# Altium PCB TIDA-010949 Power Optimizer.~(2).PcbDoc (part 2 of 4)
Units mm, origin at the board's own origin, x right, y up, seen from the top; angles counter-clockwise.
Board outline 129.4 x 84 mm, 4 copper layers (Power1, Ground1, Ground2, Power2), stack 1.926 mm thick; 262 components, 129 nets, 791 pads, 1191 vias.

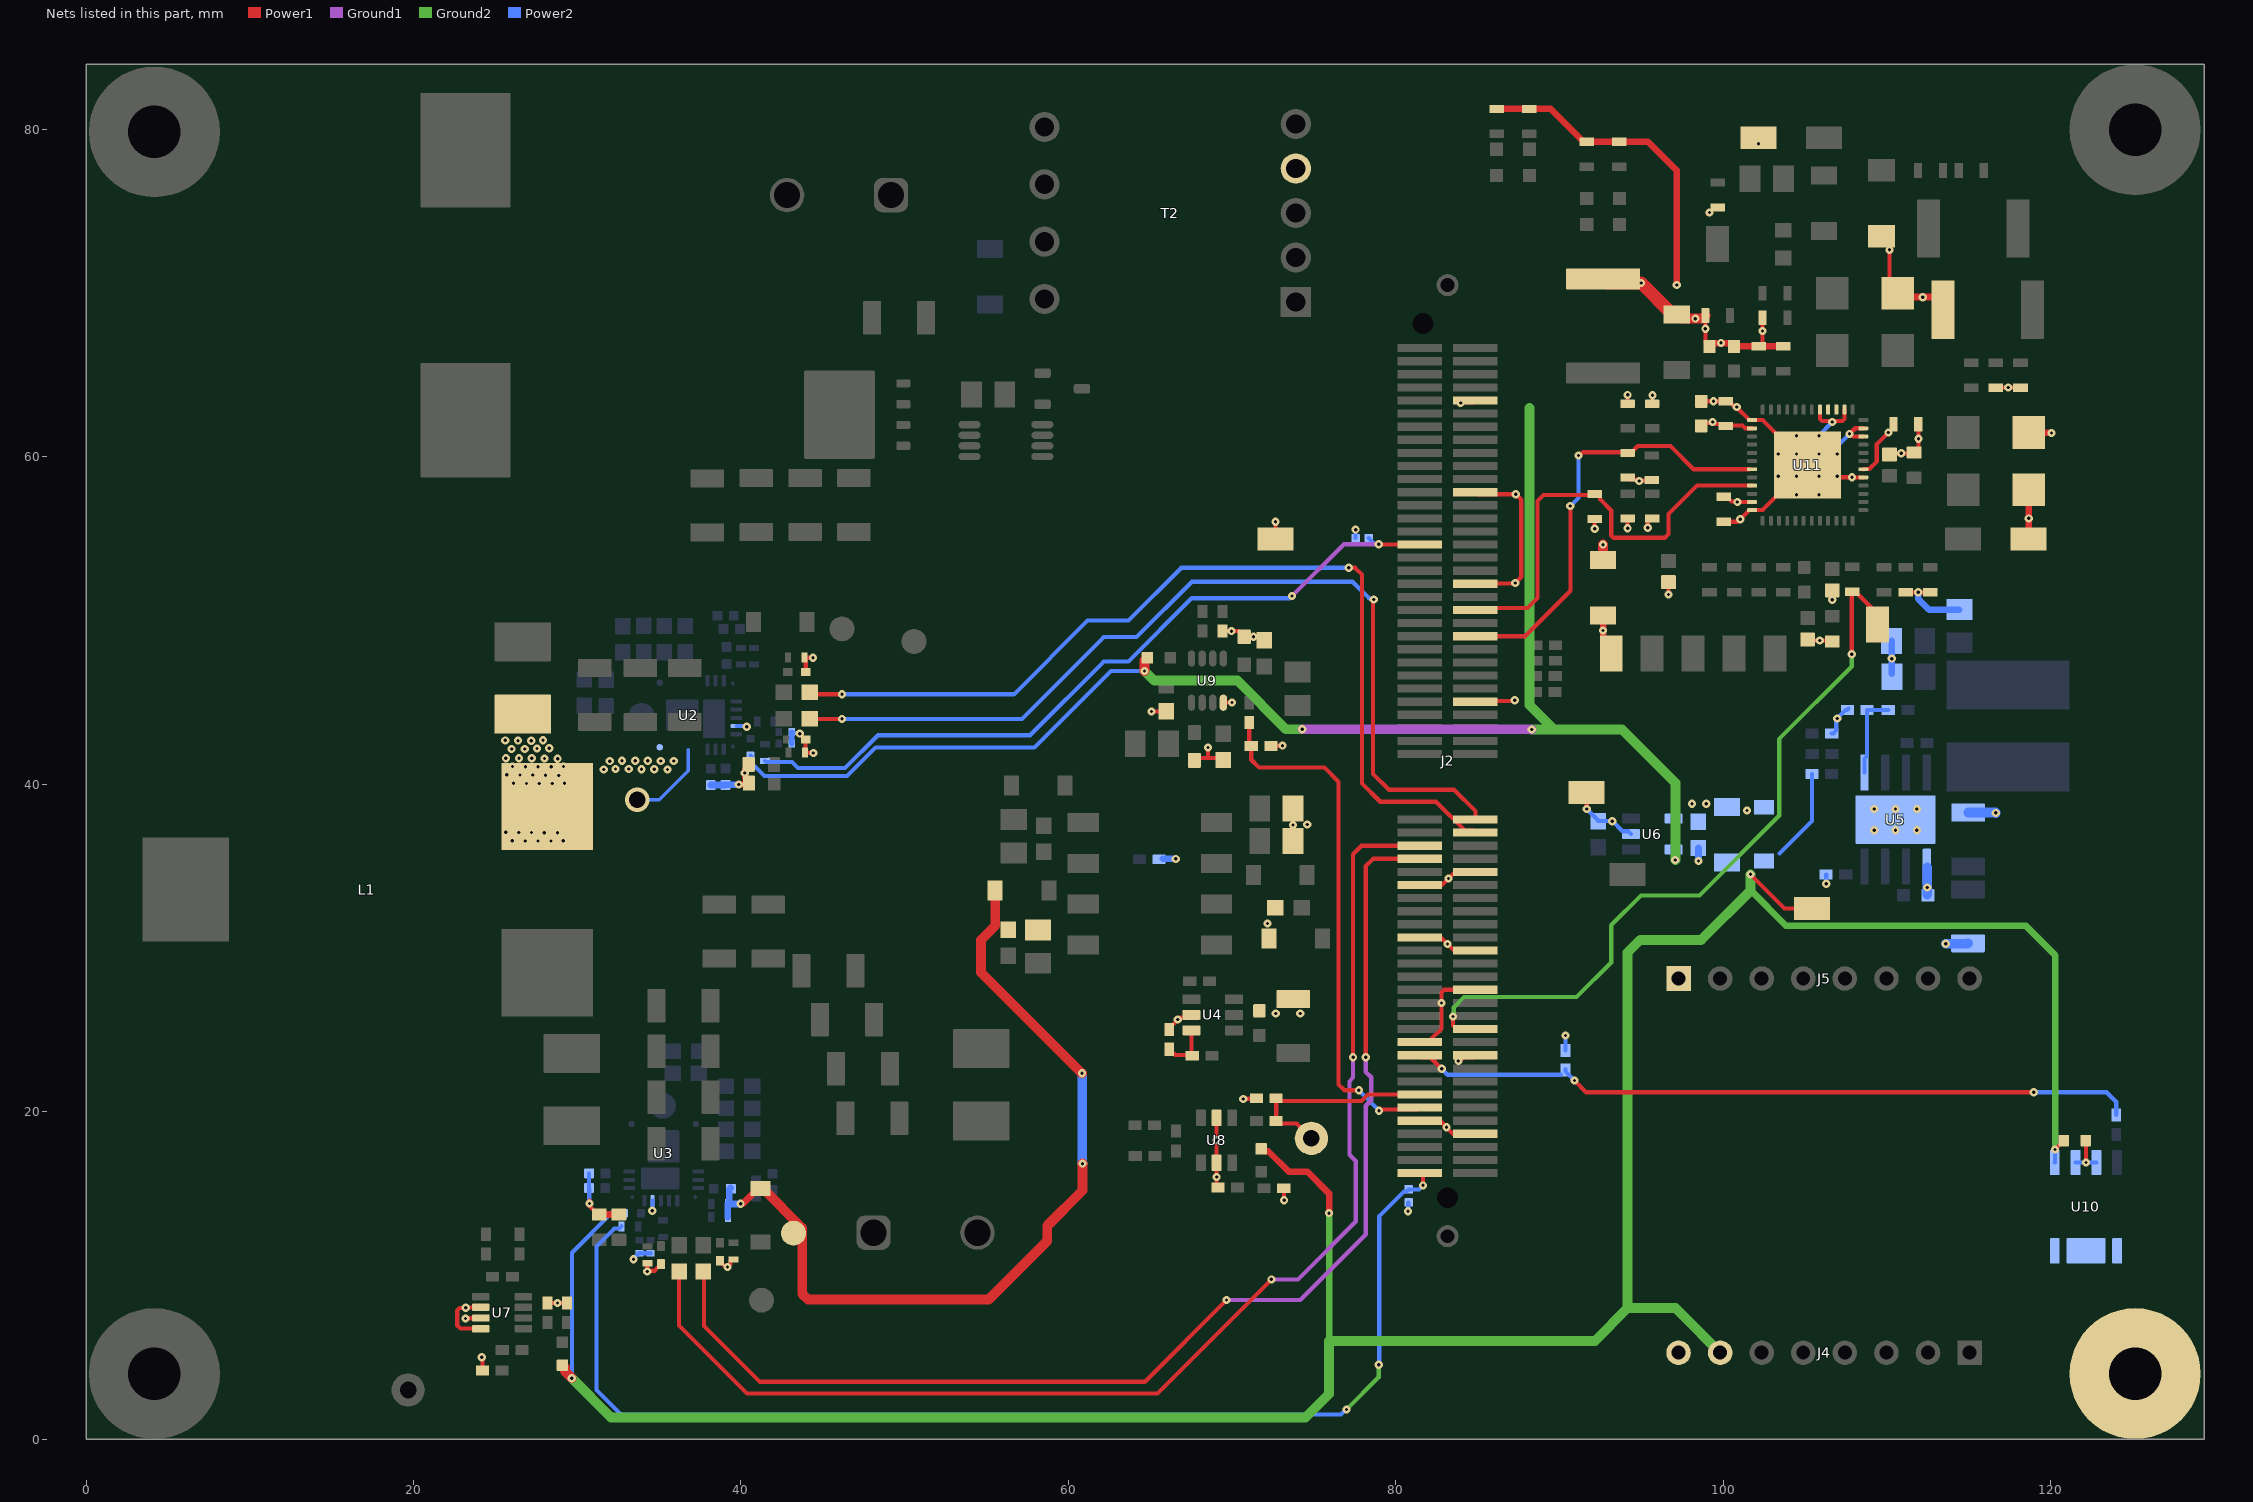
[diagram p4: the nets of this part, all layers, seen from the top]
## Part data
C1: library part CMP-0007679-2, "CAP, CERM, 2.2 uF, 16 V, +/- 10%, X5R, 0805", Cap_Case=0805, Manufacturer=AVX, Supplier Part Number 1=478-2580-1-ND, TempCo=X5R, Tolerance_%=10%, Value1="0.009 ohm", Value2=16V, ValueDisplayed=2.2uF
C2 C3 C4 C21 C22 C23 C24 C25 C26 C27 C28 C29: library part CMP-0077894-3, "CAP, CERM, 0.22 µF, 100 V,+/- 10%, X7S, AEC-Q200 Grade 1, 0603", Cap_Case=0603, Manufacturer="Taiyo Yuden", Supplier Part Number 1=587-5012-1-ND, TempCo=X7S, Tolerance_%=10%, Value2=100V, ValueDisplayed=0.22µF
C5 C6 C7 C8 C9 C10 C11 C12 C13 C14 C15 C16 C17 C18 C19 C20 C47 C52 C53 C60 C61: library part CMP-0087970-1, "10µF ±10% 100V Ceramic Capacitor X7S 1210 (3225 Metric)", Manufacturer=Murata, TempCo=22%, Tolerance_%=0.1, ValueDisplayed=10uF
C30 C31 C65 C67: library part CMP-0006659-2, "CAP, CERM, 0.1 uF, 25 V, +/- 10%, X7R, 0402", Cap_Case=0402, Manufacturer=MuRata, Supplier Part Number 1=490-10698-1-ND, TempCo=X7R, Tolerance_%=10%, Value1=Unknown, Value2=25V, ValueDisplayed=0.1uF
C32 C33 C34 C35: library part CMP-0097874-1, "10 pF ±1% 50V Ceramic Capacitor C0G, NP0 0402 (1005 Metric)", Digikey Part Number=478-5717-1-ND, Manufacturer="KYOCERA AVX", Mouser Part Number=581-04025U100FAT2A, Operating Temperature Range="-55°C to +125°C", TempCo=30ppm/°C, Temperature Characteristic=C0G, Tolerance_%=1%, ValueDisplayed=10pF
C36 C37 C40 C41: library part CMP-0089452-2, "2.2µF ±10% 16V Ceramic Capacitor X7S 0603 (1608 Metric)", Digikey Part Number=490-12731-1-ND, Manufacturer=Murata, Mouser Part Number=81-GRM188C71C225KE1D, Operating Temperature Range="-55°C to +125°C", TempCo=22%, Temperature Characteristic=X7S, Tolerance_%=10%, ValueDisplayed=2.2uF
C38 C42: library part CMP-0096845-1, "Multi-Layer Ceramic Capacitor 100pF 25V C0G ±5% 0402 Paper T/R", Manufacturer=Murata, Operating Temperature Range="-55°C to +125°C", TempCo=30ppm/°C, Temperature Characteristic=C0G, Tolerance_%=5%, ValueDisplayed=100pF
C39 C43: library part CMP-0096975-1, "Multi-Layer Ceramic Capacitor 1uF 25V X5R ±10% 0402 Paper T/R", Manufacturer=Murata, Operating Temperature Range="-55°C to +85°C", TempCo=0.15, Temperature Characteristic=X5R, Tolerance_%=10%, ValueDisplayed=1uF
C44 C45 C50 C51 C57 C58 C59: library part CMP-0007677-2, "CAP, CERM, 10 uF, 16 V, +/- 10%, X5R, 0805", Cap_Case=0805, Manufacturer=AVX, Supplier Part Number 1=478-5165-1-ND, TempCo=X5R, Tolerance_%=10%, Value1=Unknown, Value2=16V, ValueDisplayed=10uF
C46: library part CMP-0006201-2, "CAP, CERM, 0.1 uF, 16 V, +/- 10%, X7R, 0402", Cap_Case=0402, Manufacturer=AVX, Supplier Part Number 1=478-7888-1-ND, TempCo=X7R, Tolerance_%=10%, Value1=Unknown, Value2=16V, ValueDisplayed=0.1uF
C48 C55 C96 C97 C104: library part CMP-0094779-1, "Cap Ceramic 100nF 100V X7R 10% SMD 0603 125°C Paper T/R", Digikey Part Number=478-06031C104K4T2ACT-ND, Manufacturer="KYOCERA AVX", Mouser Part Number=581-06031C104K4T2A, Operating Temperature Range="-55°C to +125°C", TempCo=15%, Temperature Characteristic=X7R, Tolerance_%=10%, ValueDisplayed=100nF
C49: library part CMP-0006683-2, "CAP, CERM, 2200 pF, 50 V, +/- 10%, X7R, 0402", Cap_Case=0402, Manufacturer=MuRata, Supplier Part Number 1=490-1305-1-ND, TempCo=X7R, Tolerance_%=10%, Value1=Unknown, Value2=50V, ValueDisplayed=2200pF
C54 C77: library part CMP-0006752-5, "CAP, CERM, 0.1 uF, 25 V, +/- 5%, X7R, 0603", Cap_Case=0603, Manufacturer=AVX, Supplier Part Number 1=478-3713-1-ND, TempCo=X7R, Tolerance_%=5%, Value1="0.05 ohm", Value2=25V, ValueDisplayed=0.1uF
C56: library part CMP-0006640-2, "CAP, CERM, 0.1 uF, 16 V, +/- 5%, X7R, 0402", Cap_Case=0402, Manufacturer=MuRata, Supplier Part Number 1=490-6327-1-ND, TempCo=X7R, Tolerance_%=5%, Value1=Unknown, Value2=16V, ValueDisplayed=0.1uF
C62 C64: library part CMP-0006831-4, "CAP CER 1UF 16V Y5V 0603", Cap_Case=0603, Manufacturer=Yageo, PartNumber=CC0603MRY5V7BB105, Supplier Part Number 1=311-3414-1-ND, TempCo=X7R, Tolerance_%=10%, Value1=Unknown, Value2=16V, ValueDisplayed=1uF
C63: library part CMP-0008965-2, "CAP, CERM, 10 uF, 25 V, +/- 10%, X7R, 1206", Cap_Case=2220, Manufacturer=MuRata, Supplier Part Number 1=81-GRM31CR71E106KA12, TempCo=X7R, Tolerance_%=10%, Value1=Unknown, Value2=25V, ValueDisplayed=10uF
C66 C68: library part CMP-0078625-1, "CAP, CERM, 1 µF, 25 V,+/- 20%, X5R, 0402", Cap_Case=0402, Manufacturer=MuRata, Supplier Part Number 1=490-10018-1-ND, TempCo=X5R, Tolerance_%=20%, Value2=25V, ValueDisplayed=1µF
C69 C71: library part CMP-0006658-2, "CAP, CERM, 0.01 uF, 25 V, +/- 10%, X7R, 0402", Cap_Case=0402, Manufacturer=MuRata, Supplier Part Number 1=490-1312-1-ND, TempCo=X7R, Tolerance_%=10%, Value1=Unknown, Value2=25V, ValueDisplayed=0.01uF
C70 C72: library part CMP-0006389-2, "CAP, CERM, 470 pF, 25 V, +/- 5%, C0G/NP0, 0402", Cap_Case=0402, Manufacturer=MuRata, Supplier Part Number 1=GRM1555C1E471JA01D-ND, TempCo=C0G/NP0, Tolerance_%=5%, Value1=Unknown, Value2=25V, ValueDisplayed=470pF
C73 C75: library part CMP-0860530-1, "CAP, CERM, 1000 pF, 25 V,+/- 5%, C0G/NP0, 0603", Cap_Case=0603, Manufacturer=Yageo, TempCo=C0G/NP0, Tolerance_%=5%, Value2=25V, ValueDisplayed=1000pF
C74 C76: library part CMP-0006453-2, "CAP, CERM, 300 pF, 50 V, +/- 5%, C0G/NP0, 0402", Cap_Case=0402, Manufacturer=MuRata, Supplier Part Number 1=490-3234-1-ND, TempCo=C0G/NP0, Tolerance_%=5%, Value1=Unknown, Value2=50V, ValueDisplayed=300pF
C78 C79: library part CMP-0006608-2, "CAP, CERM, 1 uF, 25 V, +/- 10%, X5R, 0402", Cap_Case=0402, Manufacturer=MuRata, Supplier Part Number 1=490-10017-1-ND, TempCo=X5R, Tolerance_%=10%, Value1=Unknown, Value2=25V, ValueDisplayed=1uF
C80 C83 C93 C95: library part CMP-0045719-1, "1000 pF ±10% 50V Ceramic Capacitor X7R 0603 (1608 Metric)", Digikey Part Number=399-C0603X102K5RAC7867CT-ND, Manufacturer=KEMET, Mouser Part Number=80-C0603X102K5R, Operating Temperature Range="-55°C to +125°C", TempCo=15%, Temperature Characteristic=X7R, Tolerance_%=10%, ValueDisplayed=1000pF
C81 C101 C106: library part CMP-0009015-2, "CAP, CERM, 10 uF, 50 V, +/- 10%, X5R, AEC-Q200 Grade 1, 1206", Cap_Case=1206, Manufacturer=MuRata, Supplier Part Number 1=490-12456-1-ND, TempCo=X5R, Tolerance_%=10%, Value1=Unknown, Value2=50V, ValueDisplayed=10uF
C82: library part CMP-0089171-1, "3300pF ±5% 100V Ceramic Capacitor X7R 0603 (1608 Metric)", Digikey Part Number=478-7420-1-ND, Manufacturer="AVX Corporation", Mouser Part Number=581-06031C332J4Z2A, Operating Temperature Range="-55°C to +125°C", TempCo=15%, Temperature Characteristic=X7R, Tolerance_%=5%, ValueDisplayed=3300pF
C84: library part CMP-0008779-2, "CAP, CERM, 1 uF, 100 V, +/- 10%, X7R, AEC-Q200 Grade 1, 1206", Cap_Case=1206_180, Manufacturer=TDK, Supplier Part Number 1=445-5845-1-ND, TempCo=X7R, Tolerance_%=10%, Value1="0.004575 ohm", Value2=100V, ValueDisplayed=1uF
C85: library part CMP-0007433-4, "CAP, CERM, 0.01 uF, 50 V, +/- 10%, X7R, 0603", Cap_Case=0603, Manufacturer=MuRata, Supplier Part Number 1=490-1512-1-ND, TempCo=X7R, Tolerance_%=10%, Value1=Unknown, Value2=50V, ValueDisplayed=0.01uF
C86 C99 C100 C102 C103 C105: library part CMP-0750039-1, "CAP, CERM, 0.01 µF, 50 V,+/- 10%, X7R, 0603", Cap_Case=0603, Manufacturer="Wurth Elektronik", TempCo=X7R, Tolerance_%=10%, Value2=50V, ValueDisplayed=0.01µF
C87: library part CMP-0007192-4, "CAP, CERM, 1800 pF, 50 V, +/- 5%, C0G/NP0, 0603", Cap_Case=0603, Manufacturer=MuRata, Supplier Part Number 1=490-1457-1-ND, TempCo=C0G/NP0, Tolerance_%=5%, Value1=Unknown, Value2=50V, ValueDisplayed=1800pF
C88: library part CMP-0006764-4, "CAP, CERM, 1000 pF, 50 V, +/- 10%, C0G/NP0, 0603", Cap_Case=0603, Manufacturer=AVX, Supplier Part Number 1=478-3718-1-ND, TempCo=C0G/NP0, Tolerance_%=10%, Value1="0.048 ohm", Value2=50V, ValueDisplayed=1000pF
C89: library part CMP-0007164-4, "CAP, CERM, 560 pF, 25 V, +/- 5%, C0G/NP0, 0603", Cap_Case=0603, Manufacturer=MuRata, Supplier Part Number 1=GRM1885C1E561JA01D-ND, TempCo=C0G/NP0, Tolerance_%=5%, Value1=Unknown, Value2=25V, ValueDisplayed=560pF
C90: library part CMP-0007203-4, "CAP, CERM, 270 pF, 50 V, +/- 5%, C0G/NP0, 0603", Cap_Case=0603, Manufacturer=MuRata, Supplier Part Number 1=490-1437-1-ND, TempCo=C0G/NP0, Tolerance_%=5%, Value1=Unknown, Value2=50V, ValueDisplayed=270pF
C91: library part CMP-0006729-4, "CAP, CERM, 1200 pF, 100 V, +/- 5%, X7R, 0603", Cap_Case=0603, Manufacturer=AVX, Supplier Part Number 1=478-3702-1-ND, TempCo=X7R, Tolerance_%=5%, Value1="0.254 ohm", Value2=100V, ValueDisplayed=1200pF
C92 C94: library part CMP-0122291-1, "1 µF ±10% 50V Ceramic Capacitor X7T 0603 (1608 Metric)", Digikey Part Number=490-GCM188D71H105KE36JCT-ND, Manufacturer=Murata, Mouser Part Number=81-GCM188D71H105KE6J, Operating Temperature Range="-55°C to +125°C", TempCo=+22/-33%, Temperature Characteristic=X7T, Tolerance_%=10%, ValueDisplayed=1uF
C98: library part CMP-0093976-1, "Cap Ceramic 47uF 25V X7R 20% Pad SMD 2220 +125°C Automotive T/R", Manufacturer=TDK, Operating Temperature Range="-55°C to +125°C", TempCo=0.15, Temperature Characteristic=X7R, Tolerance_%=0.2%, ValueDisplayed=47uF
C107: library part CMP-0090409-1, "0.1µF ±10% 16V Ceramic Capacitor X7R 0603 (1608 Metric)", Digikey Part Number=490-5796-1-ND, Manufacturer="Murata Electronics North America", Mouser Part Number=81-GCJ188R71C104KA1D, Operating Temperature Range="-55°C to +125°C", TempCo=15%, Temperature Characteristic=X7R, Tolerance_%=10%, ValueDisplayed=0.1uF
C108: library part CMP-0006561-2, "CAP, CERM, 0.01 uF, 10 V, +/- 10%, X5R, 0402", Cap_Case=0402, Manufacturer=MuRata, Supplier Part Number 1=GRM155R61A103KA01D-ND, TempCo=X5R, Tolerance_%=10%, Value1=Unknown, Value2=10V, ValueDisplayed=0.01uF
C109 C110: library part CMP-0098338-1, "100 pF ±5% 16V Ceramic Capacitor C0G, NP0 0402 (1005 Metric)", Digikey Part Number=399-C0402C101J4GAC7867CT-ND, Manufacturer=KEMET, Mouser Part Number=80-C0402C101J4G, Operating Temperature Range="-55°C to +125°C", TempCo=30ppm/°C, Temperature Characteristic=C0G, Tolerance_%=5%, ValueDisplayed=100pF
D1 D4 D5: library part CMP-0028543-2, "Diode, Schottky, 40 V, 0.35 A, SOD-123", Manufacturer="Diodes Inc.", Value1=0.35A, Value2=0.55V
D2 D3 D6: library part CMP-0077599-3, "Diode, Zener, 5.1 V, 500 mW, SOD-123", Manufacturer=Vishay-Semiconductor, Power_W=500mW, Value1=0.5W
D7 D15: library part CMP-0002946-3, "LED, Blue, SMD", Color=Blue, Manufacturer="Wurth Elektronik", Power_TotalModule=105mW, Value1=0.105W, Value2=3.2V
D8: library part CMP-0005782-1, "Diode, Zener, 3.6 V, 500 mW, SOD-123", Manufacturer="ON Semiconductor", PartNumber=MMSZ4685T1G, Power_W=500mW, Supplier Part Number 1=MMSZ4685T1GOSCT-ND, Value1=0.5W
D9 D11 D13 D14: library part CMP-0028416-2, "Diode, Schottky, 50 V, 3 A, SMA", Manufacturer="Diodes Inc.", Value1=3A, Value2=0.7V
D10: library part CMP-0085011-1, "Diode, TVS, Bi, 22 V, 35.5 Vc, 400 W, 11.3 A, SMA (non-polarized)", Manufacturer=Littelfuse, Value1=35.5V
D12 D16: library part CMP-0002947-3, "LED, Red, SMD", Color=Red, Manufacturer="Wurth Elektronik", Power_TotalModule=72mW, Value1=0.072W, Value2=2V
FB1 FB2 FB3: library part CMP-0037505-1, "600 Ohms @ 100 MHz 1 Power, Signal Line Ferrite Bead 0603 (1608 Metric) 1A 200mOhm", Digikey Part Number=MH1608-601YCT-ND, Impedance At Frequency="600Ω @ 100MHz", Manufacturer=Bourns, Mouser Part Number=652-MH1608-601Y, Operating Temperature Range="-55°C to +125°C", Test Frequency=100MHz, Tolerance_%=25%
H1 H2 H3 H4: library part CMP-0003617-1, "Machine Screw, Round, #4-40 x 1/4, Nylon, Philips panhead", Manufacturer="B&F Fastener Supply", Supplier Part Number 1=H542-ND
H5 H6 H7 H8: library part CMP-0003610-1, "Standoff, Hex, 0.5\"L #4-40 Nylon", Manufacturer=Keystone, Supplier Part Number 1=36-1902C-ND
J1 J3: library part CMP-0075360-1, "Terminal Block, 6.35mm, 2x1, TH", Color=Green, Current_A=30A, Manufacturer="On-Shore Technology", Supplier Part Number 1=ED2675-ND, Voltage_V=300V
J2: library part CMP-0003814-2, "C2000 controlCARD-120HSEC connector, SMT", Manufacturer=Samtec
J4 J5: library part CMP-0055090-1, "Header, 100mil, 8x1, TH", Manufacturer=Mill-Max, Supplier Part Number 1=ED7208-ND
L1: library part CMP-0086005-1, "Inductor, Shielded, Ferrite, 10 µH, 30 A, 0.0024 ohm, SMD", Manufacturer="Wurth Elektronik", Value1="0.0024 ohm", Value2=30A, ValueDisplayed=10µH
L2: library part CMP-0102060-1, "WE-PD2SA SMT Power Inductor, size 7850, 68uH, 1.12A, 290mOhm", Case/Size Code=7850, DC Resistance=246mOhm, DC Resistance Max=290mOhm, Inductance=68uH, Manufacturer="Wurth Elektronik", Operating Temperature Max=150°C, Operating Temperature Min=-50°C, Rated Current=1.12A, Saturation Current=1A, Self Resonant Frequency=7.5MHz
L3: library part CMP-0058657-1, "Inductor, Wirewound, Ferrite, 1 uH, 0.595 A, 0.25 ohm, SMD", Manufacturer=MuRata, Value1="0.25 ohm", Value2=0.595A, ValueDisplayed=1uH
L4: library part CMP-0089572-1, "12µH Shielded Wirewound Inductor 19A 4.3mOhm Nonstandard", Digikey Part Number=732-4236-1-ND, Manufacturer="Wurth Electronics", Mouser Part Number=710-74435581200, Operating Temperature Range="-40°C to +125°C", Self Resonant Frequency=13MHz, Test Frequency=100kHz, Tolerance_%=20%
L5: library part CMP-0061680-2, "Inductor, Drum Core, Ferrite, 1 mH, 0.1 A, 19 ohm, SMD", Manufacturer=Coilcraft, Value1="19 ohm", Value2=0.1A, ValueDisplayed=1mH
L6: library part CMP-0061972-2, "Inductor, Drum Core, Ferrite, 1.5 mH, 0.08 A, 21 ohm, SMD", Manufacturer=Coilcraft, Value1="21 ohm", Value2=0.08A, ValueDisplayed=1.5mH
LBL1: library part CMP-0003625-1, "Thermal Transfer Printable Labels, 0.650\" W x 0.200\" H - 10,000 per roll", Manufacturer=Brady, Supplier Part Number 1=97C5133
Logo1: library part CMP-0074838-1, "Texas Instrument Corporate Signature"
Logo2: library part CMP-0074844-1
Logo3: library part CMP-0074847-1, "FCC_disclaimer"
Logo4: library part CMP-0074769-1
Q1: library part CMP-0000958-3, "MOSFET, N-CH, 100 V, 17 A, DNK0008A (VSON-CLIP-8)", Alternate Manufacturer=None, Manufacturer="Texas Instruments", Supplier Part Number 1=296-37478-6-ND, Value2="48 nC"
Q2: library part CMP-0000949-3, "MOSFET, N-CH, Depletion Mode, 100 V, 0.17 A, AEC-Q101, SOT-23", Alternate Manufacturer=None, Manufacturer="Infineon Technologies", Supplier Part Number 1="BSS169 H6327-ND", Value2="2.1 nC"
R1: library part CMP-0094948-1, "0 Ohms Jumper 0.1W, 1/10W Chip Resistor 0402 (1005 Metric) - Thick Film", Digikey Part Number=2679-CR0402-10W-000TTR-ND, Manufacturer=Venkel, Operating Temperature Range="-55°C to +155°C", Power_W=100mW
R2 R6 R35: library part CMP-0042666-1, "Res Metal Strip 2512 0.001 Ohm 1% 3W ±50ppm/C Pad SMD Automotive T/R", Manufacturer="TT Electronics", Mouser Part Number=66-ULRG3R001FLFSLT, Operating Temperature Range=to, Power_W=3W, TempCo=50ppm/°C, Tolerance_%=1%
R3 R4: library part CMP-0097912-1, "Res Thick Film 0402 0 Ohm 1/16W Molded SMD", Digikey Part Number=541-1887-1-ND, Manufacturer="Vishay Dale", Mouser Part Number=71-RCG04020000Z0ED, Operating Temperature Range="-55°C to +155°C", Power_W=63mW
R5 R7: library part CMP-0026262-2, "RES, 2.00, 1%, 0.063 W, AEC-Q200 Grade 0, 0402", Manufacturer=Vishay-Dale, Power_W=63mW, Supplier Part Number 1=541-2.00LLCT-ND, TempCo="100 ppm/C", Tolerance_%=1%, Value2=0.063W, Value_Code=2R00, ValueDisplayed=2.00
R8 R9 R14 R15: library part CMP-0078781-1, "RES, 10.5 k, 1%, 0.063 W, 0402", Manufacturer="Yageo America", Power_W=63mW, Supplier Part Number 1=YAG2951CT-ND, TempCo="100 ppm/C", Tolerance_%=1%, Value2=0.063W, Value_Code=10k5, ValueDisplayed=10.5k
R10 R11 R12 R13: library part CMP-0022908-4, "RES, 20.0, 1%, 0.1 W, 0603", Manufacturer=Yageo, Power_W=100mW, Supplier Part Number 1=311-20.0HRCT-ND, TempCo="100 ppm/C", Tolerance_%=1%, Value2=0.1W, Value_Code=20R0, ValueDisplayed=20.0
R16 R17 R58: library part CMP-0022895-5, "RES, 1.00 k, 1%, 0.1 W, 0603", Manufacturer=Yageo, Power_W=100mW, Supplier Part Number 1=311-1.00KHRCT-ND, TempCo="100 ppm/C", Tolerance_%=1%, Value2=0.1W, Value_Code=1k00, ValueDisplayed=1.00k
R18 R24 R26 R27 R28 R73 R75: library part CMP-0026936-3, "RES, 47, 5%, 0.063 W, AEC-Q200 Grade 0, 0402", Manufacturer=Vishay-Dale, Power_W=63mW, Supplier Part Number 1=541-47JCT-ND, TempCo="200 ppm/C", Tolerance_%=5%, Value2=0.063W, Value_Code=47R0, ValueDisplayed=47
R19: library part CMP-0025971-3, "RES, 115 k, 1%, 0.063 W, AEC-Q200 Grade 0, 0402", Manufacturer=Vishay-Dale, Power_W=63mW, Supplier Part Number 1=541-115KLCT-ND, TempCo="100 ppm/C", Tolerance_%=1%, Value2=0.063W, Value_Code=115k
R20: library part CMP-0026457-2, "RES, 57.6 k, 1%, 0.063 W, AEC-Q200 Grade 0, 0402", Manufacturer=Vishay-Dale, Power_W=63mW, Supplier Part Number 1=541-57.6KLCT-ND, TempCo="100 ppm/C", Tolerance_%=1%, Value2=0.063W, Value_Code=57k6, ValueDisplayed=57.6k
R21 R23: library part CMP-0026825-5, "RES, 10 k, 5%, 0.063 W, AEC-Q200 Grade 0, 0402", Manufacturer=Vishay-Dale, Power_W=63mW, Supplier Part Number 1=541-10KJCT-ND, TempCo="200 ppm/C", Tolerance_%=5%, Value2=0.063W, Value_Code=10k0, ValueDisplayed=10k
R22: library part CMP-0026543-2, "RES, 75.0 k, 1%, 0.063 W, AEC-Q200 Grade 0, 0402", Manufacturer=Vishay-Dale, Power_W=63mW, Supplier Part Number 1=541-75.0KLCT-ND, TempCo="100 ppm/C", Tolerance_%=1%, Value2=0.063W, Value_Code=75k0, ValueDisplayed=75.0k
R25: library part CMP-0025958-3, "RES, 10.0 k, 1%, 0.063 W, AEC-Q200 Grade 0, 0402", Manufacturer=Vishay-Dale, Power_W=63mW, Supplier Part Number 1=541-10.0KLCT-ND, TempCo="100 ppm/C", Tolerance_%=1%, Value2=0.063W, Value_Code=10k0, ValueDisplayed=10.0k
R29 R61 R62 R76: library part CMP-0025936-5, "RES, 680, 5%, 0.1 W, 0603", Manufacturer=Yageo, Power_W=100mW, Supplier Part Number 1=311-680GRCT-ND, TempCo="100 ppm/C", Tolerance_%=5%, Value2=0.1W, Value_Code=680R, ValueDisplayed=680
R30 R38: library part CMP-0025923-5, "RES, 43 k, 5%, 0.1 W, 0603", Manufacturer=Yageo, Power_W=100mW, Supplier Part Number 1=311-43KGRCT-ND, TempCo="100 ppm/C", Tolerance_%=5%, Value2=0.1W, Value_Code=43k0, ValueDisplayed=43k
R31 R32 R63: library part CMP-0026751-1, "RES, 47.0, 1%, 0.063 W, 0402", Manufacturer="KOA Speer", Power_W=63mW, Supplier Part Number 1=660-RK73H1ETTP47R0F, TempCo="100 ppm/C", Tolerance_%=1%, Value2=0.063W, Value_Code=47R0, ValueDisplayed=47.0
R33 R34 R36 R37: library part CMP-0026749-1, "RES, 10.0, 1%, 0.063 W, 0402", Manufacturer="KOA Speer", Power_W=63mW, Supplier Part Number 1=660-RK73H1ETTP10R0F, TempCo="100 ppm/C", Tolerance_%=1%, Value2=0.063W, Value_Code=10R0, ValueDisplayed=10.0
R39 R51: library part CMP-0025928-5, "RES, 510, 5%, 0.1 W, 0603", Manufacturer=Yageo, Power_W=100mW, Supplier Part Number 1=311-510GRCT-ND, TempCo="100 ppm/C", Tolerance_%=5%, Value2=0.1W, Value_Code=510R, ValueDisplayed=510
R40 R41: library part CMP-0019234-2, "RES, 30.1 k, 0.5%, 0.1 W, 0805", Manufacturer="Susumu Co Ltd", Power_W=100mW, Supplier Part Number 1=RR12P30.1KDCT-ND, TempCo="25 ppm/C", Tolerance_%=0.5%, Value2=0.1W, Value_Code=30k1, ValueDisplayed=30.1k
R42 R44: library part CMP-0026454-2, "RES, 56.2, 1%, 0.063 W, AEC-Q200 Grade 0, 0402", Manufacturer=Vishay-Dale, Power_W=63mW, Supplier Part Number 1=541-56.2LCT-ND, TempCo="100 ppm/C", Tolerance_%=1%, Value2=0.063W, Value_Code=56R2, ValueDisplayed=56.2
R43 R45: library part CMP-0088560-2, "High Precision-High Stability Chip Resistor Thin Film 0603 1kOhm 0.1% Paper T/R", Digikey Part Number=YAG1237CT-ND, Manufacturer=Yageo, Mouser Part Number=603-RT0603BRD071KL, Operating Temperature Range="-55°C to +155°C", Power_W=100mW, TempCo=25ppm/°C, Tolerance_%=0.1%
R46 R47 R48 R49 R53 R54 R60: library part CMP-0098286-1, "10 kOhms ±5% 0.1W, 1/10W Chip Resistor 0603 (1608 Metric) Thick Film", Digikey Part Number=541-CRCW060310K0JNEBCCT-ND, Manufacturer=Vishay, Mouser Part Number=71-CRCW060310K0JNEBC, Operating Temperature Range="-55°C to +155°C", Power_W=100mW, TempCo=200ppm/°C, Tolerance_%=5%
R50 R52: library part CMP-0022735-5, "RES, 100 k, 1%, 0.1 W, 0603", Manufacturer=Yageo, Power_W=100mW, Supplier Part Number 1=311-100KHRCT-ND, TempCo="100 ppm/C", Tolerance_%=1%, Value2=0.1W, Value_Code=100k
R55: library part CMP-0025913-5, "RES, 33 k, 5%, 0.1 W, 0603", Manufacturer=Yageo, Power_W=100mW, Supplier Part Number 1=311-33KGRCT-ND, TempCo="100 ppm/C", Tolerance_%=5%, Value2=0.1W, Value_Code=33k0, ValueDisplayed=33k
R56: library part CMP-0020737-3, "RES, 4.7, 5%, 0.125 W, AEC-Q200 Grade 0, 0805", Manufacturer=Panasonic, Power_W=125mW, Supplier Part Number 1=P4.7ACT-ND, TempCo="600 ppm/C", Tolerance_%=5%, Value2=0.125W, Value_Code=4R70, ValueDisplayed=4.7
R57: library part CMP-0025912-5, "RES, 330, 5%, 0.1 W, 0603", Manufacturer=Yageo, Power_W=100mW, Supplier Part Number 1=311-330GRCT-ND, TempCo="100 ppm/C", Tolerance_%=5%, Value2=0.1W, Value_Code=330R, ValueDisplayed=330
R59: library part CMP-0022986-5, "RES, 2.20 k, 1%, 0.1 W, 0603", Manufacturer=Yageo, Power_W=100mW, Supplier Part Number 1=311-2.20KHRCT-ND, TempCo="100 ppm/C", Tolerance_%=1%, Value2=0.1W, Value_Code=2k20, ValueDisplayed=2.20k
R64 R65 R66 R67 R68 R69 R70 R71: library part CMP-0031873-1, "0 Ohms Jumper Chip Resistor 0402 (1005 Metric) Anti-Sulfur, Current Sense, Flame Retardant Coating, Moisture Resistant, Safety Metal Foil", Digikey Part Number=4463-D1LPC0402CJUMPF-T10CT-ND, Manufacturer="Thin Film Technology", Max Current=20A, Operating Temperature Range="-55°C to +170°C"
R72 R74: library part CMP-0094624-1, "4.7 kOhms ±5% 0.1W, 1/10W Chip Resistor 0402 (1005 Metric) Automotive AEC-Q200 Thick Film", Digikey Part Number=10-ERJ-H2GJ472XCT-ND, Manufacturer=Panasonic, Mouser Part Number=667-ERJ-H2GJ472X, Operating Temperature Range="-55°C to +175°C", Power_W=100mW, TempCo=200ppm/°C, Tolerance_%=5%
T1: library part "EP7, 070-7148", "EP7 8-Term., SMT, Horizontal", Manufacturer="Würth Elektronik Midcom", Package=EP7
T2: library part CMP-0030703-1, "Transformer, 870uH. TH", Manufacturer="Wurth Elektronik", ValueDisplayed=870uH
TP1 TP13 TP14 TP15 TP18 TP19 TP20 TP21 TP22 TP23 TP24 TP25 TP26 TP27 TP28: library part CMP-0003968-1, "Test Point, SMT", Manufacturer=Harwin, Supplier Part Number 1=952-2664-1-ND
TP16 TP17: library part CMP-0055138-2, "Test Point, Miniature, Black, TH", Color=Black, Manufacturer="Keystone Electronics", Supplier Part Number 1=36-5001-ND
U1: library part CMP-0076397-2, "Zero Iq Reverse Polarity Protection Smart Diode Controller, DGK0008A (VSSOP-8)", Alternate Manufacturer="Texas Instruments"
U2 U3: library part CMP-0120692-1, "100-V, 53-A GaN Half-Bridge Power Stage", Manufacturer="Texas Instruments", Max Supply Voltage=5.25V, Min Supply Voltage=4.75V, Nominal Supply Current=12mA, Operating Temperature Range="-40°C to +125°C"
U4: library part CMP-0121876-1, "SIMPLE SWITCHER® Power Converter, 4-V to 42-V, 1-A Buck Converter, SOT23", Manufacturer="Texas Instruments", Max Supply Voltage=42V, Min Supply Voltage=4V, Nominal Supply Current=26.5-420uA, Operating Temperature Range="-40°C to +150°C", Output Voltage=0.8-28V, Switching Frequency=400kHz
U5: library part CMP-0089262-2, "Buck Switching Regulator IC Positive Adjustable 1.2V 1 Output 1A 8-PowerSOIC (0.154\", 3.90mm Width)", Digikey Part Number=296-LM5164DDARCT-ND, Manufacturer="Texas Instruments", Max Supply Voltage=100V, Min Supply Voltage=6V, Mouser Part Number=595-LM5164DDAR, Nominal Supply Current=600uA, Operating Temperature Range="-40°C to +150°C", Output Voltage=1.2-90V, Switching Frequency=1MHz
U6: library part CMP-0092532-1, "300-mA, Ultra-Low-Noise, Low-IQ, High PSRR LDO", Digikey Part Number=296-TPS7A2033PDBVRCT-ND, Dropout Voltage=145mV, Manufacturer="Texas Instruments", Max Supply Voltage=6V, Min Supply Voltage=1.6V, Mouser Part Number=595-TPS7A2033PDBVR, Nominal Supply Current=6.5uA, Operating Temperature Range="-40°C to +125°C", Output Voltage=3.3V
U7: library part CMP-0096511-2, "-4-V to 110-V, Bidirectional, Ultra-Precise Current Sense Amplifier With Enhanced PWM Rejection", Input Bias Current=40uA, Input Offset Voltage=0.025mV, Manufacturer="Texas Instruments", Max Supply Voltage=20V, Min Supply Voltage=2.7V, Nominal Supply Current=2.5mA, Operating Temperature Range="-40°C to +125°C", Voltage Gain=0.05V/mV
U8: library part CMP-0013234-2, "Bidirectional, Low- and High-Side Measurement, Multichannel, Voltage Output, Current-Sense Amplifier, DBV0006A (SOT-6)", Alternate Manufacturer="Texas Instruments"
U9: library part CMP-0086102-1, "TLV9002IDDFR, DDF0008A (SOT-23-THN-8)", Alternate Manufacturer="Texas Instruments"
U10: library part CMP-0122473-1, "Automotive ±1.5°C, 3-kVRMS Isolated Temperature Sensor With Analog Output With < 2 Seconds Response Time and 500VRMS Working Voltage", Manufacturer="Texas Instruments", Max Supply Voltage=5.5V, Min Supply Voltage=2.3V, Operating Supply Current=10uA, Operating Temperature Range="-40°C to +150°C"
U11: library part CMP-0040436-2, "Powerline Communications Analog Front End, 7 to 26 V, -40 to 125 degC, 48-pin QFN (RGZ48), Green (RoHS & no Sb/Br)", Manufacturer="Texas Instruments", Rating=Catalog, Total Supply Voltage(Max)(+5V is 5, +/-5V is 10)=26, Total Supply Voltage(Min)(+5V is 5, +/-5V is 10)=7
?: library part CMP-0074835-1, "IEC 61010-1 High Voltage Warning"

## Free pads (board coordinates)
  round 1.524 smd: 2(43.213,12.58) 3(41.267,8.486) 4(46.174,49.5) 5(50.58,48.73)

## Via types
v1: diameter 0.5, hole 0.2, Power1 to Power2, tented both sides, 1183 vias
v2: diameter 1.5, hole 1, Power1 to Power2, 4 vias
v3: diameter 3.508, hole 3.1, Power1 to Power2, tented both sides, 4 vias

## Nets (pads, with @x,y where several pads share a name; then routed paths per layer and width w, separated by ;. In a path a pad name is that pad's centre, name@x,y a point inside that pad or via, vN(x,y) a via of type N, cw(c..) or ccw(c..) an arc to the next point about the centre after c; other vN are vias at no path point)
3V3: C62.1 C63.1 C102.1 C103.1 C104.2 C105.1 C106.1 C107.2 D8.1 D13.1 FB1.1 FB2.1 FB3.1 J4.7 R21.2 R29.2 R46.2 R47.2 R48.2 R49.2 R55.1 R61.2 R62.2 R72.2 R74.2 R76.2 TP15.1 U6.5 U10.1 U11.2 U11.11 U11.30 | length 303.5
  Power1 w0.254: R61.2@91.483,79.262 R61.2@91.674,79.262 ; v1(92.16,55.618) R55.1@92.16,56.213 ; v1@94.167,63.8 v1(94.174,63.794) R47.2@94.174,63.25 ; v1(94.174,55.643) R46.2@94.174,56.25 ; v1(95.398,55.681) 95.399,55.682 95.399,56.127 95.522,56.25 R48.2@95.674,56.25 ; R49.2@95.674,63.25 95.69,63.266 v1(95.69,63.776) ; C104.2@98.67,61.9 98.852,62.081 99.318,62.081 v1(99.366,62.13) 99.435,62.13 99.55,62.015 100.043,62.015 C105.1@100.17,61.888 100.194,61.912 101.194,61.912 101.349,61.757 101.767,61.757 U11.2@101.774,61.75 ; C102.1@100.045,57.562 100.235,57.562 100.362,57.435 100.362,57.424 100.511,57.275 100.851,57.275 v1(100.876,57.25) U11.11@101.774,57.25 ; v1(101.674,34.5) 103.757,32.417 TP15.1@105.424,32.417 ; U11.30@108.574,59.25 108.581,59.257 108.933,59.257 109.397,59.72 109.397,60.794 110.412,61.81 C103.1@110.412,62 ; v1(120.287,17.687) 120.813,18.213 C107.2@120.813,18.238
  Power1 w0.4: FB2.1@71.789,17.737 71.939,17.587 72.22,17.587 73.464,16.343 74.601,16.343 75.935,15.009 v1(75.935,13.804) ; R29.2@86.174,81.262 R76.2@88.174,81.262 89.483,81.262 R61.2@91.483,79.262 ; R61.2@91.674,79.262 R62.2@93.674,79.262 95.412,79.262 97.174,77.5 v1(97.174,70.5) ; D13.1@118.674,61.5 118.706,61.467 v1(120.066,61.467)
  Power1 w0.6: FB1.1@29.096,4.524 29.246,4.374 29.246,4.143 v1(29.674,3.716) ; v1(64.657,46.931) 64.657,47.556 FB3.1@64.832,47.731 ; C106.1@92.674,53.7 v1(92.674,54.643)
  Ground1 w0.6: v1(74.291,43.363) 88.302,43.363 v1(88.312,43.353)
  Ground2 w0.4: 75.935,6 v1(75.935,13.804) ; 101.674,33.538 103.836,31.375 118.483,31.375 120.287,29.571 v1(120.287,17.687)
  Ground2 w0.6: v1(29.674,3.716) 32.074,1.316 74.49,1.316 75.935,2.762 75.935,6 92.174,6 94.174,8 ; v1(64.657,46.931) 65.249,46.339 70.335,46.339 73.311,43.363 v1(74.291,43.363) ; 88.174,63 88.174,44.853 89.674,43.353 ; v1(88.312,43.353) 89.674,43.353 ; v1@97.091,35.385 97.091,40.088 93.826,43.353 89.674,43.353 ; J4.7@100.139,4.963 97.102,8 94.174,8 ; v1(101.674,34.5) 101.674,33.538 101.674,33.5 98.668,30.494 94.94,30.494 94.174,29.728 94.174,8
  Power2 w0.254: v1(29.674,3.716) 29.674,11.384 32.131,13.841 R74.2@32.709,13.841 ; R72.2@40.593,41.757 40.644,41.706 40.644,41.291 41.435,40.5 46.484,40.5 48.237,42.254 57.927,42.254 62.605,46.931 v1(64.657,46.931) ; C62.1@98.499,36.113 C62.1@98.502,36.11 ; 103.45,35.776 105.436,37.762 R21.2@105.436,40.63 ; U10.1@120.269,16.9 120.278,16.909 120.278,17.678 v1(120.287,17.687)
  Power2 w0.4: v1(98.502,35.315) C62.1@98.502,36.11
  other v1: 97.08,35.374 110.102,61.5
5V_FB: R20.1 R25.2 U4.3 | length 3.1
  Power1 w0.254: R25.2@66.174,23.818 66.174,23.718 66.347,23.545 66.447,23.545 66.524,23.468 67.524,23.468 U4.3@67.524,24.968
ADCIN: J2.23 R57.2 TP27.1 | length 46.6
  Power1 w0.254: v1(83.506,25.813) 83.506,25.267 83.723,25.05 J2.23@84.874,25.05 ; v1(107.864,47.953) 107.864,51.731 R57.2@107.9,51.767 108.091,51.767 TP27.1@109.674,50.184
  Ground2 w0.254: v1(83.506,25.813) 83.555,25.862 83.555,26.381 84.174,27 91.055,27 93.174,29.119 93.174,31.395 94.989,33.211 98.564,33.211 103.432,38.079 103.432,42.759 107.864,47.19 v1(107.864,47.953)
amb_tmp: H2.1 U10.5 U10.6 U10.7
amb_tmp_mcu: C108.1 J2.20 R63.1 | length 44.5
  Power1 w0.254: J2.20@81.474,23.45 81.597,23.327 82.115,23.327 v1(82.814,22.627) ; v1@90.894,21.931 v1(90.924,21.902) 91.634,21.192 v1(118.982,21.192)
  Power2 w0.254: v1(82.814,22.627) 83.181,22.261 C108.1@90.084,22.261 ; C108.1@90.374,22.6 C108.1@90.374,22.55 90.374,22.45 90.922,21.902 v1(90.924,21.902) ; v1(118.982,21.192) 123.437,21.192 124.02,20.609 R63.1@124.02,19.811
BOOST_FLT: C109.2 J2.90 R73.1 | length 46.6
  Power1 w0.254: v1(78.964,54.668) 78.973,54.659 81.465,54.659 J2.90@81.474,54.65
  Ground1 w0.254: v1(73.674,51.5) 76.841,54.668 v1(78.964,54.668)
  Power2 w0.254: R73.1@41.474,41.427 41.532,41.368 43.122,41.368 43.49,41 46.37,41 48.37,43 57.674,43 62.174,47.5 63.674,47.5 67.546,51.373 73.546,51.373 v1(73.674,51.5) ; C109.2@78.355,55.04 78.679,54.716 78.915,54.716 v1(78.964,54.668)
BOOST_HI_PWM: J2.53 R10.1 | length 58.1
  Power1 w0.254: R10.1@44.215,45.635 44.35,45.5 v1(46.174,45.5) ; v1(77.136,53.229) 77.53,53.229 77.941,52.817 77.941,40.055 79.058,38.938 82.471,38.938 84.235,37.173 84.751,37.173 J2.53@84.874,37.05
  Power2 w0.254: v1(46.174,45.5) 56.674,45.5 61.174,50 63.674,50 66.902,53.229 v1(77.136,53.229)
BOOST_LO_PWM: J2.55 R12.1 | length 56.8
  Power1 w0.254: R12.1@44.215,44.01 44.225,44 v1(46.174,44) ; v1(78.662,51.295) 78.618,51.252 78.618,40.641 79.59,39.669 83.57,39.669 84.874,38.365 J2.55@84.874,37.85
  Power2 w0.254: v1(46.174,44) 57.174,44 62.174,49 64.174,49 67.551,52.377 77.359,52.377 78.393,51.344 78.613,51.344 v1(78.662,51.295)
BOOST_SW: L1.2 R6.2 U2.5 | length 5.1
  Power2 w0.2: v2(33.661,39.065) 35.023,39.065 36.793,40.834 36.793,42.11
  other v1: 26.833,36.537 27.6,36.537 28.398,36.537 26.036,36.559 29.154,36.56 28.794,37.036 26.433,37.059 27.213,37.062 27.991,37.046 25.63,37.069 26.908,40.047 27.675,40.047 28.473,40.047 26.112,40.07 29.229,40.071 26.508,40.569 28.066,40.557 28.869,40.547 25.705,40.58 27.289,40.573 31.622,40.912 33.928,40.917 34.709,40.92 35.512,40.91 32.348,40.943 33.151,40.932 26.846,41.067 27.613,41.067 28.411,41.067 26.05,41.09 29.168,41.091 31.987,41.418 35.105,41.42 35.903,41.42 32.744,41.442 33.542,41.442 34.309,41.442 28.004,41.577 28.807,41.567 25.643,41.599 26.446,41.589 27.227,41.592 25.995,42.162 26.793,42.162 27.549,42.185 28.294,42.209 26.386,42.671 27.189,42.661 25.608,42.687 27.915,42.692
BUCK_FLT: C110.2 J2.2 R75.1 | length 74.4
  Power1 w0.254: J2.2@81.474,16.25 81.551,16.25 81.674,16.127 v1(81.674,15.5)
  Ground2 w0.254: v1(76.997,1.812) 78.968,3.783 v1(78.968,4.539)
  Power2 w0.254: R75.1@32.712,12.999 32.575,12.862 32.268,12.862 31.174,11.768 31.174,3 32.674,1.5 76.666,1.5 v1@76.997,1.83 ; v1(78.968,4.539) 79.003,4.574 79.003,13.618 80.507,15.123 80.661,15.123 C110.2@80.794,15.256 81.429,15.256 v1(81.674,15.5)
BUCK_HI_PWM: J2.50 R11.1 | length 75.2
  Power1 w0.254: R11.1@37.7,10.239 37.756,10.183 37.756,6.917 41.174,3.5 64.674,3.5 v1(69.674,8.5) ; v1(78.176,23.331) 78.174,23.334 78.174,35 78.623,35.45 J2.50@81.474,35.45
  Ground1 w0.254: v1(69.674,8.5) 74.174,8.5 78.174,12.5 78.174,20.364 78.509,20.699 78.509,22.106 78.176,22.439 v1(78.176,23.331)
BUCK_LO_PWM: J2.52 R13.1 | length 77.7
  Power1 w0.254: R13.1@36.225,10.239 36.225,6.948 40.382,2.792 65.443,2.792 v1(72.409,9.758) ; v1(77.406,23.331) 77.406,35.732 77.923,36.25 J2.52@81.474,36.25
  Ground1 w0.254: v1(72.409,9.758) 74.034,9.758 77.561,13.285 77.561,16.983 77.174,17.371 77.174,21.85 77.406,22.082 v1(77.406,23.331)
DAC_EN: J2.75 R53.2 U11.7 | length 26.5
  Power1 w0.254: J2.75@84.874,49.05 87.898,49.05 90.674,51.826 v1(90.674,57) ; v1(91.174,60.086) 91.242,60.086 91.447,60.291 94.132,60.291 R53.2@94.174,60.25 ; R53.2@94.374,60.25 94.792,60.669 96.785,60.669 98.202,59.251 U11.7@101.601,59.251
  Power2 w0.254: v1(90.674,57) 91.174,57.5 v1(91.174,60.086)
FB: R19.1 R23.1 U5.5 | length 5.2
  Power2 w0.254: U5.5@108.639,40.718 108.639,41.568 108.794,41.723 R23.1@108.794,44.543 R19.1@110.094,44.543
GND: C32.1 C33.1 C34.1 C35.1 C36.1 C37.1 C38.1 C39.1 C40.1 C41.1 C42.1 C43.1 C47.1 C48.1 C50.2 C51.2 C52.1 C53.1 C54.2 C55.1 C56.2 C57.2 C58.2 C59.2 C62.2 C63.2 C64.2 C65.2 C66.2 C67.2 C68.2 C70.2 C72.2 C73.2 C74.2 C75.2 C76.2 C77.1 C80.1 C83.1 C88.2 C89.2 C90.2 C91.2 C92.1 C93.1 C94.1 C95.1 C96.1 C97.1 C98.1 C99.2 C100.2 C101.2 C102.2 C103.2 C104.1 C105.2 C106.2 C107.1 C108.2 C109.1 C110.1 D6.2 D8.2 D10.1 D11.2 D14.2 J2.7 J2.10 J2.19 J2.22 J2.29 J2.35 J2.38 J2.46 J2.47 J2.65 J2.83 J2.97 J2.111 J4.8 J5.1 L6.1 R1.1 R8.2 R9.2 R14.2 R15.2 R22.1 R23.2 R25.1 R43.1 R45.1 R52.1 R53.1 R54.1 R59.1 R60.1 R64.1 R65.1 R66.1 R67.1 T2.4 TP1.1 TP14.1 TP18.1 TP19.1 TP20.1 U2.15 U3.15 U4.2 U5.1 U5.9 U6.2 U6.4 U7.2 U7.3 U7.4 U8.2 U8.5 U9.4 U10.2 U10.3 U11.1 U11.12 U11.29 U11.34 U11.35 U11.38 U11.39 U11.40 U11.41 U11.49@105.174,59.5 | length 160.9
  Power1 w0.254: v1(23.179,7.368) 23.194,7.384 24.095,7.384 U7.3@24.111,7.399 ; U7.4@24.111,6.749 22.862,6.749 22.674,6.937 22.674,7.861 22.822,8.01 23.183,8.01 v1(23.198,8.024) 23.222,8.049 U7.2@24.111,8.049 ; v1(24.174,5) 24.21,4.963 C70.2@24.21,4.183 ; C66.2@28.19,8.324 C65.2@29.375,8.324 ; v1@30.758,14.573 30.741,14.556 30.741,14.25 31.269,13.722 C41.1@31.344,13.722 ; R15.2@34.313,10.719 R15.2@34.283,10.75 v1(34.283,10.233) 34.331,10.282 34.713,10.282 34.947,10.516 34.997,10.516 35.12,10.639 C35.1@35.12,10.689 C35.1@35.09,10.719 ; C33.1@38.779,10.841 38.779,10.795 39.005,10.569 39.135,10.569 v1(39.184,10.521) 39.358,10.695 39.358,10.91 39.416,10.968 R9.2@39.588,10.968 ; C36.1@40.396,39.981 C36.1@40.494,40.078 ; v1(43.596,43.097) 43.596,43.066 43.915,42.747 C34.1@43.965,42.747 ; C34.1@43.944,42.726 43.944,41.956 R14.2@43.923,41.935 43.931,41.928 44.421,41.928 v1(44.428,41.92) ; C32.1@43.965,46.86 43.965,47.546 43.89,47.621 R8.2@43.89,47.735 v1(44.409,47.735) ; v1(65.088,44.451) 65.972,44.451 C77.1@65.982,44.462 ; R25.1@66.174,25.018 66.174,25.118 v1(66.693,25.637) 66.801,25.745 67.351,25.745 U4.2@67.524,25.918 ; R43.1@67.711,41.464 67.856,41.609 68.532,41.609 ; v1(68.532,42.254) 68.532,41.609 ; U8.2@69.064,19.627 v1(69.064,18.252) U8.5@69.064,16.877 69.064,15.446 C67.2@69.137,15.373 ; C76.2@69.427,49.361 v1(69.977,49.361) 70.45,49.361 70.749,49.062 R45.1@70.749,49.012 71.762,49.012 C75.2@71.974,48.8 ; C73.2@69.479,41.49 69.36,41.609 68.532,41.609 ; U9.4@69.479,44.989 69.481,44.992 70.007,44.992 v1(70.01,44.994) ; v1(70.689,20.772) 70.713,20.796 71.475,20.796 C72.2@71.499,20.821 ; C74.2@72.379,42.345 72.388,42.354 73.077,42.354 v1(73.087,42.364) ; v1(72.664,56.046) 72.664,55.009 TP1.1@72.674,55 ; C68.2@73.164,15.326 73.189,15.301 v1(73.189,14.593) ; J2.10@81.474,19.45 82.712,19.45 83.512,18.65 J2.7@84.874,18.65 ; J2.22@81.474,24.25 81.597,24.373 82.109,24.373 82.802,25.066 v1(82.802,26.644) 82.802,27.301 82.951,27.45 J2.29@84.874,27.45 ; J2.38@81.474,30.65 82.774,30.65 v1(83.174,30.25) 83.574,29.85 J2.35@84.874,29.85 ; J2.46@81.474,33.85 82.835,33.85 v1(83.235,34.25) 83.635,34.65 J2.47@84.874,34.65 ; v1(83.832,23.092) 83.901,23.092 84.135,23.327 84.751,23.327 J2.19@84.874,23.45 ; J2.111@83.94,63.266 v1(83.97,63.297) 84,63.327 84.751,63.327 J2.111@84.874,63.45 ; J2.65@84.874,45.05 84.919,45.095 87.238,45.095 v1(87.283,45.14) ; J2.83@84.874,52.25 84.9,52.276 87.283,52.276 v1(87.309,52.302) 87.674,52.666 87.674,57.39 v1(87.336,57.727) 84.997,57.727 J2.97@84.874,57.85 ; v1(91.674,38.5) TP14.1@91.674,39.5 ; C98.1@92.674,70.875 92.924,70.625 C98.1@93.197,70.352 ; R53.1@94.174,58.75 94.297,58.627 94.716,58.627 94.818,58.525 v1(94.887,58.525) 94.917,58.555 95.615,58.555 R54.1@95.645,58.585 ; v1(96.667,51.603) 96.667,52.343 C80.1@96.674,52.35 ; C101.2@96.924,68.7 C101.2@97.174,68.7 C101.2@97.231,68.643 ; C104.1@98.67,63.4 98.676,63.406 v1(99.42,63.406) 100.164,63.406 C105.2@100.17,63.412 100.361,63.412 100.677,63.096 100.789,63.096 v1(100.837,63.048) 100.837,63.02 101.608,62.25 U11.1@101.774,62.25 102.424,62.25 v1(104.489,60.185) U11.49@105.174,59.5 v1(104.489,58.815) 102.424,56.75 U11.12@101.774,56.75 101.608,56.75 100.896,56.038 C102.2@100.045,56.038 ; R60.1@98.924,68.643 v1(98.924,67.834) 98.924,67.025 C96.1@99.174,66.775 ; v1@99.053,74.854 99.099,74.854 v1(99.174,74.929) 99.483,75.238 C88.2@99.674,75.238 ; C100.2@102.174,66.762 102.285,66.762 102.412,66.889 v1(102.412,67.695) R52.1@102.412,68.5 ; C83.1@105.174,48.85 105.236,48.787 106.611,48.787 C92.1@106.674,48.725 ; U11.41@105.924,62.9 105.924,62.325 106.057,62.191 106.625,62.191 v1(106.674,62.143) 106.722,62.191 107.29,62.191 107.424,62.325 U11.38@107.424,62.9 ; C93.1@106.674,51.85 106.68,51.844 v1(106.68,51.273) ; v1(106.974,58.815) 107.031,58.757 v1(107.879,58.757) ; v1(107.732,61.411) 108.077,61.756 108.567,61.756 U11.35@108.574,61.75 ; v1@107.886,58.75 U11.29@108.574,58.75 ; 107.961,61.25 U11.34@108.574,61.25 ; D10.1@109.674,73.485 110.174,72.985 110.174,72.691 v1@110.134,72.652 ; C95.1@110.174,60.15 110.236,60.213 111.611,60.213 C94.1@111.674,60.275 111.688,60.275 111.936,60.523 C103.2@111.936,62 ; v1(110.174,72.652) 110.174,70.5 D11.2@110.674,70 D11.2@110.902,69.772 ; C89.2@111.174,51.738 v1(111.924,51.738) C90.2@112.674,51.738 ; L6.1@112.871,69.772 113.444,69.199 L6.1@113.444,69 ; R59.1@116.674,64.238 v1(117.424,64.238) C91.2@118.174,64.238 ; C107.1@122.163,18.238 122.168,18.233 122.168,16.905 v1(122.174,16.9)
  Power1 w0.4: C41.1@31.344,13.722 C40.1@32.551,13.722 ; v1(39.87,39.99) 39.899,39.99 39.92,40.011 40.367,40.011 C36.1@40.396,39.981 ; C37.1@40.477,41.218 40.477,41.143 40.261,40.927 40.261,40.711 v1(40.24,40.69) 40.261,40.669 40.261,40.386 40.494,40.153 C36.1@40.494,40.078 ; C106.2@92.674,50.3 v1(92.674,49.4) 92.674,48.5 TP20.1@93.174,48 ; C96.1@99.174,66.75 99.174,66.775 99.349,66.95 v1@99.698,66.95 ; v1@99.699,66.951 99.86,66.951 v1(99.881,66.971) 99.901,66.951 100.149,66.951 ; 100.149,66.95 100.499,66.95 100.674,66.775 C97.1@100.674,66.75 100.686,66.762 C100.2@102.174,66.762 ; C100.2@102.285,66.762 C99.2@103.674,66.762 ; D11.2@110.902,69.772 L6.1@112.871,69.772 ; TP19.1@118.674,55 v1(118.674,56.25) D14.2@118.674,58
  Power1 w0.6: C101.2@97.231,68.643 97.422,68.452 v1(98.311,68.452) ; v1@98.322,68.463 98.743,68.463 R60.1@98.924,68.643
  Power1 w0.8: C98.1@92.924,70.625 v1(94.999,70.625) C101.2@96.924,68.7
  Power2 w0.254: R65.1@30.718,15.339 30.736,15.321 30.736,14.411 v1(30.753,14.394) ; R65.1@30.727,15.347 R67.1@30.727,16.235 ; v1(33.437,10.984) 33.437,11.026 33.763,11.351 C43.1@34.519,11.351 ; v1(34.587,13.956) 34.611,13.98 34.611,14.562 U3.15@34.613,14.564 ; R66.1@38.164,39.956 R66.1@38.169,39.96 ; R64.1@39.062,39.96 R64.1@39.066,39.965 R64.1@39.079,39.978 ; U2.15@39.728,43.56 39.73,43.558 40.315,43.558 v1(40.355,43.518) ; v1@39.857,39.978 v1(39.87,39.99) ; C38.1@43.107,43.195 43.107,43.19 43.152,43.145 43.548,43.145 v1(43.596,43.097) ; R1.1@65.755,35.419 R1.1@65.782,35.446 ; C109.1@77.555,55.04 77.555,55.559 v1(77.557,55.56) ; v1(80.755,13.917) 80.775,13.936 80.775,14.436 C110.1@80.794,14.456 ; C108.2@90.374,23.75 v1(90.374,24.65) ; v1(91.674,38.5) 91.674,38.484 92.382,37.775 C64.2@92.382,37.75 v1(93.238,37.75) 93.852,37.136 94.208,37.136 U6.2@94.381,36.963 ; v1(105.859,61.3) 105.859,61.314 106.674,62.129 v1(106.674,62.143) ; R22.1@106.3,34.499 106.307,34.492 v1(106.307,33.927) ; C56.2@106.642,43.109 106.742,43.109 106.915,43.282 106.915,43.965 107.494,44.543 R23.2@107.594,44.543 R23.2@107.674,44.623 ; v1(106.974,58.815) 107.002,58.786 107.85,58.786 v1(107.879,58.757) ; v1(106.974,60.185) 107.021,60.232 107.021,60.7 v1(107.732,61.411) ; U5.1@112.449,34.968 U5.1@112.482,34.935 ; C55.1@112.482,33.254 C55.1@112.515,33.221 ; U10.2@121.539,16.9 v1(122.174,16.9) U10.3@122.809,16.9
  Power2 w0.35: C39.1@43.107,42.495 C38.1@43.107,43.19
  Power2 w0.4: R66.1@38.169,39.96 R64.1@39.062,39.96 ; R64.1@39.079,39.978 v1@39.857,39.978 ; R1.1@65.782,35.446 v1(66.566,35.446) ; C57.2@110.298,46.759 C58.2@110.298,48.759 ; v1(111.924,51.738) 111.924,51.325 112.588,50.661 114.428,50.661 C59.2@114.444,50.677
  Power2 w0.6: C55.1@112.482,33.254 v1(112.482,33.701) U5.1@112.482,34.935 ; v1(113.604,30.264) 114.939,30.264 C52.1@114.966,30.291 ; C53.1@114.98,38.276 116.648,38.276 v1(116.665,38.259)
  other v1: 28.799,8.314 69.066,16.014 83.112,19.05 72.674,26 74.174,26 72.174,31.5 109.244,37.193 110.544,37.193 111.844,37.193 73.735,37.514 74.599,37.546 101.462,38.4 109.244,38.493 110.544,38.493 111.844,38.493 98.109,38.813 98.977,38.815 106.974,44.024 110.314,47.681 105.908,48.787 71.323,49.014 101.056,56.2 104.489,57.7 105.859,57.7 103.374,58.815 105.859,58.815 103.374,60.185 105.859,60.185 110.892,60.224 111.942,61.114 104.489,61.3 112.204,69.758 102.174,79.143
Input_I: C72.1 J2.14 R32.2 TP17.1 | length 12.9
  Power1 w0.254: R32.2@72.703,19.432 72.703,20.817 C72.1@72.699,20.821 72.867,20.653 77.925,20.653 78.321,21.05 J2.14@81.474,21.05 ; R32.2@72.769,19.425 72.923,19.271 73.955,19.271 TP17.1@74.853,18.374
Input_V: C74.1 J2.12 R42.2 | length 32.4
  Power1 w0.254: R42.2@71.054,43.787 71.054,42.47 C74.1@71.179,42.345 71.179,41.505 71.664,41.019 75.654,41.019 76.517,40.156 76.517,21.66 76.868,21.309 v1(77.755,21.309) ; v1(78.991,20.055) 79.059,20.055 79.131,20.127 81.351,20.127 J2.12@81.474,20.25
  Power2 w0.254: v1(77.755,21.309) 77.755,21.3 78.991,20.064 v1(78.991,20.055)
INT: J2.79 R55.2 U11.9 | length 27.5
  Power1 w0.254: J2.79@84.874,50.65 84.997,50.773 88.058,50.773 88.674,51.388 88.674,57.307 89.04,57.673 91.964,57.673 92.094,57.803 R55.2@92.16,57.737 92.35,57.737 92.477,57.61 92.477,57.42 93.174,56.723 93.174,55.211 93.322,55.062 96.444,55.062 96.674,55.292 96.674,56.506 98.417,58.25 U11.9@101.774,58.25
ISO1_5V: C31.1 C44.2 C79.1 D2.1 D4.1 pad.2 R3.1 R16.2 | length 53.3
  Power1 w0.254: D2.1@41.194,15.304 D2.1@41.346,15.304 ; D4.1@55.536,33.365 D4.1@55.536,33.518
  Power1 w0.4: v1(39.986,14.374) 40.007,14.394 40.131,14.394 41.041,15.304 D2.1@41.194,15.304
  Power1 w0.6: D2.1@41.346,15.304 43.747,12.904 43.747,12.58 43.747,8.88 44.102,8.524 55.145,8.524 58.72,12.099 58.72,13.033 60.876,15.19 v1(60.876,16.828) ; D4.1@55.536,33.365 55.536,31.357 54.674,30.494 54.674,28.5 60.818,22.355 v1(60.836,22.355)
  Ground1 w0.6: v1(60.836,22.355) v1@60.856,22.335
  Power2 w0.4: C79.1@39.208,13.569 C31.1@39.208,14.364 ; C31.1@39.252,14.502 39.296,14.547 39.296,15.275 R3.1@39.39,15.369 ; C31.1@39.39,14.364 39.976,14.364 v1(39.986,14.374)
  Power2 w0.6: v1@60.856,22.335 60.856,16.848 v1(60.876,16.828)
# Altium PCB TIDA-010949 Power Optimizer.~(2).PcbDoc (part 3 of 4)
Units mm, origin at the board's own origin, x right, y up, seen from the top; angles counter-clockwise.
Board outline 129.4 x 84 mm, 4 copper layers (Power1, Ground1, Ground2, Power2), stack 1.926 mm thick; 262 components, 129 nets, 791 pads, 1191 vias.

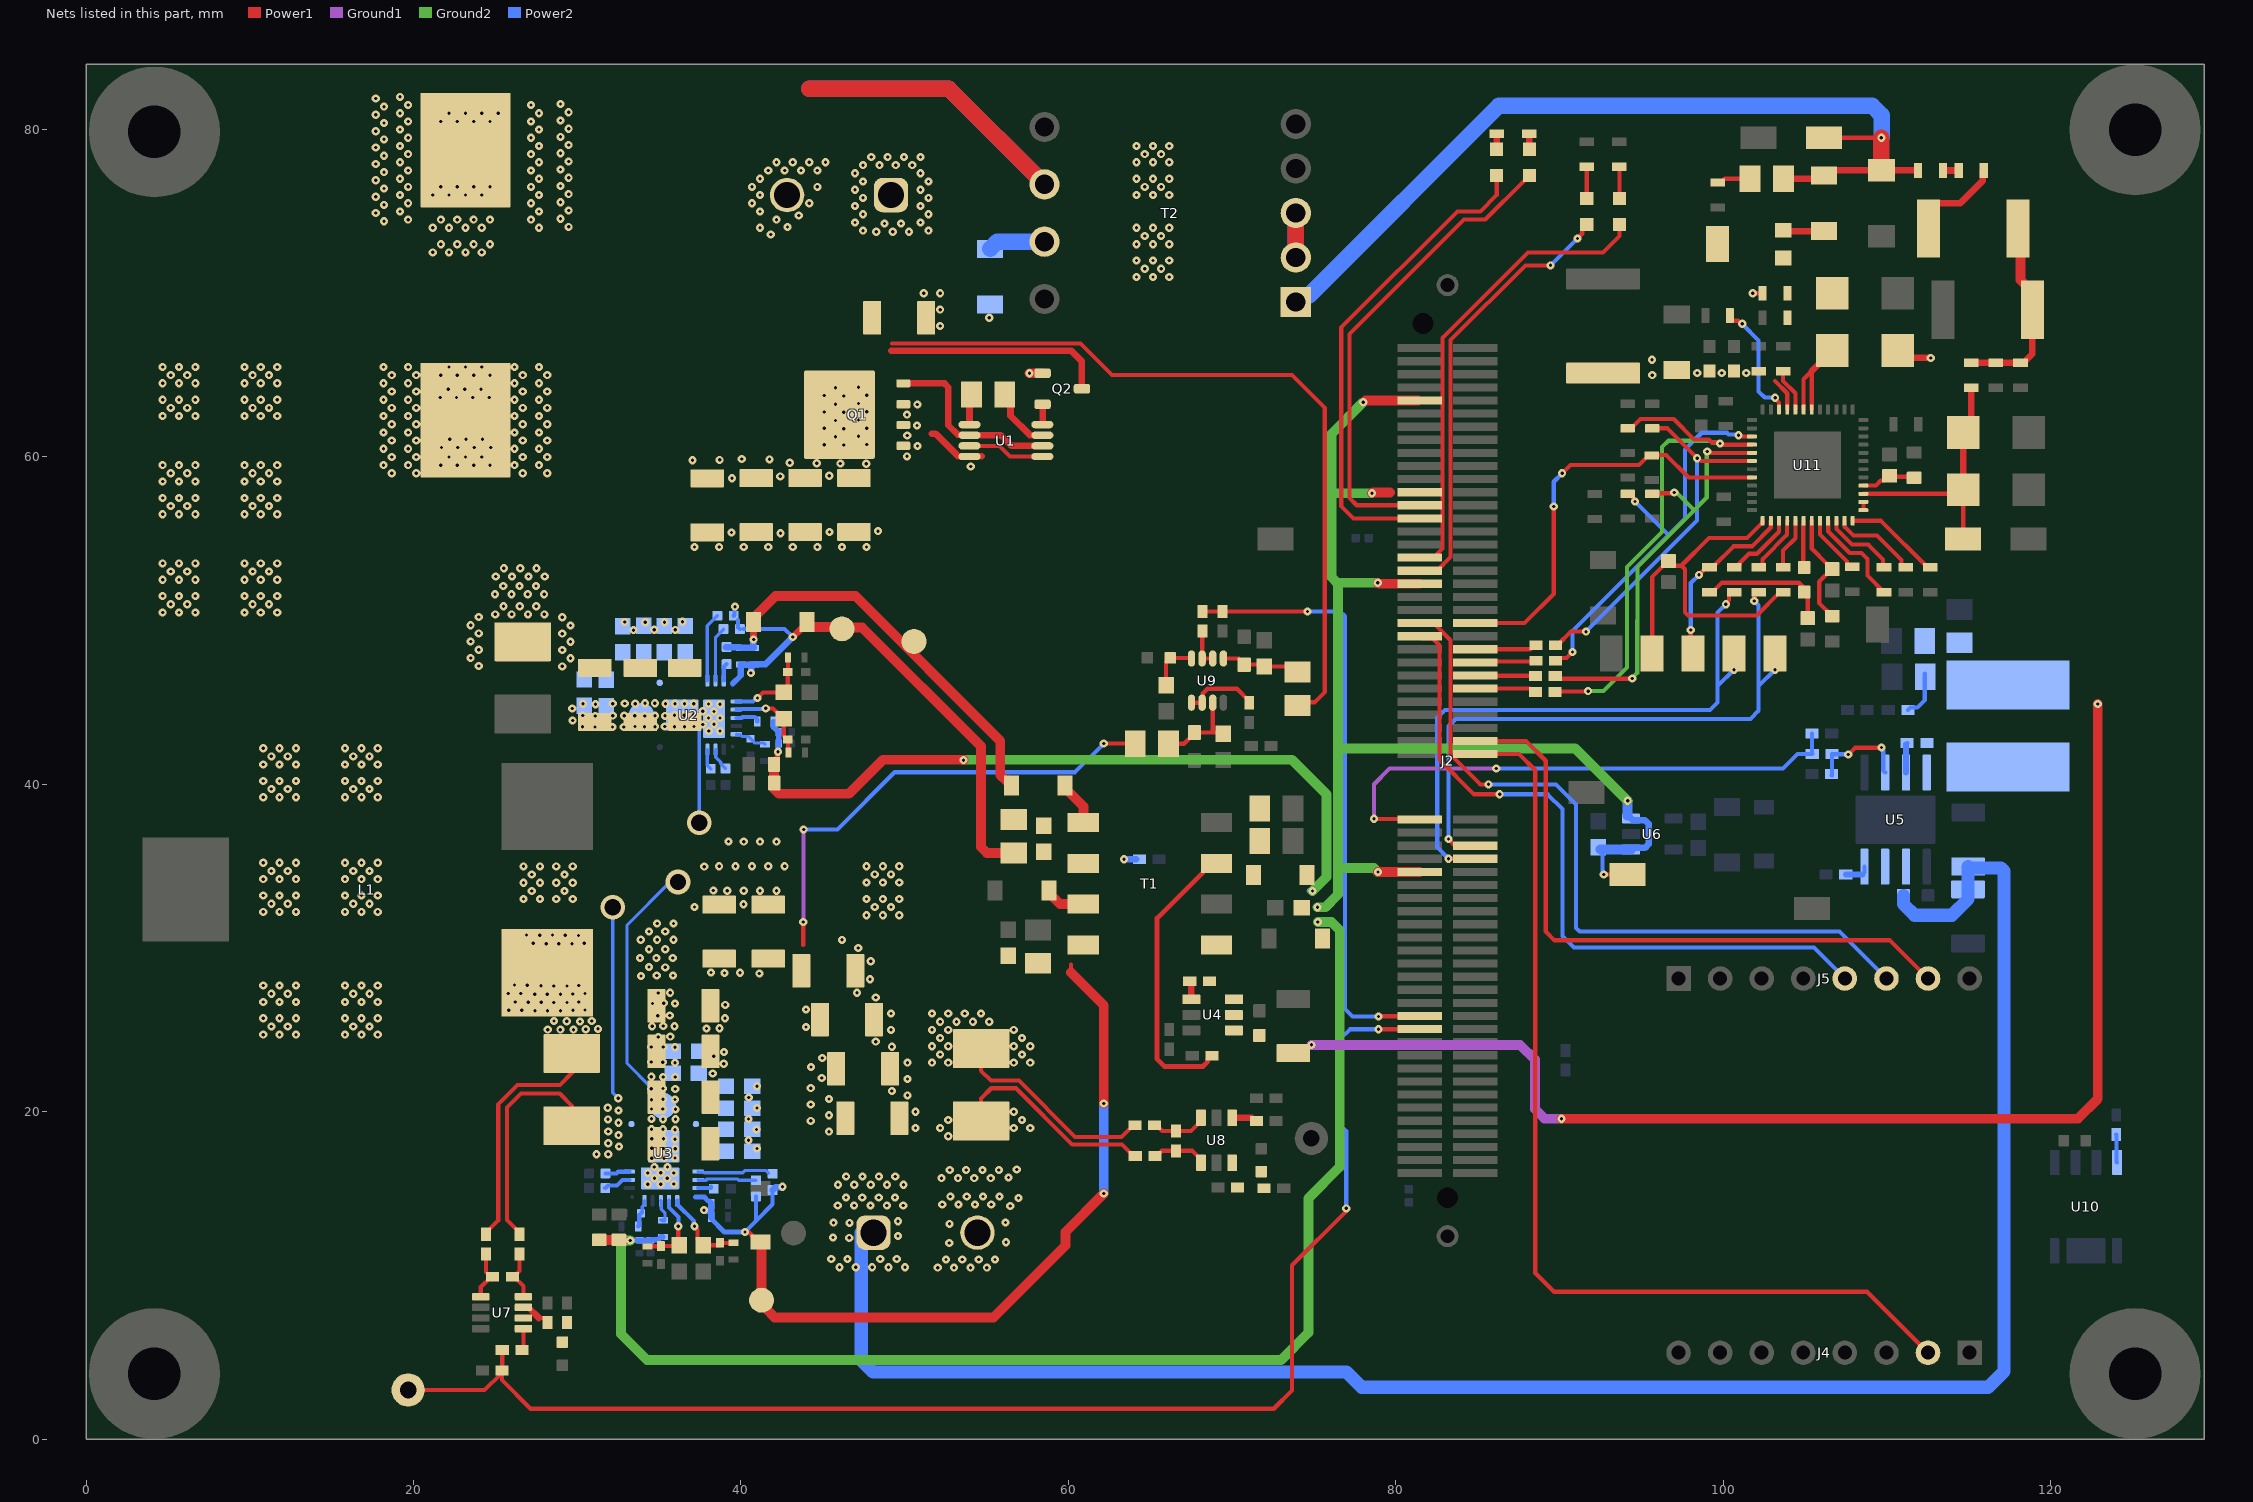
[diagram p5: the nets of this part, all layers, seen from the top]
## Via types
v1: diameter 0.5, hole 0.2, Power1 to Power2, tented both sides, 1183 vias
v2: diameter 1.5, hole 1, Power1 to Power2, 4 vias
v3: diameter 3.508, hole 3.1, Power1 to Power2, tented both sides, 4 vias

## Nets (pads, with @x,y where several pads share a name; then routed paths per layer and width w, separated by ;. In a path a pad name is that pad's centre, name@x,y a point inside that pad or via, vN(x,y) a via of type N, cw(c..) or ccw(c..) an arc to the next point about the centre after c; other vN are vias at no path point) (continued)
ISO1_GND: C31.2 C44.1 C79.2 D2.2 pad.3 R16.1 R69.1 R71.1 T1.5 U3.11 | length 55.1
  Power1 w0.254: 60.174,28.5 60.174,29
  Power1 w0.3: v1@40.246,12.626 40.258,12.614 40.514,12.614 40.734,12.395 40.734,12.337 41.041,12.029 D2.2@41.194,12.029
  Power1 w0.6: D2.2@41.194,12.029 41.255,11.968 pad.3@41.255,8.498 ; pad.3@41.267,8.486 41.267,8.236 41.868,7.635 41.868,7.621 42.054,7.436 55.436,7.436 59.825,11.825 59.825,12.655 v1@62.17,15 ; 60.174,28.5 62.174,26.5 v1(62.174,20.5)
  Power2 w0.254: v1(37.749,13.987) v1@37.775,14.014 ; C31.2@38.015,14.541 38.129,14.541 38.192,14.478 C31.2@38.192,14.364 ; C79.2@38.192,13.455 C79.2@38.192,13.569 ; v1(40.246,12.654) 40.926,13.334 ; R71.1@40.926,14.816 40.926,13.334 ; R69.1@41.946,15.205 R69.1@41.937,15.214 41.937,14.345 40.926,13.334
  Power2 w0.3: U3.11@37.213,14.789 37.767,14.789 C31.2@38.015,14.541 ; C79.2@38.192,13.455 38.994,12.654 v1(40.246,12.654)
  Power2 w0.4: v1@37.775,13.961 38.192,13.961 ; C79.2@38.192,13.569 38.192,13.961 ; C31.2@38.192,14.364 38.192,13.961 ; R69.1@41.946,15.205 41.946,15.222 42.121,15.398 42.518,15.398 v1(42.539,15.418)
  Power2 w0.6: v1(62.174,15) v1(62.174,20.5)
ISO2_5V: C30.1 C45.2 C78.1 D1.1 D3.1 pad.5 R4.1 R17.2 | length 26.1
  Power1 w0.4: D3.1@40.728,49.914 40.771,49.871 40.771,48.853 v1(40.781,48.843)
  Power1 w0.6: D3.1@40.761,49.904 40.919,50.061 40.919,50.309 42.11,51.5 47,51.5 55.845,42.655 55.845,40.579 56.197,40.228 56.379,40.228 56.536,40.07 D1.1@56.536,39.918
  Power2 w0.254: R4.1@39.131,48.393 R4.1@39.16,48.365 ; C30.1@39.972,48.364 C30.1@40.001,48.335 ; C78.1@40.722,48.399 40.786,48.335 C78.1@40.794,48.335
  Power2 w0.4: R4.1@39.079,48.364 C30.1@39.972,48.364 ; C30.1@40.001,48.335 C78.1@40.786,48.335 ; C78.1@40.722,48.399 40.76,48.437 40.76,48.823 v1(40.781,48.843)
ISO2_GND: C30.2 C45.1 C78.2 D3.2 pad.4 R17.1 R68.1 R70.1 T1.7 U2.11 | length 33.6
  Power1 w0.4: v1(43.174,49) 43.667,49.494 43.779,49.494 D3.2@44.036,49.751
  Power1 w0.6: D3.2@44.036,49.904 44.036,49.777 44.194,49.62 46.174,49.62 46.205,49.588 47.412,49.588 54.674,42.326 54.674,36.164 55.025,35.813 C45.1@56.675,35.813
  Power2 w0.254: R68.1@39.568,50.297 39.606,50.334 39.606,50.818 v1(39.643,50.855) ; R68.1@39.833,50.032 39.833,49.592 R70.1@39.942,49.483 ; R70.1@40.174,49.5 42.674,49.5 v1(43.174,49) ; v1(40.611,46.802) v1@40.66,46.85 ; C78.2@40.794,47.319 C78.2@40.81,47.335
  Power2 w0.35: U2.11@39.503,46.16 40.001,46.658
  Power2 w0.4: 40.001,46.658 C30.2@40.001,47.319 C78.2@40.794,47.319 40.741,47.319 40.731,47.31 40.731,47.256 40.632,47.157 40.632,46.834 v1@40.605,46.808 ; C78.2@40.81,47.335 41.509,47.335 v1(43.174,49)
LED1_EN: D15.1 J2.86 | length 26.9
  Power1 w0.254: J2.86@81.485,53.061 J2.86@81.474,53.05 82.518,53.05 83.36,53.892 83.36,67.14 87.925,71.705 v1(89.468,71.705) ; v1(91.113,73.35) 91.403,73.64 91.403,73.929 D15.1@91.674,74.2
  Power2 w0.254: v1(89.468,71.705) v1(91.113,73.35) v1@91.124,73.35
LED2_EN: D16.1 J2.88 | length 28.6
  Power1 w0.254: J2.88@81.485,53.862 82.319,53.862 82.858,54.401 82.858,67.28 88.078,72.5 92.674,72.5 93.674,73.5 D16.1@93.674,74.2
NetC1_1: C1.1 U1.7 | length 3.9
  Power1 w0.4: C1.1@56.125,63.825 56.473,63.476 56.473,62.52 57.657,61.337 58.407,61.337 U1.7@58.417,61.327
NetC1_2: C1.2 U1.1 | length 1.9
  Power1 w0.254: C1.2@53.967,63.699 C1.2@54.093,63.825
  Power1 w0.4: U1.1@53.967,61.977 C1.2@53.967,63.699
NetC32_2: C32.2 R8.1 R10.2 U2.12 | length 5.3
  Power1 w0.254: v1(41.019,45.268) 41.36,45.61 42.59,45.61 R10.2@42.615,45.635 42.865,45.885 C32.2@42.865,46.86 42.87,46.865 42.87,47.731 R8.1@42.874,47.735
  Power2 w0.254: U2.12@39.728,45.06 40.742,45.06 40.95,45.268 v1(41.019,45.268)
NetC33_2: C33.2 R9.1 R11.2 U3.12 | length 5.3
  Power1 w0.254: v1(37.174,13) 37.352,12.821 37.352,12.187 R11.2@37.7,11.839 38.723,11.839 38.723,11.862 38.85,11.99 R9.1@39.536,11.99
  Power2 w0.254: U3.12@36.113,14.564 36.113,14.343 37.125,13.331 37.125,13.049 v1(37.174,13)
NetC34_2: C34.2 R12.2 R14.1 U2.13 | length 5.4
  Power1 w0.254: v1(41.524,44.643) 41.972,44.643 42.242,44.373 42.242,44.358 42.59,44.01 R12.2@42.615,44.01 42.615,42.947 42.815,42.747 C34.2@42.865,42.747 42.886,42.726 42.886,41.956 R14.1@42.907,41.935
  Power2 w0.254: U2.13@39.728,44.56 39.949,44.56 39.995,44.606 41.487,44.606 v1(41.524,44.643)
NetC35_2: C35.2 R13.2 R15.1 U3.13 | length 5
  Power1 w0.254: R15.1@34.283,11.766 34.294,11.777 35.109,11.777 C35.2@35.12,11.789 36.175,11.789 R13.2@36.225,11.839 36.174,11.89 v1(36.174,13)
  Power2 w0.254: U3.13@35.613,14.564 35.615,14.562 35.615,14.146 36.195,13.566 36.195,13.021 v1(36.174,13)
NetC46_1: C46.1 T1.4 U4.6
NetC46_2: C46.2 U4.1 | length 1.1
  Power1 w0.254: C46.2@67.424,27.968 C46.2@67.524,27.868
  Power1 w0.4: U4.1@67.524,26.868 C46.2@67.524,27.868
NetC49_1: C49.1 L2.1 U5.8
NetC49_2: C49.2 U5.7 | length 1.8
  Power2 w0.254: C49.2@111.179,42.442 C49.2@111.253,42.517
  Power2 w0.35: U5.7@111.179,40.718 C49.2@111.179,42.442
NetC50_1: C50.1 C51.1 D5.2 R20.2 T1.2 | length 17.6
  Power1 w0.254: T1.2@68.782,35.174 T1.2@69.053,35.174
  Power1 w0.3: R20.2@68.774,23.418 68.674,23.418 68.524,23.268 68.524,23.06 68.231,22.768 65.873,22.768 65.434,23.206 65.434,31.826 68.248,34.639 68.248,34.739 68.683,35.174 T1.2@68.782,35.174
NetC65_1: C65.1 C66.1 FB1.2 U7.6 U7.7 | length 1.9
  Power1 w0.254: U7.7@26.711,8.049 U7.7@27.011,8.049 ; 27.663,7.397 28.017,7.397 28.19,7.224 C66.1@28.19,7.124
  Power1 w0.4: U7.7@27.011,8.049 27.663,7.397
NetC67_1: C67.1 C68.1 FB2.2 U8.6
NetC69_1: C69.1 R33.2 U7.8 | length 3.1
  Power1 w0.254: C69.1@26.039,9.914 C69.1@26.139,9.914 ; R33.2@26.485,11.314 26.485,10.26 C69.1@26.139,9.914 ; U7.8@26.711,8.699 26.711,9.342 C69.1@26.139,9.914
NetC69_2: C69.2 R36.2 U7.1 | length 3.1
  Power1 w0.254: U7.1@24.111,8.699 24.111,9.285 C69.2@24.739,9.914 ; R36.2@24.439,11.314 24.439,10.214 C69.2@24.739,9.914 ; C69.2@24.839,9.914 C69.2@24.739,9.914
NetC71_1: C71.1 R34.2 U8.3 | length 3.4
  Power1 w0.254: R34.2@65.279,19.178 65.379,19.178 65.745,18.813 C71.1@66.584,18.813 67.499,18.813 68.114,19.427 U8.3@68.114,19.627
NetC71_2: C71.2 R37.2 U8.4 | length 3.4
  Power1 w0.254: R37.2@65.294,17.293 65.394,17.293 65.714,17.613 C71.2@66.584,17.613 67.579,17.613 68.114,17.077 U8.4@68.114,16.877
NetC73_1: C73.1 R40.1 R43.2 U9.3 | length 5.5
  Power1 w0.254: R40.1@66.129,42.48 67.077,42.48 67.711,43.114 R43.2@67.711,43.164 68.754,43.164 ; U9.3@68.829,44.989 68.829,43.239 68.754,43.164 ; C73.1@69.479,43.09 69.405,43.164 68.754,43.164
NetC75_1: C75.1 R41.1 R45.2 U9.5 | length 4.9
  Power1 w0.254: U9.5@69.479,47.689 70.422,47.689 70.749,47.362 R45.2@70.749,47.312 71.862,47.312 C75.1@71.974,47.2 73.659,47.2 R41.1@74.004,46.855
NetC77_2: C77.2 FB3.2 U9.8 | length 3.1
  Power1 w0.254: C77.2@65.982,46.062 65.982,47.482 66.116,47.615 FB3.2@66.316,47.615 ; FB3.2@66.232,47.731 66.253,47.71 67.507,47.71 U9.8@67.529,47.689
NetC81_1: C81.1 D10.2 R56.2 R58.2 T2.1 TP26.1 | length 56.3
  Power1 w0.254: C81.1@105.974,77 C81.1@106.174,77.2 C81.1@106.489,77.515 ; TP26.1@106.174,79.5 v1(109.674,79.5) ; R58.2@111.897,77.515 R58.2@111.912,77.5
  Power1 w0.4: R56.2@103.69,77 C81.1@105.974,77 ; C81.1@106.489,77.515 D10.2@109.674,77.515 110.174,77.515 R58.2@111.897,77.515
  Power1 w1: D10.2@109.674,77.515 v1(109.674,79.5)
  Power2 w1: T2.1@73.902,69.463 74.327,69.888 74.735,69.888 86.298,81.451 109.112,81.451 109.698,80.865 v1@109.698,79.525
NetC81_2: C81.2 L3.2 | length 2.5
  Power1 w0.254: L3.2@103.674,73.85 L3.2@103.724,73.8
  Power1 w0.4: L3.2@103.724,73.8 C81.2@106.174,73.8
NetC82_2: C82.2 C83.2 R51.1 | length 8.1
  Power1 w0.254: R51.1@99.174,51.738 99.364,51.738 99.945,52.319 104.63,52.319 105.174,51.775 105.174,51.75 C83.2@105.174,50.15
NetC84_2: C84.2 T2.8 | length 3.5
  Power2 w1: C84.2@55.229,72.72 55.652,73.143 58.541,73.143 T2.8@58.552,73.153
NetC85_1: C85.1 U11.22 | length 4.6
  Power1 w0.254: U11.22@106.924,56.1 106.931,56.093 106.931,55.598 107.876,54.652 108.869,54.652 109.778,53.743 109.778,53.316 C85.1@109.837,53.257
NetC85_2: C85.2 U11.21 | length 6.2
  Power1 w0.254: U11.21@106.424,56.1 106.431,56.093 106.431,55.456 107.744,54.143 108.454,54.143 108.821,53.776 108.821,52.749 C85.2@109.837,51.733
NetC86_1: C86.1 C91.1 L5.1 L6.2 R59.2 | length 12.1
  Power1 w0.254: C91.1@118.174,65.762 C91.1@118.364,65.762
  Power1 w0.4: C86.1@115.174,65.762 R59.2@116.674,65.762 C91.1@118.174,65.762 ; C91.1@118.364,65.762 118.904,66.302 L6.2@118.904,69
  Power1 w0.6: L5.1@118.174,74.108 118.174,70.81 118.904,70.08 L6.2@118.904,69
NetC86_2: C86.2 D13.2 D14.1 TP28.1 U11.27 | length 15.6
  Power1 w0.254: U11.27@108.574,57.75 114.424,57.75 D14.1@114.674,58 TP28.1@114.674,55 ; D13.2@114.674,61.5 D13.2@115.174,62
  Power1 w0.4: D14.1@114.674,58 D13.2@114.674,61.5 ; D13.2@115.174,62 C86.2@115.174,64.238
NetC87_1: C87.1 R58.1 | length 1
  Power1 w0.4: R58.1@113.436,77.5 C87.1@114.412,77.5
NetC87_2: C87.2 L5.2 | length 5.7
  Power1 w0.4: L5.2@112.674,74.643 112.674,75.122 113.061,75.51 114.501,75.51 115.882,76.89 115.882,77.446 C87.2@115.936,77.5
  Power1 w0.6: L5.2@112.561,73.961 L5.2@112.561,74.643
NetC88_1: C88.1 R56.1 | length 2.1
  Power1 w0.254: C88.1@99.674,76.762 99.864,76.762 100.102,77 R56.1@101.658,77
NetC89_1: C89.1 U11.23 | length 5.3
  Power1 w0.254: U11.23@107.424,56.1 107.431,56.093 107.431,55.74 107.962,55.208 109.399,55.208 110.895,53.713 110.895,53.389 111.022,53.262 C89.1@111.174,53.262
NetC90_1: C90.1 U11.24 | length 5.9
  Power1 w0.254: U11.24@107.924,56.1 109.645,56.1 112.483,53.262 C90.1@112.674,53.262
NetC92_2: C92.2 C93.2 U11.19 | length 7
  Power1 w0.254: U11.19@105.424,56.1 105.424,54.4 106.351,53.473 106.351,53.448 C93.2@106.649,53.15 ; C92.2@106.674,50.275 105.876,51.073 105.876,52.377 C93.2@106.649,53.15 ; C93.2@106.674,53.15 C93.2@106.649,53.15
NetC94_2: C94.2 C95.2 U11.28 | length 3.4
  Power1 w0.254: U11.28@108.574,58.25 108.581,58.257 109.341,58.257 109.636,58.552 109.876,58.552 C95.2@110.174,58.85 110.236,58.787 111.611,58.787 C94.2@111.674,58.725
NetD1_2: D1.2 T1.8 | length 2.7
  Power1 w0.254: D1.2@59.811,39.765 D1.2@59.811,39.918
  Power1 w0.6: D1.2@59.811,39.765 60.923,38.654 T1.8@60.923,37.664
NetD4_2: D4.2 T1.6 | length 2.5
  Power1 w0.6: D4.2@58.811,33.518 58.811,33.365 59.493,32.684 T1.6@60.923,32.684
NetD7_1: D7.1 J2.94 | length 30.1
  Power1 w0.254: J2.94@81.474,56.25 77.424,56.25 76.674,57 76.674,67.9 83.774,75 85.174,75 86.174,76 D7.1@86.174,77.2
NetD7_2: D7.2 R29.1 | length 0.9
  Power1 w0.4: D7.2@86.174,78.8 R29.1@86.174,79.738
NetD9_2: D9.2 D11.1 L3.1 R50.1 R52.2 TP25.1 U11.42 U11.43 | length 6.7
  Power1 w0.254: U11.43@104.924,62.9 104.924,64.75 105.424,65.25 U11.42@105.424,62.9
  Power1 w0.4: 105.424,65.25 D9.2@106.674,66.5
NetD12_1: D12.1 J2.96 | length 29.5
  Power1 w0.254: J2.96@81.474,57.05 77.624,57.05 77.174,57.5 77.174,67.5 84.174,74.5 85.474,74.5 87.901,76.927 D12.1@88.174,77.2
NetD12_2: D12.2 R76.1 | length 0.9
  Power1 w0.4: D12.2@88.174,78.8 R76.1@88.174,79.738
NetD15_2: D15.2 R61.1 | length 1.9
  Power1 w0.254: D15.2@91.674,75.8 R61.1@91.674,77.738
NetD16_2: D16.2 R62.1 | length 1.9
  Power1 w0.254: D16.2@93.674,75.8 R62.1@93.674,77.738
NetJ2_67: J2.67 R24.2 | length 3.7
  Power1 w0.254: J2.67@84.874,45.85 88.22,45.85 88.434,45.636 R24.2@88.534,45.636
NetJ2_69: J2.69 R26.2 | length 3.7
  Power1 w0.254: J2.69@84.874,46.65 84.889,46.635 88.534,46.635 R26.2@88.549,46.619
NetJ2_71: J2.71 R27.2 | length 3.7
  Power1 w0.254: J2.71@84.874,47.45 84.924,47.501 88.519,47.501 R27.2@88.57,47.552
NetJ2_73: J2.73 R28.2 | length 3.8
  Power1 w0.254: J2.73@84.874,48.25 88.223,48.25 88.474,48.5 R28.2@88.574,48.5
NetQ1_4: Q1.4 U1.2 U1.6 | length 11.4
  Power1 w0.4: Q1.4@49.923,64.492 52.439,64.492 52.674,64.257 52.674,61.936 53.258,61.352 53.478,61.352 53.494,61.337 53.957,61.337 U1.2@53.967,61.327 55.885,61.327 56.535,60.677 U1.6@58.417,60.677
NetQ2_2: Q2.2 U1.8 | length 1.2
  Power1 w0.4: U1.8@58.417,61.977 58.434,61.994 Q2.2@58.434,63.218
NetR3_2: R3.2 U3.10 | length 0.9
  Power2 w0.254: U3.10@37.388,15.339 38.171,15.339 38.175,15.343 R3.2@38.175,15.439
NetR4_2: R4.2 U2.10 | length 1.1
  Power2 w0.254: U2.10@38.953,46.335 38.953,47.165 R4.2@39.131,47.343
NetR5_2: R5.2 U2.14 | length 1.5
  Power2 w0.254: U2.14@39.728,44.06 39.73,44.062 40.056,44.062 40.103,44.109 40.847,44.109 40.999,43.957 R5.2@40.999,43.843
NetR7_2: R7.2 U3.14 | length 1.6
  Power2 w0.2: R7.2@35.085,13.388 35.289,13.388 35.358,13.457 35.358,13.827 35.132,14.053 35.132,14.544 U3.14@35.113,14.564
  Power2 w0.254: R7.2@35.229,13.367 R7.2@35.344,13.367
NetR18_1: R18.1 R21.1 U5.6 | length 6.1
  Power1 w0.254: v1(107.655,41.827) 108.059,42.232 v1@109.675,42.232
  Power2 w0.254: R21.1@106.644,40.543 106.651,40.55 R18.1@106.651,41.847 106.661,41.837 107.645,41.837 v1(107.655,41.827) ; v1(109.689,42.245) 109.689,42.176 109.786,42.079 109.786,40.841 U5.6@109.909,40.718
NetR22_2: R22.2 U5.4 | length 1.5
  Power2 w0.254: U5.4@108.516,34.499 108.639,34.622 U5.4@108.639,34.968
  Power2 w0.35: R22.2@107.5,34.499 U5.4@108.516,34.499
NetR30_1: R30.1 U11.15 | length 4.4
  Power1 w0.254: R30.1@100.674,53.262 100.864,53.262 100.991,53.389 100.991,53.484 101.594,54.088 102.07,54.088 103.417,55.434 103.417,56.093 U11.15@103.424,56.1
NetR31_1: R31.1 U7.5 | length 1.3
  Power1 w0.254: R31.1@26.624,5.443 26.711,5.53 U7.5@26.711,6.749
NetR32_1: R32.1 U8.1 | length 1.6
  Power1 w0.4: U8.1@70.014,19.627 71.208,19.627 71.403,19.432 R32.1@71.503,19.432
NetR38_1: R38.1 U11.16 | length 3.6
  Power1 w0.254: R38.1@102.174,53.262 102.285,53.262 102.412,53.389 102.412,53.748 103.917,55.252 103.917,56.093 U11.16@103.924,56.1
NetR39_1: R39.1 U11.17 | length 3.1
  Power1 w0.254: R39.1@103.674,53.262 103.674,54.283 104.424,55.033 U11.17@104.424,56.1
NetR42_1: R42.1 U9.1 U9.2 | length 4.6
  Power1 w0.254: U9.1@67.529,44.989 U9.2@68.179,44.989 68.216,45.026 68.216,45.552 68.504,45.839 70.302,45.839 71.054,45.087 R42.1@71.054,44.987
NetR44_1: R44.1 U9.6 U9.7 | length 2.3
  Power1 w0.254: R44.1@68.204,49.36 68.191,49.348 68.191,47.701 U9.7@68.179,47.689 U9.6@68.829,47.689
NetR57_1: R57.1 U11.20 | length 3.7
  Power1 w0.254: U11.20@105.924,56.1 105.924,55.268 107.583,53.609 107.583,53.418 107.71,53.291 R57.1@107.9,53.291
NetR60_2: R60.2 U11.46 | length 7.6
  Power1 w0.254: R60.2@100.424,68.643 100.424,68.443 100.547,68.32 100.928,68.32 101.105,68.143 v1(101.174,68.143) ; v1(103.186,63.616) 103.186,63.547 103.417,63.316 103.417,62.907 U11.46@103.424,62.9
  Power2 w0.254: v1(101.174,68.143) 101.174,68.111 102.174,67.111 102.174,64 102.551,63.623 103.179,63.623 v1(103.186,63.616)
NetR63_2: R63.2 U10.4 | length 1.7
  Power2 w0.254: R63.2@124.02,18.611 124.049,18.582 124.049,16.929 U10.4@124.079,16.9
NetR64_2: R64.2 U2.3 | length 1.4
  Power2 w0.2: U2.3@38.453,42.135 38.47,42.117 38.47,41.644 38.764,41.35 38.764,41.267 R64.2@39.066,40.965
NetR65_2: R65.2 U3.3 | length 1.7
  Power2 w0.254: R65.2@31.718,15.339 31.88,15.5 32.441,15.5 32.778,15.837 33.186,15.837 U3.3@33.188,15.839
NetR66_2: R66.2 U2.4 | length 1.3
  Power2 w0.2: U2.4@37.953,42.135 37.953,41.168 R66.2@38.164,40.956
NetR67_2: R67.2 U3.4 | length 1.5
  Power2 w0.254: R67.2@31.727,16.235 32.408,16.235 32.509,16.337 33.186,16.337 U3.4@33.188,16.339
NetR68_2: R68.2 U2.8 | length 4.2
  Power2 w0.2: U2.8@37.953,46.335 37.953,49.681 R68.2@38.568,50.297
NetR69_2: R69.2 U3.8 | length 4.5
  Power2 w0.2: U3.8@37.388,16.339 37.413,16.314 37.713,16.314 37.755,16.272 40.112,16.272 40.255,16.416 41.51,16.416 R69.2@41.694,16.231
NetR70_2: R70.2 U2.9 | length 3.4
  Power2 w0.2: U2.9@38.453,46.335 38.453,48.994 R70.2@38.942,49.483
NetR71_2: R71.2 U3.9 | length 3.6
  Power2 w0.2: U3.9@37.388,15.839 37.407,15.819 37.877,15.819 37.95,15.892 39.789,15.892 39.873,15.808 R71.2@40.918,15.808
NetR72_1: R72.1 R73.2 U2.16 | length 2
  Power2 w0.2: U2.16@39.728,43.06 39.753,43.035 39.978,43.035 40.093,42.919 40.468,42.919 40.743,42.644 40.743,42.638 40.86,42.521 41.395,42.521 R73.2@41.474,42.443
NetR74_1: R74.1 R75.2 U3.16 | length 1.7
  Power2 w0.2: R74.1@33.975,13.832 33.975,14.201 34.113,14.339 U3.16@34.113,14.564
  Power2 w0.254: R75.2@33.728,12.999 33.791,13.062 33.791,13.691 R74.1@33.895,13.794
NetT2_2: T2.2 T2.3 | length 5.4
  Power1 w1: T2.2@73.902,72.183 T2.3@73.902,74.903
  Power2 w1: T2.2@73.902,72.183 T2.3@73.902,74.903
NetU1_3: U1.3 U1.5 | length 4.7
  Power1 w0.254: U1.3@53.967,60.677 55.79,60.677 56.44,60.027 U1.5@58.417,60.027
NetU11_25: U11.25 U11.26 | length 0.5
  Power1 w0.254: U11.25@108.574,56.75 U11.26@108.574,57.25
Output_I: C70.1 J2.24 R31.2 TP16.1 | length 85.4
  Power1 w0.254: TP16.1@19.674,3 24.347,3 25.336,3.99 25.336,4.109 25.424,4.197 R31.2@25.424,5.443 ; C70.1@25.41,3.99 25.41,3.602 27.156,1.857 72.557,1.857 73.674,2.973 73.674,10.618 76.932,13.877 76.932,14.046 v1(76.98,14.095) ; v1(78.955,25.035) 78.963,25.043 81.466,25.043 J2.24@81.474,25.05
  Power2 w0.254: v1(76.98,14.095) 76.98,18.831 76.674,19.138 76.674,24.5 77.209,25.035 v1(78.955,25.035)
Output_V: C76.1 J2.26 R44.2 | length 37.6
  Power1 w0.254: R44.2@68.204,50.56 C76.1@69.426,50.56 ; C76.1@69.427,50.561 v1(74.612,50.561) ; v1(78.948,25.816) 78.965,25.833 81.457,25.833 J2.26@81.474,25.85
  Power2 w0.254: v1(74.612,50.561) 76.612,50.561 76.905,50.268 76.905,26.268 77.357,25.816 v1(78.948,25.816)
PA_IN: C82.1 U11.18 | length 2.9
  Power1 w0.254: U11.18@104.924,56.1 104.917,56.093 104.917,55.872 104.907,55.862 104.907,53.3 C82.1@104.962,53.246
PGND: C2.1 C3.1 C4.1 C5.1 C6.1 C7.1 C8.1 C9.1 C10.1 C11.1 C12.1 C13.1 C14.1 C15.1 C16.1 C17.1 C18.1 C19.1 C20.1 C21.1 C22.1 C23.1 C24.1 C25.1 C26.1 C27.1 C28.1 C29.1 C60.1 C61.1 C84.1 L4.1 Q1.1 Q1.2 Q1.3 Q2.1 R1.2 R2.2 R34.1 U1.4 U2.6 U3.6 | length 38.8
  Power1 w0.254: R2.2@54.674,23.853 54.674,22.5 55.275,21.899 56.986,21.899 60.422,18.462 63.263,18.462 63.979,19.178 R34.1@64.079,19.178
  Power1 w0.4: 51.647,61.426 51.884,61.426 53.258,60.052 53.478,60.052 53.503,60.027 U1.4@53.967,60.027 ; U1.4@53.986,60.046 54.699,60.046
  Power1 w0.6: v1(57.63,65.118) Q2.1@58.434,65.118
  Power2 w0.2: v1@34.437,21.565 33.043,22.958 33.043,31.389 35.69,34.035 v2(36.159,34.035) ; v2(37.462,37.662) 37.462,43.5
  Power2 w0.254: 34.437,21.153 34.437,21.395 v1@34.437,21.565
  Power2 w0.4: v1(63.405,35.419) R1.2@64.155,35.419
  other v1: 34.31,15.569 35.108,15.569 35.907,15.59 35.501,15.93 34.727,15.938 34.318,16.253 35.905,16.26 35.11,16.274 34.714,16.625 35.518,16.621 34.554,17.155 35.298,17.163 35.981,17.168 35.269,17.754 35.984,17.741 40.99,17.754 34.555,17.768 40.466,18.263 35.979,18.313 35.274,18.341 34.55,18.345 35.975,18.895 35.237,18.927 40.96,18.908 34.546,18.931 50.674,19 34.541,19.564 35.242,19.541 36.007,19.545 40.471,19.554 50.674,20 36.007,20.145 34.537,20.168 35.233,20.168 40.983,20.232 34.541,20.736 35.979,20.745 35.248,20.766 40.48,20.868 50.174,21 49.225,21.272 35.988,21.384 34.53,21.395 35.248,21.42 40.983,21.551 50.174,22 35.251,22.123 35.984,22.115 34.532,22.139 35.977,22.991 50.174,23 51.674,23 52.674,23 56.674,23 57.674,23 34.52,23.035 35.233,23.03 52.174,23.5 57.174,23.5 34.53,23.948 35.253,23.958 35.974,23.934 49.225,23.972 51.674,24 52.674,24 56.674,24 57.674,24 48.244,24.282 52.174,24.5 57.174,24.5 34.952,24.569 35.683,24.588 10.818,24.71 11.818,24.71 12.818,24.71 15.818,24.71 16.818,24.71 17.818,24.71 49.174,25 51.674,25 52.674,25 56.674,25 11.318,25.21 12.318,25.21 16.318,25.21 17.318,25.21 34.58,25.221 35.949,25.221 35.263,25.24 52.174,25.5 53.174,25.5 54.174,25.5 55.174,25.5 10.818,25.71 11.818,25.71 12.818,25.71 15.818,25.71 16.818,25.71 17.818,25.71 34.927,25.856 35.658,25.875 49.174,26 51.674,26 52.674,26 53.674,26 54.674,26 34.601,26.615 35.97,26.615 35.284,26.634 10.818,26.71 11.818,26.71 12.818,26.71 15.818,26.71 16.818,26.71 17.818,26.71 48.244,26.982 11.318,27.21 12.318,27.21 16.318,27.21 17.318,27.21 34.947,27.25 35.679,27.27 47.095,27.266 10.818,27.71 11.818,27.71 12.818,27.71 15.818,27.71 16.818,27.71 17.818,27.71 47.889,28.092 33.9,28.287 34.861,28.318 35.861,28.318 35.381,28.82 34.382,28.839 47.934,29.193 33.839,29.384 34.839,29.384 35.839,29.384 34.386,29.929 35.386,29.929 47.174,30 33.886,30.504 34.886,30.504 35.886,30.504 46.174,30.5 34.386,31.004 35.386,31.004 34.886,31.504 35.886,31.504 47.674,32 48.674,32 49.674,32 10.818,32.21 11.818,32.21 12.818,32.21 15.818,32.21 16.818,32.21 17.818,32.21 37.174,32.5 48.174,32.5 49.174,32.5 40.167,32.674 11.318,32.71 12.318,32.71 16.318,32.71 17.318,32.71 26.725,32.989 27.725,32.989 28.725,32.989 29.725,32.989 47.674,33 48.674,33 49.674,33 10.818,33.21 11.818,33.21 12.818,33.21 15.818,33.21 16.818,33.21 17.818,33.21 27.225,33.489 29.225,33.489 39.174,33.5 40.174,33.5 41.174,33.5 42.174,33.5 38.32,33.517 26.725,33.989 27.725,33.989 28.725,33.989 29.725,33.989 47.674,34 48.674,34 49.674,34 10.818,34.21 11.818,34.21 12.818,34.21 15.818,34.21 16.818,34.21 17.818,34.21 27.225,34.489 29.225,34.489 48.174,34.5 49.174,34.5 11.318,34.71 12.318,34.71 16.318,34.71 17.318,34.71 37.764,34.972 26.725,34.989 27.725,34.989 28.725,34.989 29.725,34.989 38.674,35 39.674,35 40.674,35 41.674,35 42.674,35 47.674,35 48.674,35 49.674,35 10.818,35.21 11.818,35.21 12.818,35.21 15.818,35.21 16.818,35.21 17.818,35.21 40.174,36.5 41.174,36.5 42.174,36.5 39.248,36.507 10.818,39.21 11.818,39.21 12.818,39.21 15.818,39.21 16.818,39.21 17.818,39.21 11.318,39.71 12.318,39.71 16.318,39.71 17.318,39.71 10.818,40.21 11.818,40.21 12.818,40.21 15.818,40.21 16.818,40.21 17.818,40.21 10.818,41.21 11.818,41.21 12.818,41.21 15.818,41.21 16.818,41.21 17.818,41.21 11.318,41.71 12.318,41.71 16.318,41.71 17.318,41.71 10.818,42.21 11.818,42.21 12.818,42.21 15.818,42.21 16.818,42.21 17.818,42.21 38.722,43.258 38.039,43.265 31.093,43.499 32.152,43.508 32.84,43.503 34.109,43.515 30.328,43.52 33.533,43.529 34.753,43.525 35.349,43.54 35.939,43.519 36.55,43.522 37.132,43.529 37.666,43.661 38.353,43.674 29.722,43.899 38.017,44.057 38.722,44.056 30.333,44.2 31.109,44.181 32.169,44.198 32.871,44.195 33.525,44.195 34.123,44.18 34.751,44.189 35.364,44.185 35.951,44.221 36.537,44.217 37.128,44.245 38.362,44.448 37.67,44.465 29.703,44.63 31.118,44.898 38.024,44.907 38.724,44.889 30.357,44.921 32.177,44.931 32.907,44.935 33.546,44.927 35.396,44.922 35.978,44.927 36.551,44.931 37.124,44.928 34.146,44.954 34.746,44.954 33.44,49.42 34.708,49.447 35.989,49.436 32.898,49.916 34.154,49.906 35.33,49.906 36.437,49.937 4.674,50.5 5.674,50.5 6.674,50.5 9.674,50.5 10.674,50.5 11.674,50.5 5.174,51 6.174,51 10.174,51 11.174,51 4.674,51.5 5.674,51.5 6.674,51.5 9.674,51.5 10.674,51.5 11.674,51.5 4.674,52.5 5.674,52.5 6.674,52.5 9.674,52.5 10.674,52.5 11.674,52.5 5.174,53 6.174,53 10.174,53 11.174,53 4.674,53.5 5.674,53.5 6.674,53.5 9.674,53.5 10.674,53.5 11.674,53.5 37.174,54.5 38.674,54.5 40.174,54.5 41.674,54.5 43.174,54.5 44.674,54.5 46.174,54.5 47.674,54.5 42.416,55.34 39.433,55.383 45.413,55.412 48.381,55.47 4.674,56.5 5.674,56.5 6.674,56.5 9.674,56.5 10.674,56.5 11.674,56.5 5.174,57 6.174,57 10.174,57 11.174,57 4.674,57.5 5.674,57.5 6.674,57.5 9.674,57.5 10.674,57.5 11.674,57.5 4.674,58.5 5.674,58.5 6.674,58.5 9.674,58.5 10.674,58.5 11.674,58.5 5.174,59 6.174,59 10.174,59 11.174,59 18.674,59 20.174,59 26.674,59 28.174,59 54.039,59.414 4.674,59.5 5.674,59.5 6.674,59.5 9.674,59.5 10.674,59.5 11.674,59.5 18.174,59.5 19.674,59.5 21.674,59.5 22.674,59.5 23.674,59.5 24.674,59.5 26.174,59.5 27.674,59.5 18.674,60 20.174,60 22.174,60 23.174,60 24.174,60 26.674,60 28.174,60 50.153,60.037 18.174,60.5 19.674,60.5 26.174,60.5 27.674,60.5 21.712,60.585 22.712,60.585 23.712,60.585 24.712,60.585 50.792,60.675 18.674,61 20.174,61 26.674,61 28.174,61 22.212,61.085 23.212,61.085 24.212,61.085 50.162,61.316 18.174,61.5 19.674,61.5 26.174,61.5 27.674,61.5 50.762,61.926 18.674,62 20.174,62 26.674,62 28.174,62 4.674,62.5 5.674,62.5 6.674,62.5 9.674,62.5 10.674,62.5 11.674,62.5 18.174,62.5 19.674,62.5 26.174,62.5 27.674,62.5 50.153,62.587 5.174,63 6.174,63 10.174,63 11.174,63 18.674,63 20.174,63 26.674,63 28.174,63 50.782,63.207 4.674,63.5 5.674,63.5 6.674,63.5 9.674,63.5 10.674,63.5 11.674,63.5 18.174,63.5 19.674,63.5 26.174,63.5 27.674,63.5 21.627,63.629 22.627,63.629 23.627,63.629 24.627,63.629 18.674,64 20.174,64 26.674,64 28.174,64 22.127,64.129 23.127,64.129 24.127,64.129 4.674,64.5 5.674,64.5 6.674,64.5 9.674,64.5 10.674,64.5 11.674,64.5 18.174,64.5 19.674,64.5 26.174,64.5 27.674,64.5 5.174,65 6.174,65 10.174,65 11.174,65 18.674,65 20.174,65 21.674,65 22.674,65 23.674,65 24.674,65 26.674,65 28.174,65 4.674,65.5 5.674,65.5 6.674,65.5 9.674,65.5 10.674,65.5 11.674,65.5 18.174,65.5 19.674,65.5 22.174,65.5 23.174,65.5 24.174,65.5 26.174,65.5 27.674,65.5 52.174,68 55.174,68.5 52.174,69 51.174,70 52.174,70 64.174,71 65.174,71 66.174,71 64.674,71.5 65.674,71.5 64.174,72 65.174,72 66.174,72 64.174,73 65.174,73 66.174,73 64.674,73.5 65.674,73.5 64.174,74 65.174,74 66.174,74 64.174,76 65.174,76 66.174,76 64.674,76.5 65.674,76.5 64.174,77 65.174,77 66.174,77 64.174,78 65.174,78 66.174,78 64.674,78.5 65.674,78.5 64.174,79 65.174,79 66.174,79
PGOOD_5V: C56.1 J2.56 R18.2 | length 33.7
  Power1 w0.254: v1(78.679,37.899) 78.703,37.874 81.449,37.874 J2.56@81.474,37.85
  Ground1 w0.254: v1(78.679,37.899) 78.679,40.005 79.637,40.963 v1(86.142,40.963)
  Power2 w0.254: v1(86.142,40.963) 103.663,40.963 104.547,41.847 R18.2@105.451,41.847 105.442,41.856 C56.1@105.442,43.109
PLC_HRPWM1: J2.49 R30.2 TP22.1 | length 36.7
  Power1 w0.254: v1(83.237,35.457) 83.244,35.45 J2.49@84.874,35.45 ; v1(100.174,51) 100.174,51.069 100.356,51.251 100.356,51.611 100.483,51.738 R30.2@100.674,51.738
  Power2 w0.254: v1(83.237,35.457) 82.547,36.147 82.547,44.073 83.011,44.538 99.211,44.538 99.674,45 99.674,46 ; v1(100.174,51) 99.674,50.5 99.674,46 ; v1(100.674,47) 99.674,46
PLC_HRPWM2: J2.51 R38.2 TP23.1 | length 37
  Power1 w0.254: v1(83.224,36.659) 83.634,36.25 J2.51@84.874,36.25 ; v1(101.912,51.198) 101.912,51.667 101.983,51.738 R38.2@102.174,51.738
  Power2 w0.254: v1(83.224,36.659) 83.224,43.551 83.674,44 101.674,44 102.174,44.5 102.174,46 ; v1(101.912,51.198) 102.174,50.937 102.174,46 ; v1(103.174,47) 102.174,46
PV_PGND: J1.2 R2.1 R37.1 | length 12.8
  Power1 w0.254: R2.1@54.674,19.433 54.674,20.812 55.295,21.433 56.81,21.433 60.24,18.002 63.285,18.002 63.994,17.293 R37.1@64.094,17.293
  other v1: 52.027,10.476 53.027,10.476 54.027,10.476 55.027,10.476 52.527,10.976 53.527,10.976 54.527,10.976 55.527,10.976 52.725,11.978 56.196,12.027 52.744,13.149 56.174,13.234 56.454,14.236 52.299,14.327 53.299,14.327 54.299,14.327 55.299,14.327 56.954,14.736 52.799,14.827 53.799,14.827 54.799,14.827 55.799,14.827 52.262,15.942 53.262,15.942 54.262,15.942 55.262,15.942 56.35,15.976 52.762,16.442 53.762,16.442 54.762,16.442 55.762,16.442 56.85,16.476 52.674,18.5 52.174,19 56.674,19 57.674,19 52.674,19.5 57.174,19.5 56.674,20
RSD_MCU: J2.59 J5.7 | length 39.8
  Power1 w0.254: J2.59@84.874,42.65 87.963,42.65 89.174,41.439 89.174,31 89.702,30.472 110.19,30.472 J5.7@112.524,28.138
RST_MCU: J2.57 J4.2 | length 61.3
  Power1 w0.254: J2.57@84.874,41.85 87.54,41.85 88.528,40.862 88.528,10.145 89.674,9 108.802,9 J4.2@112.893,4.909
SD_EN: J2.77 R54.2 U11.8 | length 25.7
  Power1 w0.254: J2.77@84.874,49.85 87.881,49.85 89.66,51.628 v1(89.66,56.975) ; v1(90.174,59) 90.679,59.505 94.866,59.505 95.445,60.085 R54.2@95.645,60.085 ; R54.2@95.645,60.127 96.53,60.127 97.907,58.75 U11.8@101.774,58.75
  Power2 w0.254: v1(89.66,56.975) 89.66,58.486 v1(90.174,59)
SPI_CLK: R27.1 R46.1 U11.3 | length 24.9
  Power1 w0.254: R27.1@89.77,47.552 89.943,47.725 90.444,47.725 v1(90.801,48.081) ; R46.1@94.174,57.75 94.374,57.75 94.497,57.627 94.497,57.474 94.624,57.347 v1(94.624,57.278) ; v1(100.953,61.331) 101.022,61.331 101.103,61.25 U11.3@101.774,61.25
  Power2 w0.254: v1(90.801,48.081) 90.801,49.37 96.698,55.267 ; v1@94.755,57.278 v1(94.624,57.278) 96.634,55.267 96.698,55.267 ; v1(100.953,61.331) 100.904,61.38 100.335,61.38 100.238,61.477 98.702,61.477 97.674,60.449 97.674,56.243 96.698,55.267
SPI_CS: R28.1 R49.1 U11.6 | length 22.5
  Power1 w0.254: R28.1@89.774,48.5 89.874,48.5 90.703,49.329 v1(91.625,49.329) ; R49.1@95.674,61.75 96.597,61.75 v1(98.42,59.927) ; v1@98.469,59.878 98.537,59.878 98.665,59.75 U11.6@101.774,59.75
  Power2 w0.254: v1(91.625,49.329) 98.42,56.124 v1(98.42,59.927)
SPI_SIMO: R24.1 R47.1 U11.4 | length 31.6
  Power1 w0.254: R24.1@89.734,45.636 89.763,45.665 91.731,45.665 v1(91.76,45.693) ; R47.1@94.174,61.75 94.374,61.75 94.951,62.327 96.989,62.327 98.239,61.077 99.109,61.077 99.309,60.877 99.774,60.877 99.871,60.78 99.949,60.78 99.979,60.75 U11.4@101.774,60.75
  Ground2 w0.254: v1(91.76,45.693) 92.695,45.693 94.133,47.132 94.133,53.281 96.273,55.421 96.273,60.6 96.666,60.992 99.213,60.992 99.328,60.877 99.774,60.877 v1(99.822,60.829)
SPI_SOMI: R26.1 R48.1 U11.5 | length 26.3
  Power1 w0.254: R26.1@89.749,46.619 89.914,46.454 v1@94.449,46.454 ; R48.1@95.674,57.75 95.797,57.873 95.883,57.787 96.981,57.787 v1(97.017,57.823) ; v1(99.034,60.331) 99.102,60.331 99.186,60.248 U11.5@101.601,60.248
  Ground2 w0.254: v1(94.457,46.462) 94.457,46.503 94.758,46.804 94.758,50.021 94.776,50.038 94.776,53.281 98.174,56.679 98.174,56.831 97.23,57.775 97.066,57.775 v1(97.017,57.823) ; 98.174,56.683 98.247,56.757 99.006,57.516 99.006,60.304 v1(99.034,60.331)
String_PGND: J3.2 L4.2 T2.7 | length 33.6
  Power1 w1: 44.174,82.5 52.705,82.5 T2.7@58.552,76.653
  Power2 w1: 44.174,82.5 52.705,82.5 T2.7@58.552,76.653
  other v1: 21.174,72.5 22.174,72.5 23.174,72.5 24.174,72.5 21.674,73 22.674,73 23.674,73 24.674,73 41.824,73.593 21.174,74 22.174,74 23.174,74 24.174,74 27.674,74 41.174,74 29.477,74.057 42.851,74.053 18.197,74.402 19.674,74.5 21.674,74.5 22.674,74.5 23.674,74.5 24.674,74.5 27.174,74.5 42.174,74.5 28.977,74.557 43.531,74.746 17.697,74.902 19.174,75 27.674,75 41.174,75 29.477,75.057 18.197,75.402 19.674,75.5 27.174,75.5 40.674,75.5 44.174,75.5 28.977,75.557 17.697,75.902 19.174,76 21.174,76 22.174,76 23.174,76 24.174,76 27.674,76 41.174,76 29.477,76.057 18.197,76.402 19.674,76.5 21.674,76.5 22.674,76.5 23.674,76.5 24.674,76.5 27.174,76.5 40.674,76.5 44.674,76.5 28.977,76.557 17.697,76.902 19.174,77 27.674,77 41.174,77 29.477,77.057 18.197,77.402 19.674,77.5 27.174,77.5 41.674,77.5 42.674,77.5 43.674,77.5 44.674,77.5 28.977,77.557 17.697,77.902 19.174,78 27.674,78 42.174,78 43.174,78 44.174,78 45.174,78 29.477,78.057 18.197,78.402 19.674,78.5 27.174,78.5 28.977,78.557 17.697,78.902 19.174,79 27.674,79 29.477,79.057 18.197,79.402 19.674,79.5 27.174,79.5 28.977,79.557 17.697,79.902 19.174,80 27.674,80 29.477,80.057 18.197,80.402 19.674,80.5 21.674,80.5 22.674,80.5 23.674,80.5 24.674,80.5 27.174,80.5 28.977,80.557 17.697,80.902 19.174,81 22.174,81 23.174,81 24.174,81 25.174,81 27.674,81 29.477,81.057 18.197,81.402 19.674,81.5 27.174,81.5 28.977,81.557 17.697,81.902 19.174,82
SW1: R33.1 R35.2 U3.5 | length 25.7
  Power1 w0.254: R33.1@26.485,12.514 26.485,12.614 25.721,13.377 25.721,20.268 26.559,21.105 28.933,21.105 29.685,20.353 29.685,19.155 R35.2@29.674,19.143
  Power2 w0.2: v2(32.174,32.5) 32.174,21.154 v1(32.509,20.819)
  other v1: 31.174,17.408 31.903,17.408 32.55,17.87 31.893,18.075 32.53,18.568 31.903,18.795 32.53,19.329 31.882,19.534 32.53,20.069 31.872,20.243
SW2: L1.1 R35.1 R36.1 | length 14.8
  Power1 w0.254: R36.1@24.439,12.514 24.439,12.614 25.174,13.348 25.174,20.451 26.356,21.633 28.943,21.633 29.7,22.39 29.7,23.536 R35.1@29.674,23.563
  other v1: 28.206,25.015 28.973,25.015 29.771,25.015 30.528,25.039 31.273,25.063 29.365,25.525 30.168,25.515 28.587,25.541 30.894,25.546 25.823,26.191 26.621,26.191 27.417,26.169 28.184,26.169 28.982,26.169 29.739,26.192 30.483,26.216 29.378,26.668 26.214,26.701 27.017,26.69 27.798,26.694 28.575,26.678 30.104,26.699 27.411,27.174 28.178,27.174 28.976,27.174 29.733,27.198 25.794,27.223 26.561,27.223 30.477,27.222 28.569,27.684 29.372,27.674 27.792,27.699 30.098,27.705 26.952,27.733 26.175,27.748 28.114,30.265 28.881,30.265 29.679,30.265 27.317,30.287 30.435,30.289 30.075,30.764 27.714,30.787 28.495,30.79 29.272,30.775 26.911,30.797
TX_PGA_IN: C80.2 R39.2 TP21.1 U11.13 | length 22.8
  Power1 w0.254: TP21.1@95.674,48 95.674,52.675 96.649,53.65 C80.2@96.674,53.65 96.972,53.352 97.464,53.352 97.674,53.143 97.674,50.51 97.869,50.314 102.059,50.314 103.483,51.738 R39.2@103.674,51.738 ; 97.452,53.352 99.143,55.043 101.466,55.043 102.35,55.927 102.417,55.927 102.424,55.934 U11.13@102.424,56.1
TX_PGA_OUT: R51.2 TP24.1 U11.14 | length 11.1
  Power1 w0.254: v1(98.03,49.429) 98.03,48.143 TP24.1@98.174,48 ; v1(98.527,52.797) 98.527,52.806 98.983,53.262 R51.2@99.174,53.262 99.364,53.262 100.644,54.542 101.763,54.542 102.917,55.695 102.917,56.093 U11.14@102.924,56.1
  Power2 w0.254: v1(98.03,49.429) 98.03,52.3 v1(98.527,52.797)
UART_RX: J2.76 J5.5 | length 43.3
  Power1 w0.254: J2.76@81.474,49.05 81.597,48.927 82.247,48.927 82.674,48.5 82.674,41.5 84.782,39.391 v1(86.354,39.391)
  Power2 w0.254: v1(86.354,39.391) 89.29,39.391 90.196,38.485 90.196,30.722 90.896,30.022 105.56,30.022 J5.5@107.444,28.138
UART_TX: J2.78 J5.6 | length 46
  Power1 w0.254: J2.78@81.474,49.85 81.597,49.727 82.434,49.727 83.358,48.803 83.358,41.815 85.174,40 v1(85.674,40)
  Power2 w0.254: v1(85.674,40) 89.789,40 91.015,38.774 91.015,31.233 91.247,31 107.122,31 J5.6@109.984,28.138
Vafe: C47.2 C48.2 C57.1 C58.1 C59.1 C96.2 C97.2 C98.2 C99.1 C100.1 C101.1 D9.1 L2.2 R19.2 R50.2 U4.4 U4.5 U11.44 U11.45 | length 87.7
  Power1 w0.254: C47.2@73.739,23.574 74.163,23.997 74.702,23.997 74.79,24.085 v1(74.859,24.085) ; v1(101.816,70) R50.2@102.412,70 ; 103.174,64.643 103.924,63.893 U11.45@103.924,62.9 ; 103.674,64.9 103.674,64.643 104.424,63.893 U11.44@104.424,62.9 ; D9.1@110.674,66.5 D9.1@111.185,65.988
  Power1 w0.4: D9.1@111.185,65.988 111.246,66.049 v1(112.688,66.049)
  Power1 w0.6: v1(90.132,19.575) 121.68,19.575 122.894,20.789 v1(122.894,44.904)
  Ground1 w0.6: v1(74.859,24.085) 87.607,24.085 88.512,23.181 88.512,20.162 89.099,19.575 v1(90.132,19.575)
  Power2 w0.254: R19.2@111.294,44.543 111.448,44.697 111.87,44.697 112.33,45.156 C57.1@112.33,46.759
  other v1: 95.674,65 98.424,65.125 99.924,65.125 101.424,65.125 95.668,65.938
VCC_5V: C36.2 C37.2 C38.2 C39.2 C40.2 C41.2 C42.2 C43.2 C54.1 C64.1 D5.1 D6.1 J2.48 J2.84 J2.98 J2.112 R5.1 R7.1 TP13.1 U6.1 U6.3 | length 205.8
  Power1 w0.254: D6.1@75.547,30.576 D6.1@75.843,30.28 ; v1(78.92,34.646) v1@78.922,34.648 ; J2.112@81.418,63.394 J2.112@81.474,63.45 ; J2.98@81.441,57.818 J2.98@81.474,57.85 ; J2.48@81.472,34.648 J2.48@81.474,34.65 ; v1(92.716,34.493) TP13.1@93.681,34.493
  Power1 w0.35: C37.2@42.027,41.218 42.227,41.418 42.227,41.908 42.263,41.943 v1(42.263,41.986)
  Power1 w0.4: C40.2@32.551,12.172 32.57,12.153 33.22,12.153 v1(33.239,12.135) ; v1(78.019,63.345) 78.048,63.345 v1@78.153,63.45 ; J2.112@81.368,63.45 J2.112@81.418,63.4
  Power1 w0.6: C41.2@31.344,12.172 C40.2@32.551,12.172 ; C37.2@42.027,41.218 42.027,39.72 42.322,39.425 46.599,39.425 48.674,41.5 53.58,41.5 v1(53.601,41.479) ; v1@78.153,63.45 J2.112@81.368,63.45 ; v1(78.554,57.785) 78.602,57.833 79.65,57.833 ; v1(78.905,52.311) 78.966,52.25 J2.84@81.474,52.25 ; v1@78.922,34.648 J2.48@81.472,34.648
  Ground2 w0.6: v1(33.239,12.135) 32.955,12.135 32.683,11.863 32.683,6.414 34.257,4.84 73.014,4.84 74.674,6.5 74.674,14.715 76.582,16.624 76.582,31.091 76.078,31.595 v1(75.249,31.595) ; v1(53.601,41.479) 53.622,41.5 73.674,41.5 75.778,39.395 75.778,34.345 v1(74.917,33.484) ; v1(75.222,32.494) 75.717,32.494 76.486,33.263 76.486,34.841 ; v1(78.019,63.345) 76.081,61.407 76.081,57.785 ; v1(78.554,57.785) 76.081,57.785 ; v1(78.905,52.311) 76.486,52.311 ; v1(78.92,34.646) 78.684,34.882 76.527,34.882 76.486,34.841 ; v1(94.174,39) 90.976,42.198 76.486,42.198 ; 76.081,57.785 76.081,52.662 76.432,52.311 76.486,52.311 ; 76.486,34.841 76.486,42.198 ; 76.486,42.198 76.486,52.311
  Power2 w0.254: v1(42.263,41.986) v1@42.285,42.008 ; C39.2@42.285,42.473 C39.2@42.307,42.495 ; v1@74.674,33.5 74.901,33.5 v1(74.917,33.484) ; C64.1@92.382,36.15 92.519,36.013 92.634,35.898 92.634,34.643 92.716,34.562 v1(92.716,34.493) ; U6.3@94.174,38.086 94.347,37.913 U6.3@94.381,37.913
  Power2 w0.35: v1(33.239,12.135) 33.247,12.143 33.805,12.143 C42.2@33.813,12.151 33.826,12.138 34.463,12.138 34.501,12.176 34.941,12.176 35.115,12.351 R7.1@35.229,12.351 ; R5.1@41.997,43.824 41.997,43.51 42.236,43.27 42.282,43.27 42.307,43.245 C39.2@42.307,42.495 ; v1@42.285,42.008 C39.2@42.285,42.473
  Power2 w0.4: U6.1@94.381,36.013 94.481,36.113 95.231,36.113 95.465,36.347 95.465,37.579 95.231,37.813 94.481,37.813 U6.3@94.381,37.913
  Power2 w0.6: C64.1@92.519,36.013 U6.1@94.381,36.013 ; U6.3@94.174,38.086 v1(94.174,39)
VIN+: C3.2 C5.2 C6.2 C7.2 C8.2 C9.2 C10.2 C11.2 C12.2 C13.2 C14.2 C21.2 C23.2 C25.2 C27.2 C29.2 C52.2 C53.2 C55.2 J1.1 R40.2 U3.7 U5.2 U5.3 | length 148.2
  Power1 w0.254: 43.815,30.185 v1(43.815,31.589) ; v1(62.174,42.5) 64.077,42.5 R40.2@64.097,42.48
  Ground1 w0.254: v1(43.815,31.589) 43.825,31.599 43.825,37.227 v1(43.834,37.237)
  Power2 w0.254: v1(43.834,37.237) 45.894,37.237 49.399,40.742 60.416,40.742 v1(62.174,42.5) ; C52.2@114.966,33.591 C52.2@114.973,33.598 ; C53.2@114.973,34.969 C53.2@114.98,34.976
  Power2 w0.8: J1.1@47.355,12.608 47.355,4.819 48.067,4.107 76.988,4.107 77.928,3.167 116.196,3.167 117.17,4.141 117.17,34.704 116.973,34.901 115.055,34.901 C53.2@114.98,34.976 ; C55.2@111.015,33.221 111.015,32.693 111.708,32 113.976,32 114.973,32.996 114.973,33.598 C53.2@114.973,34.969
  other v1: 46.02,10.502 47.02,10.502 48.02,10.502 49.02,10.502 50.02,10.502 45.52,11.002 46.52,11.002 48.52,11.002 49.52,11.002 46.617,12.293 45.633,12.314 49.597,12.413 46.641,13.21 45.657,13.225 49.597,13.312 45.918,14.264 46.918,14.264 47.918,14.264 48.918,14.264 49.918,14.264 46.418,14.764 47.418,14.764 48.418,14.764 49.418,14.764 45.93,15.542 46.93,15.542 47.93,15.542 48.93,15.542 49.93,15.542 46.43,16.042 47.43,16.042 48.43,16.042 49.43,16.042 45.381,18.783 44.27,19.442 45.381,19.783 44.27,20.442 45.381,20.783 44.27,21.442 44.936,22.056 38.283,22.339 44.282,22.73 38.954,22.934 44.972,23.284 38.343,23.384 38.963,23.646 37.899,25.087 38.689,25.096 43.985,25.171 39.027,25.713 43.985,26.24 39.043,26.528 41.129,28.439 38.997,28.476 38.174,28.5 39.941,28.488
VOUT: C2.2 C4.2 C15.2 C16.2 C17.2 C18.2 C19.2 C20.2 C22.2 C24.2 C26.2 C28.2 C60.2 C61.2 J3.1 Q1.5 Q1.6 Q1.7 Q1.8 Q1.9@46.023,62.587 Q2.3 R6.1 R41.2 U2.7 | length 61
  Power1 w0.254: 49.243,66.93 60.743,66.93 62.674,65 73.674,65 75.674,63 75.674,45.649 75.036,45.011 74.192,45.011 R41.2@74.004,44.823
  Power1 w0.4: 49.174,66.5 60.174,66.5 60.834,65.84 Q2.3@60.834,64.168
  other v1: 23.992,47.224 29.091,47.208 23.492,47.724 29.591,47.708 29.091,48.208 23.992,48.224 29.591,48.708 23.492,48.724 23.992,49.224 29.091,49.208 29.591,49.708 23.492,49.724 29.091,50.208 23.992,50.224 24.996,50.384 25.996,50.384 26.996,50.384 27.996,50.384 25.496,50.884 26.496,50.884 27.496,50.884 24.982,51.618 25.982,51.618 26.982,51.618 27.982,51.618 25.482,52.118 26.482,52.118 27.482,52.118 25.021,52.703 26.021,52.703 27.021,52.703 28.021,52.703 25.521,53.203 26.521,53.203 27.521,53.203 39.464,58.698 42.402,58.815 45.398,58.85 47.658,59.589 44.637,59.618 46.079,59.599 42.989,59.648 37.046,59.795 38.704,59.824 40.057,59.873 41.744,59.854 46.285,60.729 45.1,60.751 47.687,60.762 45.785,61.229 47.187,61.262 45.1,61.751 46.285,61.729 47.687,61.762 45.785,62.229 47.187,62.262 46.285,62.729 45.1,62.751 47.687,62.762 45.785,63.229 47.187,63.262 46.285,63.729 45.1,63.751 47.687,63.762 45.785,64.229 47.187,64.262 48.276,73.763 49.276,73.763 50.276,73.763 47.467,73.828 51.467,73.828 48.776,74.263 49.776,74.263 46.967,74.328 50.967,74.328 47.467,74.828 51.467,74.828 46.967,75.328 50.967,75.328 47.467,75.828 51.467,75.828 46.967,76.328 50.967,76.328 47.467,76.828 51.467,76.828 46.967,77.328 50.967,77.328 47.467,77.828 48.467,77.828 49.467,77.828 50.467,77.828 47.967,78.328 48.967,78.328 49.967,78.328 50.967,78.328
pads on no net: H1.1 H3.1 H4.1 H5.0 H6.0 H7.0 H8.0 J2.1 J2.3 J2.4 J2.5 J2.6 J2.8 J2.9 J2.11 J2.13 J2.15 J2.16 J2.17 J2.18 J2.21 J2.25 J2.27 J2.28 J2.30 J2.31 J2.32 J2.33 J2.34 J2.36 J2.37 J2.39 J2.40 J2.41 J2.42 J2.43 J2.44 J2.45 J2.54 J2.58 J2.60 J2.61 J2.62 J2.63 J2.64 J2.66 J2.68 J2.70 J2.72 J2.74 J2.80 J2.81 J2.82 J2.85 J2.87 J2.89 J2.91 J2.92 J2.93 J2.95 J2.99 J2.100 J2.101 J2.102 J2.103 J2.104 J2.105 J2.106 J2.107 J2.108 J2.109 J2.110 J2.113 J2.114 J2.115 J2.116 J2.117 J2.118 J2.119 J2.120 J2.181 J2.182 J2.185 J2.186 J4.1 J4.3 J4.4 J4.5 J4.6 J5.2 J5.3 J5.4 J5.8 L1.MP LBL1.0 Q1.9@45.338,61.257 Q1.9@45.338,62.587 Q1.9@45.338,63.917 Q1.9@46.353,62.587 Q1.9@46.488,61.257 Q1.9@46.488,62.587 Q1.9@46.488,63.917 Q1.9@47.638,61.257 Q1.9@47.638,62.587 Q1.9@47.638,63.917 Q1.9@47.933,60.214 Q1.9@47.933,64.959 T1.1 T1.3 T2.5 T2.6 T2.9 U2.1 U2.2 U3.1 U3.2 U11.10 U11.31 U11.32 U11.33 U11.36 U11.37 U11.47 U11.48 U11.49@103.804,58.13 U11.49@103.804,59.5 U11.49@103.804,60.87 U11.49@105.174,58.13 U11.49@105.174,59.5 U11.49@105.174,60.87 U11.49@106.544,58.13 U11.49@106.544,59.5 U11.49@106.544,60.87
copper on no net:
  other v3: 19.174,10 62.174,10 19.174,53 62.174,53

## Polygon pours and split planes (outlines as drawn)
PGND on Power1 "NONET_L-01_P-001" (solid, remove dead copper, pour order 77): 48.522,18 50.674,18 51.674,19 51.674,22 51.68,22 52.361,22.68 57.854,22.68 58.174,23 58.174,27 53.174,32 48.174,37 36.521,37 36.174,36.652 36.174,31.421 43.253,31.421 45.174,29.5 45.174,28 46.674,26.5 46.674,24.5 47.674,23.5 47.674,21.498 48.177,20.994 48.177,18.344
VIN+ on Power1 "NONET_L-01_P-001" (solid, pour order 0): 45.652,9.848 50.291,9.848 50.674,10.231 50.674,15.85 48.174,18.35 48.174,21 47.674,21.5 47.674,23.5 46.674,24.5 46.674,26.5 45.174,28 45.174,29.5 43.674,31 37.174,31 37.024,30.85 37.024,16.844 37.719,16.149 42.627,16.149 44.866,13.909 44.866,10.634
VOUT on Power1 "NONET_L-01_P-001" (solid, pour order 6): 38.061,46.49 37.55,45.98 30.484,45.98 29.99,46.474 17.398,46.474 16.174,47.698 16.174,53.305 18.368,55.5 26.424,55.5 36.424,65.5 46.238,75.314 46.238,79.842 46.741,80.345 53.119,80.345 53.568,79.895 53.568,75.035 49.831,71.298 49.831,65.912 48.535,64.615 48.535,57.634 48.194,57.293 36.733,57.293 36.174,56.734 36.174,52.484 38.061,50.596
PV_PGND on Power1 "NONET_L-01_P-001" (solid, pour order 9): 53.078,20.59 53.087,20.599 57.045,20.599 58.135,19.509 58.135,12.735 55.261,9.86 52.033,9.86 51.561,10.332 51.561,19.071 53.085,20.594
PGND on Power1 "NONET_L-01_P-001" (solid, pour order 84): 49.492,64 51.674,64 52.174,63.5 52.174,61 52.918,60.256 54.754,60.256 55.174,59.836 55.174,55 53.674,53.5 37.174,53.5 36.174,54.5 36.174,56.734 36.736,57.297 48.21,57.297 48.21,57.309 48.674,57.772 48.674,63.181
SW1 on Power1 "NONET_L-01_P-001" (solid, pour order 3): 33.47,21.562 33.665,21.372 33.665,18.098 32.517,16.95 27.921,16.95 27.562,17.31 27.562,19.911 27.98,20.33 31.39,20.33 32.622,21.562
PGND on Power1 "NONET_L-01_P-001" (solid, pour order 88): 38.861,43.047 39.174,42.735 39.174,39 41.174,37 41.174,34.5 38.081,31.408 36.246,31.408 36.246,27.351 34.322,27.351 33.174,28.5 33.174,37.5 37.579,41.905 37.579,43.047
GND on Power1 "NONET_L-01_P-001" (solid, pour order 90): 109.244,38.493 111.844,38.493 111.844,37.193 109.244,37.193
PGND on Power1 "NONET_L-01_P-001" (solid, pour order 87): 28.174,66.5 29.674,65 29.674,59.5 26.174,56 17.174,56 15.674,57.5 15.674,65 17.174,66.5
GND on Power1 "NONET_L-01_P-001" (solid, pour order 86): 108.954,61.028 106.367,61.028 105.629,61.766 105.629,63.295 106.109,63.775 108.846,63.775 109.417,63.204 109.417,61.49 108.957,61.03
GND on Power1 "NONET_L-01_P-001" (solid, pour order 85): 71.174,25.5 74.174,25.5 75.174,26.5 75.174,28 73.174,30 73.174,34.201 74.969,35.997 74.969,39.704 74.674,40 73.174,40 72.674,39.5 72.674,34.687 71.174,33.187 71.174,29.5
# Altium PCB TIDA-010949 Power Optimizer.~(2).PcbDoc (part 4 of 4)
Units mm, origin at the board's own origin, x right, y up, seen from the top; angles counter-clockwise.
Board outline 129.4 x 84 mm, 4 copper layers (Power1, Ground1, Ground2, Power2), stack 1.926 mm thick; 262 components, 129 nets, 791 pads, 1191 vias.

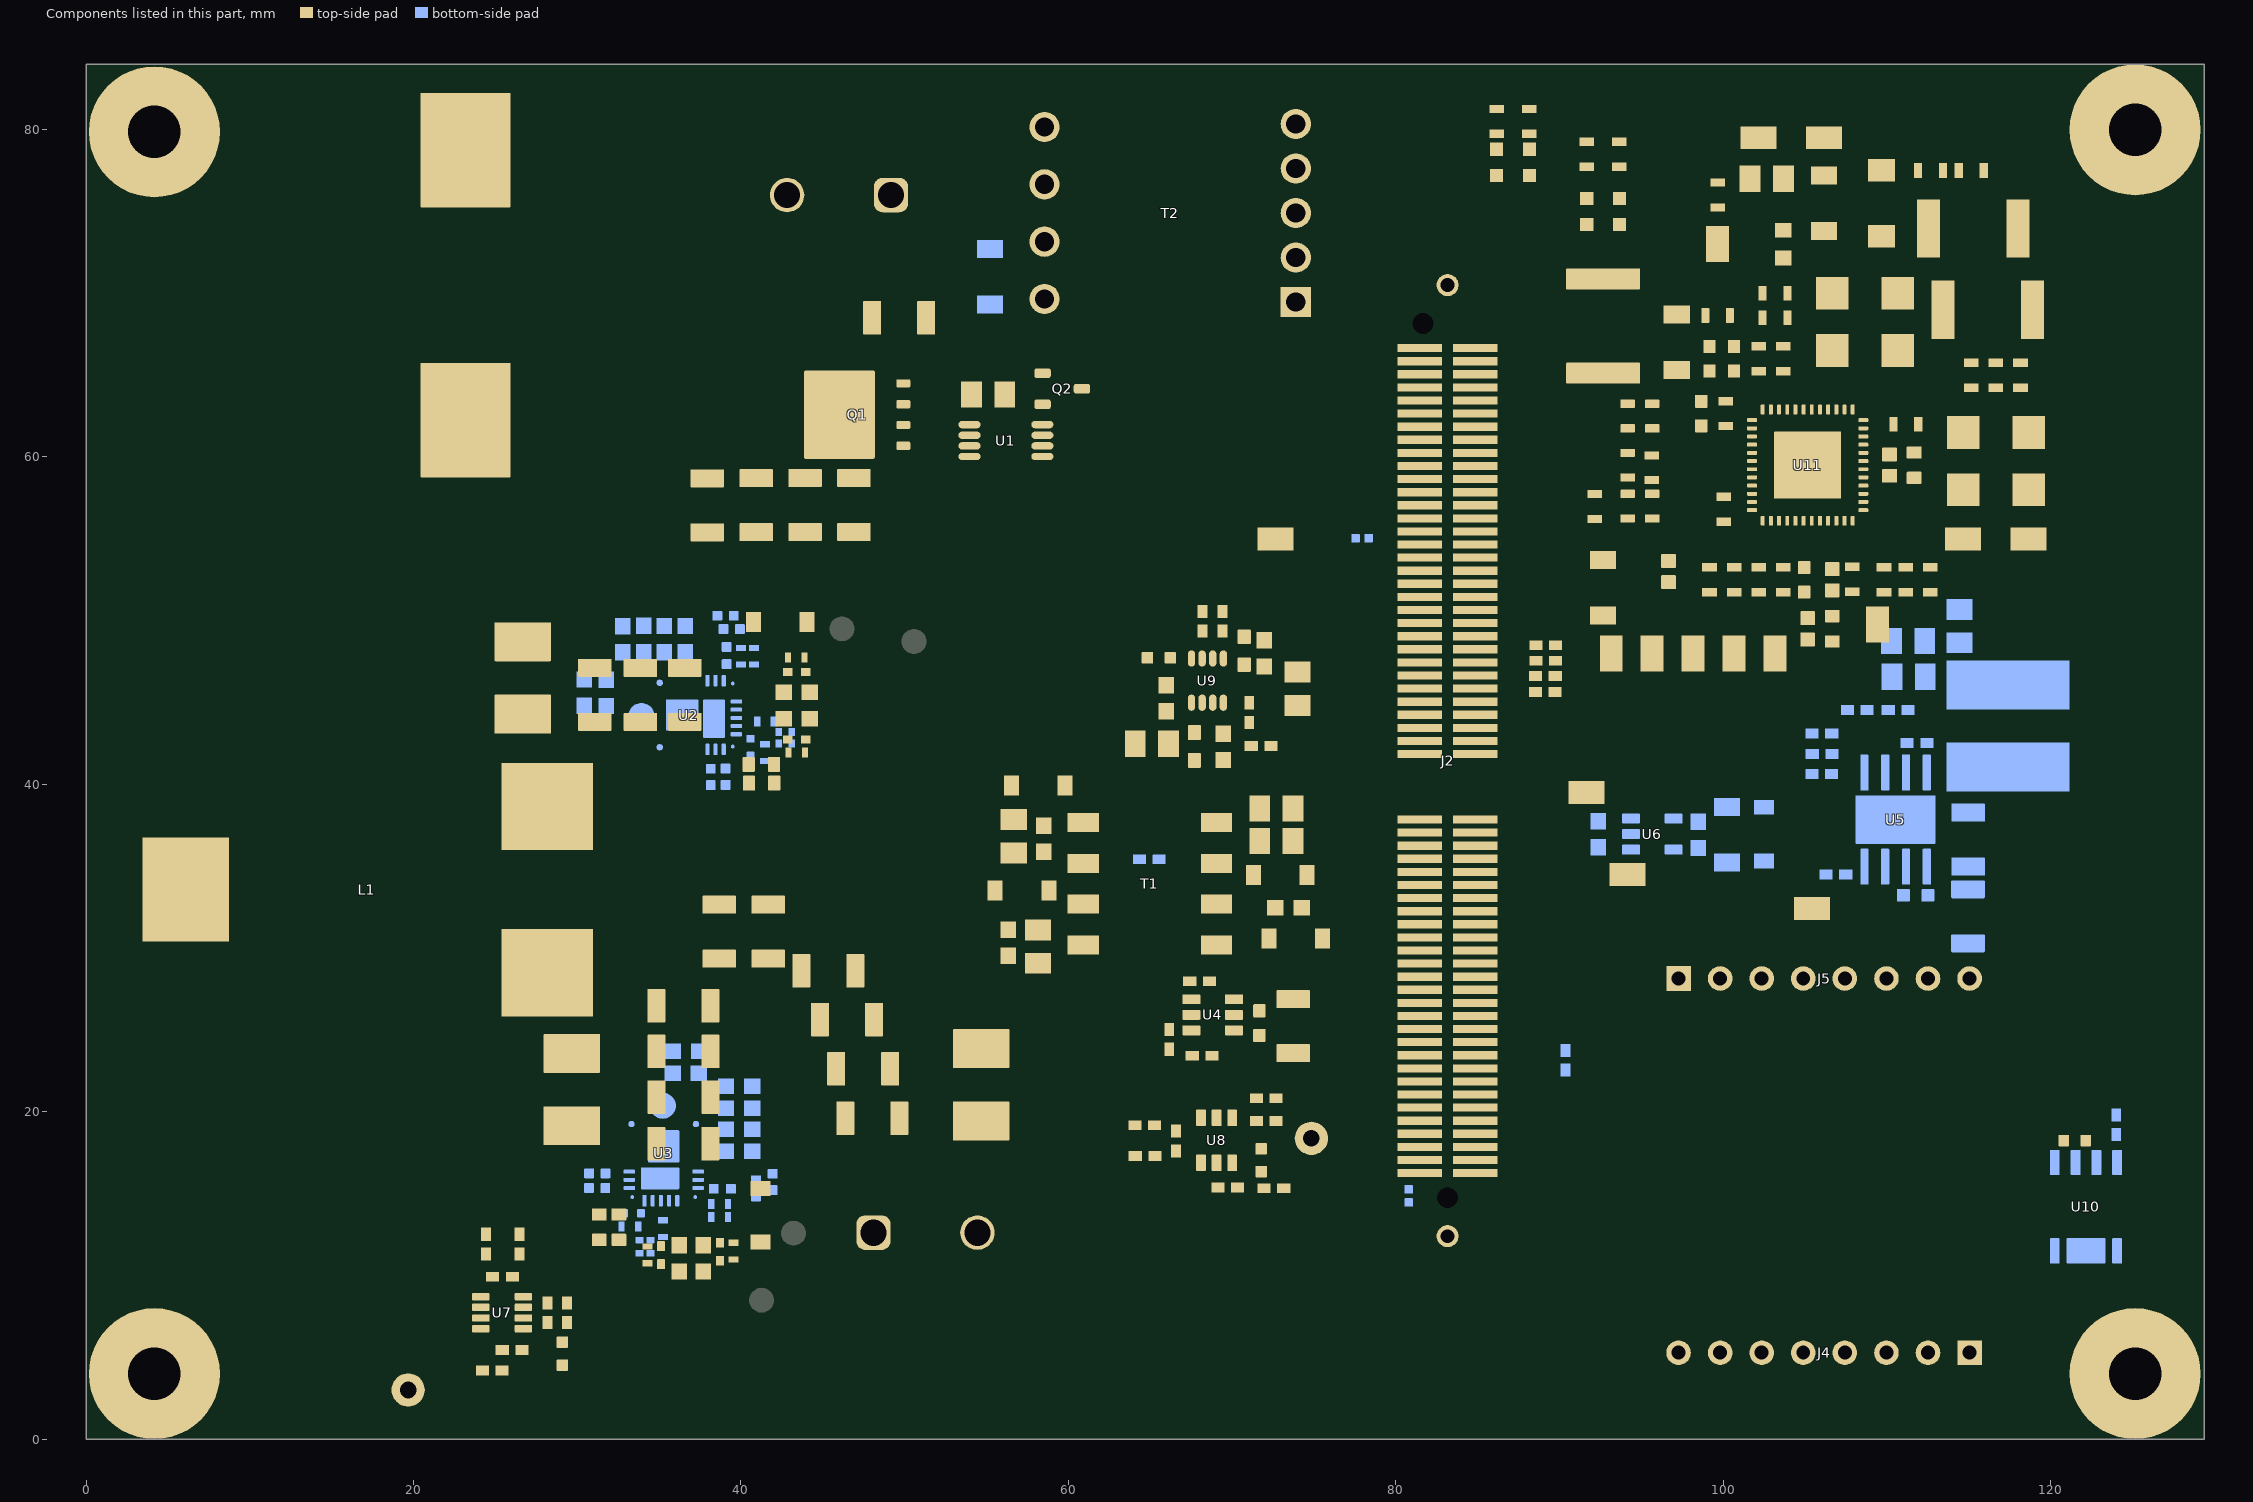
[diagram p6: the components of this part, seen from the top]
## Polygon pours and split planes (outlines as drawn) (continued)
PGND on Power1 "NONET_L-01_P-001" (solid, pour order 83): 56.174,71.5 56.674,71 56.674,67.5 56.174,67 49.824,67 49.674,67.15 49.674,71 50.174,71.5
Vafe on Power1 "NONET_L-01_P-001" (solid, pour order 58): 69.721,26.282 69.729,26.289 70.62,26.289 70.919,25.99 70.919,25.306 71.119,25.107 72.025,25.107 72.762,24.369 75.277,24.369 75.277,22.979 71.15,22.979 69.468,24.661 69.468,26.026 69.719,26.276
Vafe on Power1 "NONET_L-01_P-001" (solid, pour order 70): 89.44,64.477 88.835,65.082 88.835,65.716 89.382,66.264 97.632,66.264 98.209,65.688 104.063,65.688 104.163,65.587 104.163,64.816 103.851,64.504
NetD9_2 on Power1 "NONET_L-01_P-001" (solid, pour order 68): 107.6,65.38 107.571,65.38 105.696,65.38 105.541,65.535 105.541,67.565 105.135,67.971 103.704,67.971 103.569,68.106 103.569,71.277 103.124,71.722 99.161,71.722 98.89,71.993 98.89,72.031 98.89,73.752 99.257,74.119 100.572,74.119 102.061,72.631 104.188,72.631 105.773,71.045 107.784,71.045 107.958,70.871 107.958,65.709 107.629,65.38
NetC50_1 on Power1 "NONET_L-01_P-001" (solid, pour order 60): 68.014,33.828 71.815,33.828 72.412,34.425 72.412,39.334 72.135,39.611 68.014,39.611
VCC_5V on Power1 "NONET_L-01_P-001" (solid, pour order 59): 74.711,29.942 75.431,29.942 75.622,30.133 75.622,34.585 75.041,35.165 74.138,35.165 73.763,34.79 73.763,30.199 74.006,29.957
NetC46_1 on Power1 "NONET_L-01_P-001" (solid, pour order 57): 68.305,30.863 68.378,30.936 70.248,30.936 70.802,30.382 70.802,26.715 70.614,26.527 69.6,26.527 69.256,26.872 69.256,27.377 69.02,27.613 68.274,27.613 68.197,27.689 68.197,29.41 68.064,29.544 68.064,30.648
ISO1_GND on Power1 "NONET_L-01_P-001" (solid, pour order 52): 56.174,30 59.171,30 60.11,30.938 61.737,30.938 62.05,30.625 62.05,28.607 61.549,28.106 56.088,28.106 55.477,28.716 55.477,29.655 55.806,29.984
ISO1_5V on Power1 "NONET_L-01_P-001" (solid, pour order 51): 55.18,34.272 56.291,34.272 56.917,33.646 56.917,32.722 57.668,31.971 58.92,31.971 59.265,31.627 59.265,30.688 58.952,30.375 56.964,30.375 56.714,30.625 55.509,30.625 54.805,31.33 54.805,33.896
ISO2_5V on Power1 "NONET_L-01_P-001" (solid, pour order 49): 56.039,40.608 57.163,40.608 59.164,38.607 59.164,37.143 58.896,36.875 55.874,36.875 55.544,37.205 55.544,40.113
ISO2_GND on Power1 "NONET_L-01_P-001" (solid, pour order 50): 55.966,36.446 59.098,36.446 59.507,36.037 61.664,36.037 61.989,35.712 61.989,34.578 61.813,34.401 59.963,34.401 59.498,34.866 55.817,34.866 55.436,35.247 55.436,36.227 55.653,36.445
NetC65_1 on Power1 "NONET_L-01_P-001" (solid, pour order 40): 26.395,8.279 27.289,8.279 27.953,7.615 29.709,7.615 29.89,7.434 29.89,5.81 29.521,5.441 28.7,5.441 28.323,5.818 28.323,6.319 27.986,6.655 27.798,6.655 27.281,7.172 26.304,7.172 26.14,7.336 26.14,8.05 26.362,8.271
NetC67_1 on Power1 "NONET_L-01_P-001" (solid, pour order 39): 69.934,17.302 69.998,17.365 70.714,17.365 71.352,16.726 72.174,16.726 72.384,16.515 72.384,14.999 72.293,14.908 70.026,14.908 69.878,15.055 69.878,16.087 69.703,16.263 69.703,17.187 69.815,17.299
PGND on Power1 "NONET_L-01_P-001" (solid, pour order 36): 36.246,27.715 36.246,15.34 36.161,15.254 33.888,15.254 33.848,15.295 33.848,16.547 34.274,16.972 34.274,27.664 34.411,27.801 36.16,27.801
PGND on Power1 "NONET_L-01_P-001" (solid, pour order 33): 29.507,45.198 38.977,45.198 39.028,45.147 39.028,42.874 38.988,42.834 37.735,42.834 37.31,43.26 29.579,43.26 29.421,43.418 29.421,45.112
VOUT on Power1 "NONET_L-01_P-001" (solid, pour order 10): 31.174,60 31.174,66 35.174,70 41.174,70 41.174,60
String_PGND on Power1 "NONET_L-01_P-001" (solid, pour order 8): 45.674,76 45.674,82.836 45.009,83.5 0,83.5 0,71 40.674,71
BOOST_SW on Power1 "NONET_L-01_P-001" (solid, pour order 7): 36.902,42.487 28.95,42.487 28.403,43.034 27.973,43.034 27.973,40.201 28.514,39.659 30.901,39.659 31.442,40.201 35.483,40.201 36.904,41.623
BOOST_SW on Power1 "NONET_L-01_P-001" (solid, pour order 5): 25.161,36.04 25.335,35.865 30.887,35.865 31.224,36.202 31.224,41.174 30.779,41.619 28.933,41.619 28.502,42.05 28.502,45.334 28.357,45.479 24.966,45.479 24.85,45.364 24.85,36.339 25.166,36.024
SW2 on Power1 "NONET_L-01_P-001" (solid, pour order 4): 27.979,22.39 31.421,22.39 31.674,22.642 31.674,25.315 31.183,25.806 31.183,31.025 30.889,31.319 25.533,31.319 25.238,31.025 25.238,25.845 25.584,25.5 27.683,25.5 27.858,25.325 27.858,22.507 27.975,22.39
Vafe on Power2 "NONET_L-01_P-001" (solid, pour order 92): 122.674,44.431 125.181,44.431 125.199,44.449 125.199,67.518 121.94,70.776 89.847,70.776 88.674,69.603 88.674,65.244 89.441,64.477 121.697,64.477 122.674,63.5 122.674,44.437
VIN+ on Power2 "NONET_L-01_P-001" (solid, pour order 32): 45.657,9.843 50.286,9.843 50.677,10.234 50.677,15.844 48.177,18.344 48.177,20.994 47.677,21.494 47.677,23.494 46.677,24.494 46.677,26.494 45.177,27.994 45.177,29.494 43.677,30.994 37.177,30.994 37.018,30.836 37.018,16.848 37.724,16.142 42.631,16.142 44.924,13.849 44.924,10.576
VOUT on Power2 "NONET_L-01_P-001" (solid, pour order 31): 38.032,46.45 37.558,45.975 30.507,45.975 30.005,46.477 17.413,46.477 16.189,47.701 16.189,53.309 18.384,55.504 26.44,55.504 36.44,65.504 46.253,75.317 46.253,79.845 46.756,80.348 53.134,80.348 53.584,79.899 53.584,75.039 49.847,71.301 49.847,65.915 48.551,64.619 48.551,57.637 48.21,57.297 36.748,57.297 36.174,56.722 36.174,52.503 38.032,50.644
PGND on Power2 "NONET_L-01_P-001" (solid, pour order 95): 34.322,27.351 33.437,28.237 33.437,31.027 39.392,36.982 47.174,36.982 47.174,34 44.969,31.795 36.489,31.795 36.246,31.552 36.246,27.351
PV_PGND on Power2 "NONET_L-01_P-001" (solid, pour order 27): 53.078,20.59 53.087,20.599 57.045,20.599 58.224,19.42 58.224,12.823 54.761,9.36 52.14,9.36 51.561,9.939 51.561,19.071 53.085,20.594
SW1 on Power2 "NONET_L-01_P-001" (solid, pour order 17): 33.47,21.562 33.665,21.372 33.665,17.391 33.223,16.95 27.921,16.95 27.562,17.31 27.562,19.911 27.98,20.33 31.39,20.33 32.622,21.562
amb_tmp on Power2 "NONET_L-01_P-001" (solid, pour order 94): 119.155,12.369 129.162,12.369 129.162,0.249 119.155,0.249
GND on Power2 "NONET_L-01_P-001" (solid, pour order 89): 103.144,61.449 107.144,61.449 107.144,57.5 103.144,57.5
PGND on Power2 "NONET_L-01_P-001" (solid, pour order 30): 32.258,49.167 32.146,49.279 32.146,50.11 32.448,50.411 36.949,50.411 37.293,50.067 37.293,49.279 37.181,49.167
PGND on Power2 "NONET_L-01_P-001" (solid, pour order 29): 40.197,22.038 40.289,22.131 41.17,22.131 41.48,21.821 41.48,17.135 41.299,16.955 40.368,16.955 40.197,17.127
PGND on Power2 "NONET_L-01_P-001" (solid, pour order 82): 56.174,71.5 56.674,71 56.674,67.59 56.084,67 50.674,67 50.174,67.5 50.174,71 50.674,71.5
PGND on Power2 "NONET_L-01_P-001" (solid, pour order 81): 36.452,57 47.674,57 50.959,60.286 55.888,60.286 57.674,58.5 57.674,54.5 56.674,53.5 36.674,53.5 36.174,54 36.174,56.722
PGND on Power2 "NONET_L-01_P-001" (solid, pour order 79): 49.487,63.995 49.492,64 52.174,64 52.674,63.5 52.674,58.5 52.174,58 49.174,58 48.674,58.5 48.674,63.5 49.174,64
PGND on Power2 "NONET_L-01_P-001" (solid, pour order 78): 49.1,18 50.674,18 51.674,19 51.674,22 52.342,22.668 58.594,22.668 59.304,23.379 59.304,36.4 58.704,37 46.674,37 44.174,34.5 44.174,31.077 45.581,29.669 45.581,28.169 47.081,26.669 47.081,24.625 48.081,23.625 48.081,21.5 48.581,21 48.581,18.519
3V3 on Power2 "NONET_L-01_P-001" (solid, pour order 54): 96.718,36.634 103.835,36.634 104.163,36.306 104.163,33.989 103.762,33.589 96.585,33.589 96.258,33.915 96.258,36.174
Vafe on Power2 "NONET_L-01_P-001" (solid, pour order 62): 111.875,49.531 111.897,49.552 114.965,49.552 116.911,47.606 123.481,47.606 123.481,44.431 113.736,44.431 113.232,44.935 113.232,45.575 112.905,45.901 111.769,45.901 111.598,46.072 111.598,49.261 111.868,49.531
NetC49_1 on Power2 "NONET_L-01_P-001" (solid, pour order 61): 112.203,42.817 112.234,42.848 120.826,42.848 121.174,42.5 121.174,39.751 120.952,39.53 112.271,39.53 112.042,39.758 112.042,42.646 112.213,42.817
GND on Power2 "NONET_L-01_P-001" (solid, pour order 55): 97.644,37.159 103.617,37.159 104.319,37.861 104.319,39.278 103.984,39.613 96.839,39.613 96.31,39.085 96.31,37.738 96.89,37.159
VIN+ on Power2 "NONET_L-01_P-001" (solid, pour order 38): 114.174,35.5 117.174,35.5 118.674,34 118.674,32.421 118.103,31.851 114.404,31.851 113.928,32.327 113.928,35.254
VIN+ on Power2 "NONET_L-01_P-001" (solid, pour order 37): 109.734,36.043 111.354,36.043 111.422,35.974 111.422,32.655 111.281,32.514 109.803,32.514 109.574,32.742 109.574,35.883
PGND on Power2 "NONET_L-01_P-001" (solid, pour order 35): 36.242,27.716 36.242,15.33 36.162,15.25 33.889,15.25 33.849,15.29 33.849,16.543 34.275,16.968 34.275,27.66 34.411,27.797 36.161,27.797
PGND on Power2 "NONET_L-01_P-001" (solid, pour order 34): 29.504,45.189 38.992,45.189 39.034,45.147 39.034,42.875 38.994,42.834 37.742,42.834 37.316,43.26 29.585,43.26 29.427,43.418 29.427,45.112
SW2 on Power2 "NONET_L-01_P-001" (solid, pour order 16): 27.979,22.39 31.421,22.39 31.674,22.642 31.674,25.315 31.183,25.806 31.183,31.025 30.889,31.319 25.533,31.319 25.238,31.025 25.238,25.845 25.584,25.5 27.683,25.5 27.858,25.325 27.858,22.507 27.975,22.39
BOOST_SW on Power2 "NONET_L-01_P-001" (solid, pour order 15): 36.902,42.487 28.95,42.487 28.403,43.034 27.973,43.034 27.973,40.201 28.514,39.659 30.901,39.659 31.442,40.201 35.483,40.201 36.904,41.623
BOOST_SW on Power2 "NONET_L-01_P-001" (solid, pour order 14): 25.161,36.04 25.335,35.865 30.887,35.865 31.224,36.202 31.224,41.174 30.779,41.619 28.933,41.619 28.502,42.05 28.502,45.334 28.357,45.479 24.966,45.479 24.85,45.364 24.85,36.339 25.166,36.024
VOUT on Power2 "NONET_L-01_P-001" (solid, pour order 13): 31.166,60.005 31.166,66.005 35.166,70.005 41.166,70.005 41.166,60.005
String_PGND on Power2 "NONET_L-01_P-001" (solid, pour order 11): 45.674,76 45.674,82.836 45.009,83.5 0,83.5 0,71 40.674,71
PGND on Ground1 "NONET_L-01_P-001" (solid, pour order 75): 0.174,83.5 72.174,83.5 72.174,5 68.174,1 0.174,1
GND on Ground1 "NONET_L-01_P-001" (solid, pour order 74): 25.674,16.5 33.555,16.5 33.555,14.951 36.721,14.951 40.055,11.476 47.531,4 64.674,4 66.174,5.5 66.174,22.97 65.174,23.97 65.174,38.5 62.674,41 45.674,41 43.174,38.5 40.033,38.5 37.623,40 37.623,42.467 39.328,42.467 39.328,45.116 42.212,48 66.674,48 71.389,52.716 71.389,83.5 129.401,83.5 129.401,0.5 19.277,0.5 18.174,1.604 18.174,9
SW1 on Ground1 "NONET_L-01_P-001" (solid, pour order 63): 32.64,21.084 32.842,20.887 32.842,17.304 32.487,16.95 27.921,16.95 27.562,17.31 27.562,19.911 27.98,20.33 31.39,20.33 32.144,21.084
BOOST_SW on Ground1 "NONET_L-01_P-001" (solid, pour order 66): 36.409,41.671 36.409,41.235 35.786,40.612 31.645,40.612 30.88,39.848 30.88,37.435 29.643,36.198 25.776,36.198 25.349,36.625 25.349,41.41 25.731,41.792 36.288,41.792
3V3 on Ground2 "NONET_L-01_P-001" (solid, pour order 93): 90.071,71 120.174,71 122.174,69 122.174,54.5 120.174,52.5 89.174,52.5 87.674,54 87.674,68.603
PGND on Ground2 "NONET_L-01_P-001" (solid, pour order 98): 0,83.358 70.965,83.358 70.965,4.858 66.965,0.858 0,0.858
ISO1_GND on Ground2 "NONET_L-01_P-001" (solid, pour order 97): 37,14.952 37,16.5 42.273,16.5 42.789,15.984 42.789,11.733 42.275,11.219 39.946,11.219 37.002,14.163
ISO2_GND on Ground2 "NONET_L-01_P-001" (solid, pour order 96): 37.824,45.953 37.824,50.325 38.659,51.16 44.204,51.16 44.77,50.594 44.77,49.643 41.08,45.953
SW1 on Ground2 "NONET_L-01_P-001" (solid, pour order 64): 32.64,21.084 32.842,20.887 32.842,17.304 32.487,16.95 27.921,16.95 27.562,17.31 27.562,19.911 27.98,20.33 31.39,20.33 32.144,21.084
BOOST_SW on Ground2 "NONET_L-01_P-001" (solid, pour order 67): 36.409,41.671 36.409,41.235 35.786,40.612 31.645,40.612 30.88,39.848 30.88,37.435 29.643,36.198 25.776,36.198 25.349,36.625 25.349,41.41 25.731,41.792 36.288,41.792
no net on Top Solder "NONET_L-01_P-001" (solid): 30.016,44.927 38.412,44.927 38.412,44.926 38.412,43.274 30.016,43.274
no net on Top Solder "NONET_L-01_P-001" (solid): 38.676,27.5 44.176,27.5 44.176,19 38.676,19
no net on Top Solder "NONET_L-01_P-001" (solid): 25.138,54.269 27.638,54.269 27.638,51.035 25.138,51.035
no net on Top Solder "NONET_L-01_P-001" (solid): 109.244,38.493 111.844,38.493 111.844,37.193 109.244,37.193
no net on Top Solder "NONET_L-01_P-001" (solid): 35.722,38.917 38.222,38.917 38.222,37.417 35.722,37.417
no net on Top Solder "NONET_L-01_P-001" (solid): 35.674,15.288 34.312,15.288 34.312,36 35.674,36 35.674,18
no net on Top Solder "NONET_L-01_P-001" (solid): 12.141,72.5 12.141,82.966 13.641,82.966 13.641,72.5
no net on Top Solder "NONET_L-01_P-001" (solid): 14.641,72.5 14.641,82.966 16.141,82.966 16.141,72.5
no net on Top Solder "NONET_L-01_P-001" (solid): 37.641,72 37.641,82.966 39.141,82.966 39.141,72
no net on Top Solder "NONET_L-01_P-001" (solid): 35.141,72 35.141,82.966 36.641,82.966 36.641,72
no net on Top Solder "NONET_L-01_P-001" (solid): 27.174,59.5 27.174,65.75 28.674,65.75 28.674,59.5
no net on Top Solder "NONET_L-01_P-001" (solid): 16.174,59.5 16.174,65.25 19.674,65.25 19.674,59.5
no net on Top Solder "NONET_L-01_P-001" (solid): 43.924,67.5 47.674,67.5 47.674,65.5 43.924,65.5
no net on Top Solder "NONET_L-01_P-001" (solid): 40.674,65.75 43.174,65.75 43.174,60.25 40.674,60.25
no net on Top Solder "NONET_L-01_P-001" (solid): 36.674,65.75 39.174,65.75 39.174,60.25 36.674,60.25
no net on Top Solder "NONET_L-01_P-001" (solid): 31.998,56.516 34.498,56.516 34.498,51 31.998,51
no net on Top Solder "NONET_L-01_P-001" (solid): 28.498,56.516 30.998,56.516 30.998,51 28.498,51
no net on Top Solder "NONET_L-01_P-001" (solid): 31.993,54.317 34.493,54.317 34.493,52.817 31.993,52.817
no net on Top Solder "NONET_L-01_P-001" (solid): 28.493,54.317 30.993,54.317 30.993,52.817 28.493,52.817
no net on Top Solder "NONET_L-01_P-001" (solid): 50.924,31.5 53.424,31.5 53.424,28 50.924,28
no net on Top Solder "NONET_L-01_P-001" (solid): 50.924,29 53.424,29 53.424,27.5 50.924,27.5
no net on Top Solder "NONET_L-01_P-001" (solid): 49.653,26.445 52.153,26.445 52.153,24.945 49.653,24.945
no net on Top Solder "NONET_L-01_P-001" (solid): 47.924,29 50.424,29 50.424,27.5 47.924,27.5
no net on Top Solder "NONET_L-01_P-001" (solid): 47.924,31.5 50.424,31.5 50.424,28 47.924,28
no net on Top Solder "NONET_L-01_P-001" (solid): 36.924,36 45.174,36 45.174,33.5 36.924,33.5
no net on Top Solder "NONET_L-01_P-001" (solid): 38.174,29.5 43.674,29.5 43.674,27.5 38.174,27.5
no net on Bottom Solder "NONET_L-01_P-001" (solid): 28.121,45.275 25.174,45.275 25.174,43.486 28.121,43.486
no net on Bottom Solder "NONET_L-01_P-001" (solid): 103.144,61.449 107.144,61.449 107.144,57.706 103.144,57.706
no net on Bottom Solder "NONET_L-01_P-001" (solid): 38.719,43.261 30.174,43.261 30.174,45.112 38.474,45.112 38.694,44.892
no net on Bottom Solder "NONET_L-01_P-001" (solid): 56.174,20.251 53.174,20.251 53.174,18.331 56.174,18.331
no net on Bottom Solder "NONET_L-01_P-001" (solid): 57.02,35.512 55.02,35.512 55.02,27 57.02,27
no net on Bottom Solder "NONET_L-01_P-001" (solid): 27.744,30.388 25.744,30.388 25.744,26.453 27.744,26.453
no net on Bottom Solder "NONET_L-01_P-001" (solid): 30.71,30.353 28.71,30.353 28.71,26.5 30.71,26.5
no net on Bottom Solder "NONET_L-01_P-001" (solid): 47.187,72.577 47.187,70.577 48.687,70.577 48.687,72.577
no net on Bottom Solder "NONET_L-01_P-001" (solid): 44.687,72.577 44.687,70.577 46.187,70.577 46.187,72.577
no net on Bottom Solder "NONET_L-01_P-001" (solid): 46.187,69.577 46.187,60.39 47.687,60.39 47.687,69.577
no net on Bottom Solder "NONET_L-01_P-001" (solid): 43.687,69.577 43.687,60.398 45.187,60.398 45.187,69.577
no net on Bottom Solder "NONET_L-01_P-001" (solid): 36.174,82.181 11.674,82.181 11.674,71.5 36.174,71.5
no net on Bottom Solder "NONET_L-01_P-001" (solid): 53.174,23.014 56.174,23.014 56.174,24.943 53.174,24.943
no net on Bottom Solder "NONET_L-01_P-001" (solid): 31.25,57.486 29.25,57.486 29.25,51.5 31.25,51.5
no net on Bottom Solder "NONET_L-01_P-001" (solid): 34.25,58.486 32.25,58.486 32.25,52.5 34.25,52.5
no net on Bottom Solder "NONET_L-01_P-001" (solid): 28.174,49.5 25.174,49.5 25.174,47.5 28.174,47.5
no net on Bottom Solder "NONET_L-01_P-001" (solid): 27.75,40.986 25.75,40.986 25.75,37.5 27.75,37.5
no net on Bottom Solder "NONET_L-01_P-001" (solid): 27.75,38.486 25.75,38.486 25.75,36.986 27.75,36.986
no net on Bottom Solder "NONET_L-01_P-001" (solid): 30.674,38.5 28.674,38.5 28.674,37 30.674,37
no net on Bottom Solder "NONET_L-01_P-001" (solid): 30.674,41 28.674,41 28.674,37.5 30.674,37.5
no net on Bottom Solder "NONET_L-01_P-001" (solid): 31.174,24.486 28.174,24.486 28.174,22.678 31.174,22.678
no net on Bottom Solder "NONET_L-01_P-001" (solid): 31.034,19.986 28.264,19.986 28.264,18.248 31.034,18.248
no net on Bottom Solder "NONET_L-01_P-001" (solid): 49.797,35.487 47.797,35.487 47.797,27 49.797,27
no net on Bottom Solder "NONET_L-01_P-001" (solid): 53.297,35.487 51.297,35.487 51.297,27 53.297,27
no net on Bottom Solder "NONET_L-01_P-001" (solid): 33.954,16.53 33.954,16.647 34.339,17.032 34.339,27.724 34.411,27.797 36.161,27.797 36.221,27.737 36.221,15.337 36.172,15.288 34.009,15.288 33.973,15.324
no net on Bottom Solder "NONET_L-01_P-001" (solid): 41.596,25.827 39.596,25.827 39.596,24.327 41.596,24.327
no net on Bottom Solder "NONET_L-01_P-001" (solid): 41.603,28.15 39.603,28.15 39.603,26.65 41.603,26.65
no net on Bottom Solder "NONET_L-01_P-001" (solid): 46.174,20.75 44.174,20.75 44.174,19.25 46.174,19.25
no net on Bottom Solder "NONET_L-01_P-001" (solid): 46.758,18.694 44.758,18.694 44.758,17.194 46.758,17.194
no net on Bottom Solder "NONET_L-01_P-001" (solid): 45.674,23 43.674,23 43.674,21.5 45.674,21.5
no net on Bottom Solder "NONET_L-01_P-001" (solid): 44.624,27.334 42.624,27.334 42.624,25.834 44.624,25.834
no net on Bottom Solder "NONET_L-01_P-001" (solid): 45.176,25.25 43.176,25.25 43.176,23.75 45.176,23.75

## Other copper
Power1:
  pour cut-out: 36.369,38.078 37.038,38.747 37.944,38.747 38.558,38.132 38.558,37.223 37.962,36.626 36.895,36.626 36.369,37.152
  pour cut-out: 35.104,34.466 35.637,35 36.698,35 37.182,34.515 37.182,33.544 36.627,32.989 35.644,32.989 35.104,33.529
  pour cut-out: 0,0 0,9.5 9.5,9.5 9.5,0
  pour cut-out: 0,74.5 0,84 9.5,84 9.5,74.5
Ground1:
  pour cut-out: 35.104,34.466 35.637,35 36.698,35 37.182,34.515 37.182,33.544 36.627,32.989 35.644,32.989 35.104,33.529
  pour cut-out: 0,0 0,9.5 9.5,9.5 9.5,0
  pour cut-out: 0,74.5 0,84 9.5,84 9.5,74.5
  pour cut-out: 120,75 120,84 129.5,84 129.5,75
  pour cut-out: 118.095,0.5 118.095,14 129,14 129,0.5
  pour cut-out: 36.369,38.078 37.038,38.747 37.944,38.747 38.558,38.132 38.558,37.223 37.962,36.626 36.973,36.626 36.369,37.23
Ground2:
  pour cut-out: 0,0 0,9.5 9.5,9.5 9.5,0
  pour cut-out: 0,74.5 0,84 9.5,84 9.5,74.5
  pour cut-out: 36.369,38.078 37.038,38.747 37.944,38.747 38.558,38.132 38.558,37.223 37.962,36.626 36.973,36.626 36.369,37.23
  pour cut-out: 35.104,34.466 35.637,35 36.698,35 37.182,34.515 37.182,33.544 36.627,32.989 35.644,32.989 35.104,33.529
Power2:
  pour cut-out: 36.369,38.078 37.038,38.747 37.944,38.747 38.558,38.132 38.558,37.223 37.962,36.626 36.973,36.626 36.369,37.23
  pour cut-out: 31.896,48.766 32.095,48.566 37.441,48.566 37.443,48.569 37.443,48.774
  pour cut-out: 39.795,22.422 39.592,22.219 39.592,16.79 39.6,16.782 39.795,16.782
  pour cut-out: 35.104,34.466 35.637,35 36.568,35 37.182,34.386 37.182,33.544 36.627,32.989 35.644,32.989 35.104,33.529
  pour cut-out: 0,0 0,9.5 9.5,9.5 9.5,0
  pour cut-out: 0,74.5 0,84 9.5,84 9.5,74.5

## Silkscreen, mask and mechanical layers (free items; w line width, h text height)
M1 Board Outline:
  the board outline again, w0.254
M2 Board Dimensions:
  rectangle: -48.826,-30.842 -45.651,-27.667
  rectangle: -45.651,-34.017 -36.126,-30.842
  lines w0.178: -48.826,-30.842 -23.426,-30.842 ; -45.651,-34.017 -45.651,-27.667 ; -42.476,-34.017 -42.476,-27.667 ; -36.126,-34.017 -36.126,-27.667 ; -29.776,-34.017 -29.776,-27.667 ; -48.826,-34.017 -23.426,-34.017 -23.426,-27.667 -48.826,-27.667 -48.826,-34.017
M5 Assembly Top:
  lines w0.254: -56.243,-47.483 111.397,-47.483 ; -56.243,-42.319 111.448,-42.319 ; -56.243,-37.154 -56.243,-52.648 45.484,-52.648 111.448,-52.648 111.448,-37.154 -56.231,-37.154 -56.231,-52.648 -16.213,-52.648 ; 6.368,-52.648 6.368,-37.154 ; 38.55,-42.319 38.55,-37.154 ; 59.886,-42.319 59.886,-37.154 ; 75.684,-52.813 75.684,-47.661
  text "COMPONENTS MARKED 'DNP' SHOULD NOT BE POPULATED." at -19.528,-31.947 h1.52
  text "ASSEMBLY VARIANT:" at -19.54,-34.881 h1.52
  text ".VariantName" at 6.774,-34.881 h1.52
  text "PCB VIEWED FROM TOP SIDE" at -54.63,-40.511 h1.52
  text "BOARD #:" at 8.273,-40.511 h1.52
  text ".PRJ_Number" at 22.128,-40.511 h1.52
  text "REV:" at 43.579,-40.511 h1.52
  text ".PCB_Rev" at 50.983,-40.511 h1.52
  text "SVN REV:" at 64.864,-40.511 h1.52
  text ".VersionControl_RevNumber" at 77.716,-40.511 h1.52
  text "TID #:" at 8.273,-45.676 h1.52
  text ".TID" at 22.128,-45.676 h1.52
  text "PLOT NAME =" at -54.63,-50.891 h1.52
  text ".plot_File_Name" at -34.171,-50.891 h1.52
  text "GENERATED    :" at 8.324,-50.891 h1.52
  text ".Print_Date" at 30.409,-50.891 h1.52
  text ".Print_Time" at 48.925,-50.891 h1.52
  text "TEXAS INSTRUMENTS" at 81.044,-50.891 h1.52
M6 Assembly Bottom:
  lines w0.254: -56.256,-42.331 111.435,-42.331 ; -56.205,-47.496 111.435,-47.496 ; -20.493,-52.826 -20.493,-47.674 ; -4.694,-42.331 -4.694,-37.167 ; 16.642,-42.331 16.642,-37.167 ; 48.824,-52.661 48.824,-37.167 ; 71.404,-52.661 111.422,-52.661 111.422,-37.167 -56.256,-37.167 -56.256,-52.661 9.708,-52.661 111.435,-52.661 111.435,-37.167
  text "COMPONENTS MARKED 'DNP' SHOULD NOT BE POPULATED." at 106.164,-31.934 h1.52
  text ".VariantName" at 79.647,-34.881 h1.52
  text "ASSEMBLY VARIANT:" at 106.037,-34.881 h1.52
  text ".VersionControl_RevNumber" at -22.525,-40.524 h1.52
  text "SVN REV:" at -9.672,-40.524 h1.52
  text ".PCB_Rev" at 4.209,-40.524 h1.52
  text "REV:" at 11.613,-40.524 h1.52
  text ".PRJ_Number" at 33.063,-40.524 h1.52
  text "BOARD #:" at 46.919,-40.524 h1.52
  text "PCB VIEWED FROM BOTTOM SIDE" at 109.822,-40.524 h1.52
  text ".TID" at 33.063,-45.688 h1.52
  text "TID #:" at 46.919,-45.688 h1.52
  text "TEXAS INSTRUMENTS" at -25.852,-50.904 h1.52
  text ".Print_Time" at 6.266,-50.904 h1.52
  text ".Print_Date" at 24.783,-50.904 h1.52
  text "GENERATED    :" at 46.868,-50.904 h1.52
  text ".plot_File_Name" at 89.362,-50.904 h1.52
  text "PLOT NAME =" at 109.822,-50.904 h1.52
M9 Title Sheet:
  drawing of 57 lines, arcs and shapes, not listed
  text "1" at -30.035,180.27 h1.78
  text "2" at 33.355,180.27 h1.78
  text "3" at 96.585,180.27 h1.78
  text "4" at 160.254,180.27 h1.78
  text "5" at 223.728,180.27 h1.78
  text "6" at 287.355,180.27 h1.78
  text "A" at -59.406,151.238 h1.78
  text "A" at 316.514,151.238 h1.78
  text "B" at -59.406,90.786 h1.78
  text "B" at 316.514,90.786 h1.78
  text "C" at -59.406,30.461 h1.78
  text "C" at 316.514,30.461 h1.78
  text "PROJECT TITLE:" at 239.298,-16.809 h1.14
  text ".PRJ_Title" at 240.568,-20.195 h1.78
  text "DESIGNED FOR:" at 239.298,-24.454 h1.14
  text ".PRJ_Customer" at 240.568,-28.01 h1.78
  text "D" at -59.406,-29.737 h1.78
  text "D" at 316.514,-29.737 h1.78
  text "FILE NAME:" at 239.298,-32.074 h1.14
  text ".PCB_File_Name_No_Path" at 240.568,-35.122 h1.78
  text "Texas Instruments (TI) and/or its licensors do not warrant the accuracy or completeness of this specification" at 113.073,-39.233 h1.14
  text "ENGINEER:" at 239.298,-39.44 h1.14
  text "LAYOUT BY:" at 277.525,-39.44 h1.14
  text "or any information contained therein. TI and/or its licensors do not warrant that this design will meet" at 111.931,-42.094 h1.14
  text ".PRJ_Engineer" at 240.568,-43.377 h1.78
  text ".PCB_Layout" at 278.808,-43.377 h1.78
  text "the specifications, will be suitable for your application or fit for any particular purpose, or will operate in" at 111.931,-44.956 h1.14
  text ".Layer_Name" at -34.171,-45.663 h1.52
  text "ALTIUM DESIGNER VERSION:" at 277.525,-47.314 h1.14
  text "an implementation. TI and/or its licensors do not warrant that the design is production worthy. You should" at 111.931,-47.818 h1.14
  text "completely validate and test your design implementation to confirm the system functionality for your application." at 113.073,-50.68 h1.14
  text ".print_Scale" at 240.568,-50.701 h1.78
  text ".Application_BuildNumber" at 278.808,-50.701 h1.78
  text "1" at -30.035,-55.95 h1.78
  text "2" at 33.355,-55.95 h1.78
  text "3" at 96.585,-55.95 h1.78
  text "4" at 160.254,-55.95 h1.78
  text "5" at 223.728,-55.95 h1.78
  text "6" at 287.355,-55.95 h1.78
M10 Fab Notes:
  drawing of 189 lines, arcs and shapes, not listed
  text "DESIGN INFORMATION" at 265.677,137.59 h1.52
  text "MIN. TRACK WIDTH:" at 249.305,134.234 h1.52
  text "8" at 277.15,134.234 h1.52
  text "MIL" at 281.08,134.234 h1.52
  text "7.874" at 272.924,131.143 h1.52
  text "MIN. CLEARANCE:" at 249.305,131.081 h1.52
  text "MIL" at 281.08,131.081 h1.52
  text "MIN. VIA PAD SIZE:" at 249.305,127.928 h1.52
  text "24" at 276.388,127.928 h1.52
  text "MIL" at 281.08,127.928 h1.52
  text "0.05mm (2MIL)" at 266.958,124.629 h1.52
  text "MINIMUM ANNULAR RING" at 240.943,124.42 h1.52
  text "EXTERNAL" at 284.941,124.42 h1.52
  text "PER" at 246.023,121.623 h1.52
  text "IPC-D-275 CLASS 2 LEVEL C" at 251.611,121.622 h1.52
  text "MIL, HOLES" at 289.412,119.07 h1.52
  text "+/-" at 279.443,118.852 h1.52
  text "+/-" at 301.135,118.852 h1.52
  text "REGISTRATION TOLERANCES:" at 240.943,118.825 h1.52
  text "METAL" at 271.417,118.825 h1.52
  text "5" at 286.052,118.825 h1.52
  text "3" at 307.21,118.825 h1.52
  text "MIL" at 310.163,118.825 h1.52
  text "HOLE SIZE TOLERANCE (UNLESS OTHERWISE SPECIFIED):" at 240.943,116.328 h1.52
  text "+/-" at 301.135,116.255 h1.52
  text "3" at 307.21,116.228 h1.52
  text "MIL" at 310.163,116.228 h1.52
  text "MATERIAL:" at 239.043,112.732 h1.52
  text "FR-4 High Tg" at 264.099,109.467 h1.52
  text "X" at 260.43,109.264 h1.52
  text "FR-4" at 249.737,109.15 h1.52
  text "OTHER" at 287.532,109.15 h1.52
  text "62 MIL (1.6mm) +/-10%" at 257.867,105.517 h1.52
  text "X" at 254.817,105.454 h1.52
  text "THICKNESS:" at 240.943,105.308 h1.52
  text "OTHER" at 290.504,105.308 h1.52
  text "TOLERANCE:" at 240.943,101.795 h1.52
  text "X" at 262.488,101.795 h1.52
  text "ANSI IPC-6012 TYPE 3 CLASS 2" at 267.009,101.795 h1.52
  text "OTHER +/-" at 267.009,98.132 h1.52
  text "BOW & TWIST:" at 240.943,94.444 h1.52
  text "X" at 262.488,94.444 h1.52
  text "ANSI IPC-6012 TYPE 3 CLASS 2" at 267.009,94.444 h1.52
  text "OTHER +/-" at 267.009,90.718 h1.52
  text "DRILLING:" at 239.043,87.401 h1.52
  text "NC_DRILL FILES" at 283.773,84.729 h1.52
  text "REFERENCE:" at 240.943,84.629 h1.52
  text "X" at 257.636,84.626 h1.52
  text "AS SHOWN" at 262.157,84.629 h1.52
  text "X" at 280.522,84.629 h1.52
  text "OTHER" at 291.342,81.016 h1.52
  text "PTH COPPER THICKNESS:" at 240.934,80.926 h1.52
  text "X" at 269.871,80.926 h1.52
  text "20-30 um" at 273.122,80.926 h1.52
  text "BOARD FINISH:" at 239.043,77.177 h1.52
  text "SILKSCREEN:" at 242.986,74.38 h1.52
  text "X" at 267.314,74.38 h1.52
  text "TOP" at 270.285,74.38 h1.52
  text "X" at 280.268,74.38 h1.52
  text "BOTTOM" at 283.265,74.38 h1.52
  text "SILKSCREEN COLOR:" at 242.986,70.438 h1.52
  text "X" at 267.288,70.438 h1.52
  text "WHITE" at 270.285,70.438 h1.52
  text "OTHER" at 283.265,70.438 h1.52
  text "X" at 270.616,66.795 h1.52
  text "GREEN" at 273.613,66.795 h1.52
  text "OTHER" at 289.31,66.795 h1.52
  text "SOLDER RESIST COLOR:" at 242.986,66.62 h1.52
  text "X" at 270.616,62.877 h1.52
  text "MATTE" at 273.613,62.877 h1.52
  text "SEMI-GLOSS" at 289.298,62.86 h1.52
  text "IMMERSION GOLD (ENIG)" at 265.993,58.488 h1.52
  text "ENEPIG" at 299.966,58.305 h1.52
  text "SURFACE FINISH:" at 239.043,58.279 h1.52
  text "X" at 261.472,58.279 h1.52
  text "IMM. TIN/SILVER OR EQUIV" at 247.414,54.791 h1.52
  text "OTHER" at 283.773,54.691 h1.52
  text "ARRAY/PANEL:" at 239.043,50.745 h1.52
  text "CUT AND TRIM PER M1 BOARD OUTLINE" at 265.993,50.536 h1.52
  text "N.C. ROUTE" at 265.993,47.082 h1.52
  text "X" at 283.468,47.082 h1.52
  text "V. SCORE" at 287.989,47.082 h1.52
  text "CERTIFICATION:" at 239.043,43.803 h1.52
  text "MATERIALS AND WORKMANSHIP FOR ALL PCBS" at 257.458,43.803 h1.52
  text "TO MEET OR EXCEED THE REQUIREMENTS OF:" at 257.458,41.413 h1.52
  text "X" at 248.251,38.146 h1.52
  text "ANSI IPC-A-600F CLASS ->" at 251.502,38.146 h1.52
  text "X" at 293.362,38.146 h1.52
  text "2" at 296.155,38.146 h1.52
  text "1" at 288.154,38.108 h1.52
  text "3" at 305.147,38.108 h1.52
  text "X" at 268.876,34.395 h1.52
  text "RoHS" at 272.127,34.395 h1.52
  text "OTHER" at 288.495,34.395 h1.52
  text "PER ORDER" at 298.58,34.395 h1.52
  text "ALL BOARDS MUST MEET OR EXCEED UL94-V0 REQUIREMENTS." at 239.743,30.488 h1.52
  text "PCB MUST BEAR THE UL94V-0 UL REGISTERED MATERIAL ID NUMBER" at 239.743,27.54 h1.52
  text "ADDITIONAL REQUIREMENTS:" at 239.043,23.236 h1.52
  text "MICROSECTION:" at 240.943,20.515 h1.52
  text "YES" at 263.948,20.515 h1.52
  text "REQUIRED" at 285.83,16.849 h1.52
  text "BARE BOARD ELEC. TEST:" at 240.943,16.777 h1.52
  text "NONE" at 274.108,16.777 h1.52
  text "X" at 282.833,16.777 h1.52
  text "PER ORDER" at 300.867,16.777 h1.52
  text "XX MIL VIAS REQUIRE NON-CONDUCTIVE FILL AND PLANARIZE" at 245.214,11.571 h1.5
  text "XX MIL VIAS REQUIRE CONDUCTIVE FILL AND PLANARIZE" at 245.417,8.93 h1.52
  text "OUTER XX MIL TRACES REQUIRE 50 OHM SINGLE-ENDED IMPEDANCE" at 245.392,4.78 h1.47
  text "LAYER 2 & 3 (INNER LAYERS) XX MIL WIDE, XX MIL SPACE / TRACES REQUIRE 100 OHM DIFFERENTIAL IMPEDANCE" at 245.189,-1.207 h1.52
M11 Gerber Information:
  lines w0.254: -56.243,-47.483 111.397,-47.483 ; -56.243,-42.319 111.448,-42.319 ; -56.243,-37.154 -56.243,-52.648 45.484,-52.648 111.448,-52.648 111.448,-37.154 -56.231,-37.154 -56.231,-52.648 -16.213,-52.648 ; 6.368,-52.648 6.368,-37.154 ; 38.55,-42.319 38.55,-37.154 ; 59.886,-42.319 59.886,-37.154 ; 75.684,-52.813 75.684,-47.661
  text "ALL ARTWORK VIEWED FROM TOP SIDE" at -54.63,-40.511 h1.52
  text "BOARD #:" at 8.273,-40.511 h1.52
  text ".PRJ_Number" at 22.128,-40.511 h1.52
  text "REV:" at 43.579,-40.511 h1.52
  text ".PCB_Rev" at 50.983,-40.511 h1.52
  text "SVN REV:" at 64.864,-40.511 h1.52
  text ".VersionControl_RevNumber" at 77.716,-40.511 h1.52
  text "LAYER NAME =" at -54.63,-45.663 h1.52
  text "TID #:" at 8.273,-45.676 h1.52
  text ".TID" at 22.128,-45.676 h1.52
  text "PLOT NAME =" at -54.63,-50.891 h1.52
  text ".plot_File_Name" at -34.171,-50.891 h1.52
  text "GENERATED    :" at 8.324,-50.891 h1.52
  text ".Print_Date" at 30.409,-50.891 h1.52
  text ".Print_Time" at 48.925,-50.891 h1.52
  text "TEXAS INSTRUMENTS" at 81.044,-50.891 h1.52
M12 Stackup:
  drawing of 295 lines, arcs and shapes, not listed
  text "Layer" at 200.642,176.166 h1.52
  text "Name" at 211.054,176.166 h1.52
  text "Material" at 234.669,176.166 h1.52
  text "Thickness" at 256.507,176.166 h1.52
  text "Constant" at 273.013,176.166 h1.52
  text "Board Layer Stack" at 287.488,176.166 h1.52
  text "Top Overlay" at 211.054,173.118 h1.52
  text "Top Solder" at 211.054,170.07 h1.52
  text "Solder Resist" at 234.669,170.07 h1.52
  text "0.40mil" at 256.507,170.07 h1.52
  text "3.5" at 273.013,170.07 h1.52
  text "1" at 200.642,167.022 h1.52
  text "Power1" at 211.054,167.022 h1.52
  text "CF-004" at 234.669,167.022 h1.52
  text "2.76mil" at 256.507,167.022 h1.52
  text "Dielectric 1" at 211.054,163.974 h1.52
  text "PP-006" at 234.669,163.974 h1.52
  text "2.80mil" at 256.507,163.974 h1.52
  text "4.1" at 273.013,163.974 h1.52
  text "2" at 200.642,160.926 h1.52
  text "Ground1" at 211.054,160.926 h1.52
  text "2.76mil" at 256.507,160.926 h1.52
  text "Dielectric1" at 211.054,157.878 h1.52
  text "FR-4 High Tg" at 234.669,157.878 h1.52
  text "59.20mil" at 256.507,157.878 h1.52
  text "4.8" at 273.013,157.878 h1.52
  text "3" at 200.642,154.83 h1.52
  text "Ground2" at 211.054,154.83 h1.52
  text "2.76mil" at 256.507,154.83 h1.52
  text "Dielectric 2" at 211.054,151.782 h1.52
  text "PP-006" at 234.669,151.782 h1.52
  text "2.80mil" at 256.507,151.782 h1.52
  text "4.1" at 273.013,151.782 h1.52
  text "4" at 200.642,148.734 h1.52
  text "Power2" at 211.054,148.734 h1.52
  text "CF-004" at 234.669,148.734 h1.52
  text "2.76mil" at 256.507,148.734 h1.52
  text "Bottom Solder" at 211.054,145.686 h1.52
  text "Solder Resist" at 234.669,145.686 h1.52
  text "0.40mil" at 256.507,145.686 h1.52
  text "3.5" at 273.013,145.686 h1.52
  text "Bottom Overlay" at 211.054,142.638 h1.52
M17 Embedded Cavity:
  text ".Layer_Name" at -34.171,-45.663 h1.52
M18 Embedded Assembly:
  text ".Layer_Name" at -34.171,-45.663 h1.52
M19 Embedded Keepout:
  text ".Layer_Name" at -34.171,-45.663 h1.52

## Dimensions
-48.826,-34.017 to -23.426,-34.017 on M2 Board Dimensions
